VERSION 5.8 ;
BUSBITCHARS "[]" ;
DIVIDERCHAR "/" ;
UNITS
    DATABASE MICRONS 1000 ;
END UNITS

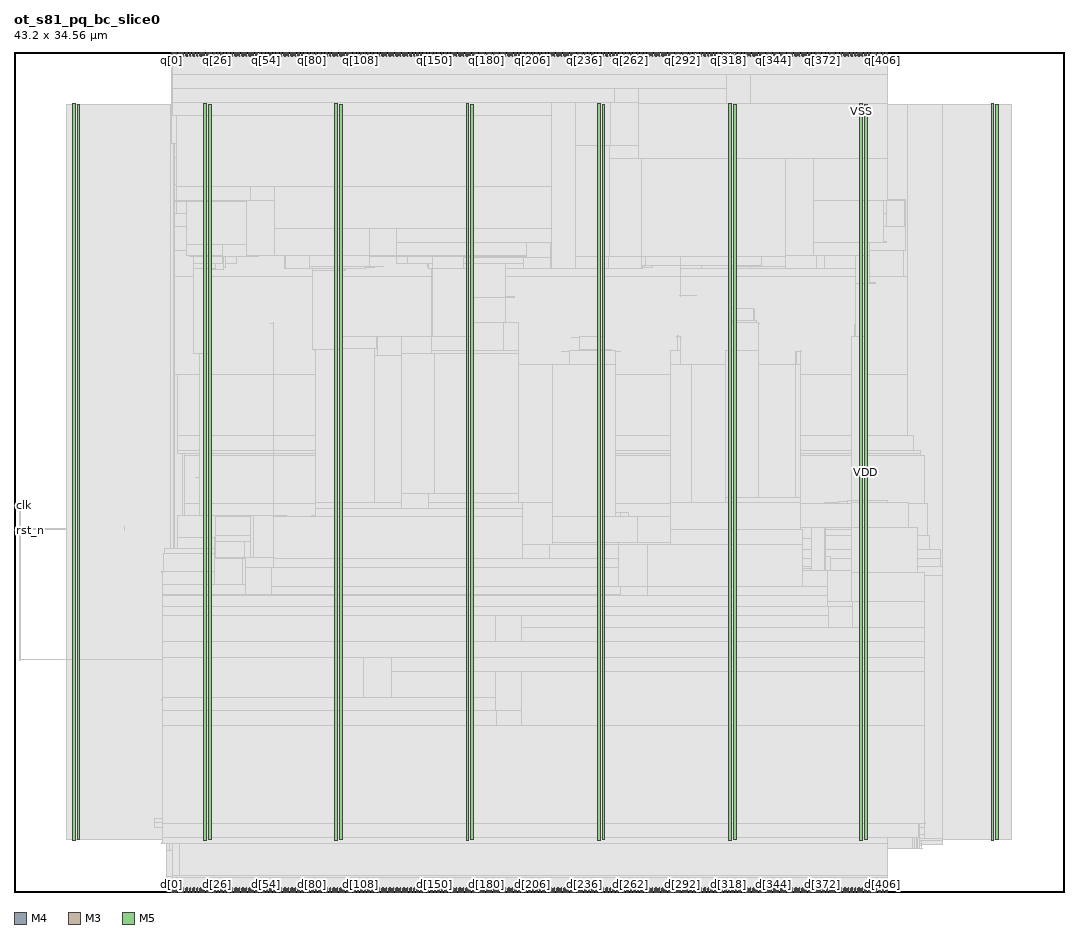
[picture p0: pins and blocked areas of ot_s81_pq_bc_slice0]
MACRO ot_s81_pq_bc_slice0
  FOREIGN ot_s81_pq_bc_slice0 0 0 ;
  CLASS BLOCK ;
  SIZE 43.2 BY 34.56 ;
  PIN clk
    DIRECTION INPUT ;
    USE SIGNAL ;
    PORT
      LAYER M4 ;
        RECT  0 15.888 0.192 15.912 ;
    END
    PORT
      LAYER M4 ;
        RECT  0.156 15.888 0.275 15.912 ;
    END
  END clk
  PIN d[0]
    DIRECTION INPUT ;
    USE SIGNAL ;
    PORT
      LAYER M3 ;
        RECT  6.48 0 6.498 0.144 ;
    END
  END d[0]
  PIN d[100]
    DIRECTION INPUT ;
    USE SIGNAL ;
    PORT
      LAYER M3 ;
        RECT  13.68 0 13.698 0.144 ;
    END
  END d[100]
  PIN d[101]
    DIRECTION INPUT ;
    USE SIGNAL ;
    PORT
      LAYER M5 ;
        RECT  13.728 0 13.752 0.192 ;
    END
  END d[101]
  PIN d[102]
    DIRECTION INPUT ;
    USE SIGNAL ;
    PORT
      LAYER M3 ;
        RECT  13.824 0 13.842 0.144 ;
    END
  END d[102]
  PIN d[103]
    DIRECTION INPUT ;
    USE SIGNAL ;
    PORT
      LAYER M5 ;
        RECT  13.872 0 13.896 0.192 ;
    END
  END d[103]
  PIN d[104]
    DIRECTION INPUT ;
    USE SIGNAL ;
    PORT
      LAYER M3 ;
        RECT  13.968 0 13.986 0.144 ;
    END
  END d[104]
  PIN d[105]
    DIRECTION INPUT ;
    USE SIGNAL ;
    PORT
      LAYER M5 ;
        RECT  14.016 0 14.04 0.192 ;
    END
  END d[105]
  PIN d[106]
    DIRECTION INPUT ;
    USE SIGNAL ;
    PORT
      LAYER M3 ;
        RECT  14.112 0 14.13 0.144 ;
    END
  END d[106]
  PIN d[107]
    DIRECTION INPUT ;
    USE SIGNAL ;
    PORT
      LAYER M5 ;
        RECT  14.16 0 14.184 0.192 ;
    END
  END d[107]
  PIN d[108]
    DIRECTION INPUT ;
    USE SIGNAL ;
    PORT
      LAYER M3 ;
        RECT  14.256 0 14.274 0.144 ;
    END
  END d[108]
  PIN d[109]
    DIRECTION INPUT ;
    USE SIGNAL ;
    PORT
      LAYER M5 ;
        RECT  14.304 0 14.328 0.192 ;
    END
  END d[109]
  PIN d[10]
    DIRECTION INPUT ;
    USE SIGNAL ;
    PORT
      LAYER M3 ;
        RECT  7.2 0 7.218 0.144 ;
    END
  END d[10]
  PIN d[110]
    DIRECTION INPUT ;
    USE SIGNAL ;
    PORT
      LAYER M3 ;
        RECT  14.4 0 14.418 0.144 ;
    END
  END d[110]
  PIN d[111]
    DIRECTION INPUT ;
    USE SIGNAL ;
    PORT
      LAYER M5 ;
        RECT  14.448 0 14.472 0.192 ;
    END
  END d[111]
  PIN d[112]
    DIRECTION INPUT ;
    USE SIGNAL ;
    PORT
      LAYER M3 ;
        RECT  14.544 0 14.562 0.144 ;
    END
  END d[112]
  PIN d[113]
    DIRECTION INPUT ;
    USE SIGNAL ;
    PORT
      LAYER M5 ;
        RECT  14.592 0 14.616 0.192 ;
    END
  END d[113]
  PIN d[114]
    DIRECTION INPUT ;
    USE SIGNAL ;
    PORT
      LAYER M3 ;
        RECT  14.688 0 14.706 0.144 ;
    END
  END d[114]
  PIN d[115]
    DIRECTION INPUT ;
    USE SIGNAL ;
    PORT
      LAYER M5 ;
        RECT  14.736 0 14.76 0.192 ;
    END
  END d[115]
  PIN d[116]
    DIRECTION INPUT ;
    USE SIGNAL ;
    PORT
      LAYER M3 ;
        RECT  14.832 0 14.85 0.144 ;
    END
  END d[116]
  PIN d[117]
    DIRECTION INPUT ;
    USE SIGNAL ;
    PORT
      LAYER M5 ;
        RECT  14.88 0 14.904 0.192 ;
    END
  END d[117]
  PIN d[118]
    DIRECTION INPUT ;
    USE SIGNAL ;
    PORT
      LAYER M3 ;
        RECT  14.976 0 14.994 0.144 ;
    END
  END d[118]
  PIN d[119]
    DIRECTION INPUT ;
    USE SIGNAL ;
    PORT
      LAYER M5 ;
        RECT  15.024 0 15.048 0.192 ;
    END
  END d[119]
  PIN d[11]
    DIRECTION INPUT ;
    USE SIGNAL ;
    PORT
      LAYER M5 ;
        RECT  7.248 0 7.272 0.192 ;
    END
  END d[11]
  PIN d[120]
    DIRECTION INPUT ;
    USE SIGNAL ;
    PORT
      LAYER M3 ;
        RECT  15.12 0 15.138 0.144 ;
    END
  END d[120]
  PIN d[121]
    DIRECTION INPUT ;
    USE SIGNAL ;
    PORT
      LAYER M5 ;
        RECT  15.168 0 15.192 0.192 ;
    END
  END d[121]
  PIN d[122]
    DIRECTION INPUT ;
    USE SIGNAL ;
    PORT
      LAYER M3 ;
        RECT  15.264 0 15.282 0.144 ;
    END
  END d[122]
  PIN d[123]
    DIRECTION INPUT ;
    USE SIGNAL ;
    PORT
      LAYER M5 ;
        RECT  15.312 0 15.336 0.192 ;
    END
  END d[123]
  PIN d[124]
    DIRECTION INPUT ;
    USE SIGNAL ;
    PORT
      LAYER M3 ;
        RECT  15.408 0 15.426 0.144 ;
    END
  END d[124]
  PIN d[125]
    DIRECTION INPUT ;
    USE SIGNAL ;
    PORT
      LAYER M5 ;
        RECT  15.456 0 15.48 0.192 ;
    END
  END d[125]
  PIN d[126]
    DIRECTION INPUT ;
    USE SIGNAL ;
    PORT
      LAYER M3 ;
        RECT  15.552 0 15.57 0.144 ;
    END
  END d[126]
  PIN d[127]
    DIRECTION INPUT ;
    USE SIGNAL ;
    PORT
      LAYER M5 ;
        RECT  15.6 0 15.624 0.192 ;
    END
  END d[127]
  PIN d[128]
    DIRECTION INPUT ;
    USE SIGNAL ;
    PORT
      LAYER M3 ;
        RECT  15.696 0 15.714 0.144 ;
    END
  END d[128]
  PIN d[129]
    DIRECTION INPUT ;
    USE SIGNAL ;
    PORT
      LAYER M5 ;
        RECT  15.744 0 15.768 0.192 ;
    END
  END d[129]
  PIN d[12]
    DIRECTION INPUT ;
    USE SIGNAL ;
    PORT
      LAYER M3 ;
        RECT  7.344 0 7.362 0.144 ;
    END
  END d[12]
  PIN d[130]
    DIRECTION INPUT ;
    USE SIGNAL ;
    PORT
      LAYER M3 ;
        RECT  15.84 0 15.858 0.144 ;
    END
  END d[130]
  PIN d[131]
    DIRECTION INPUT ;
    USE SIGNAL ;
    PORT
      LAYER M5 ;
        RECT  15.888 0 15.912 0.192 ;
    END
  END d[131]
  PIN d[132]
    DIRECTION INPUT ;
    USE SIGNAL ;
    PORT
      LAYER M3 ;
        RECT  15.984 0 16.002 0.144 ;
    END
  END d[132]
  PIN d[133]
    DIRECTION INPUT ;
    USE SIGNAL ;
    PORT
      LAYER M5 ;
        RECT  16.032 0 16.056 0.192 ;
    END
  END d[133]
  PIN d[134]
    DIRECTION INPUT ;
    USE SIGNAL ;
    PORT
      LAYER M3 ;
        RECT  16.128 0 16.146 0.144 ;
    END
  END d[134]
  PIN d[135]
    DIRECTION INPUT ;
    USE SIGNAL ;
    PORT
      LAYER M5 ;
        RECT  16.176 0 16.2 0.192 ;
    END
  END d[135]
  PIN d[136]
    DIRECTION INPUT ;
    USE SIGNAL ;
    PORT
      LAYER M3 ;
        RECT  16.272 0 16.29 0.144 ;
    END
  END d[136]
  PIN d[137]
    DIRECTION INPUT ;
    USE SIGNAL ;
    PORT
      LAYER M5 ;
        RECT  16.32 0 16.344 0.192 ;
    END
  END d[137]
  PIN d[138]
    DIRECTION INPUT ;
    USE SIGNAL ;
    PORT
      LAYER M3 ;
        RECT  16.416 0 16.434 0.144 ;
    END
  END d[138]
  PIN d[139]
    DIRECTION INPUT ;
    USE SIGNAL ;
    PORT
      LAYER M5 ;
        RECT  16.464 0 16.488 0.192 ;
    END
  END d[139]
  PIN d[13]
    DIRECTION INPUT ;
    USE SIGNAL ;
    PORT
      LAYER M5 ;
        RECT  7.392 0 7.416 0.192 ;
    END
  END d[13]
  PIN d[140]
    DIRECTION INPUT ;
    USE SIGNAL ;
    PORT
      LAYER M3 ;
        RECT  16.56 0 16.578 0.144 ;
    END
  END d[140]
  PIN d[141]
    DIRECTION INPUT ;
    USE SIGNAL ;
    PORT
      LAYER M5 ;
        RECT  16.608 0 16.632 0.192 ;
    END
  END d[141]
  PIN d[142]
    DIRECTION INPUT ;
    USE SIGNAL ;
    PORT
      LAYER M3 ;
        RECT  16.704 0 16.722 0.144 ;
    END
  END d[142]
  PIN d[143]
    DIRECTION INPUT ;
    USE SIGNAL ;
    PORT
      LAYER M5 ;
        RECT  16.752 0 16.776 0.192 ;
    END
  END d[143]
  PIN d[144]
    DIRECTION INPUT ;
    USE SIGNAL ;
    PORT
      LAYER M3 ;
        RECT  16.848 0 16.866 0.144 ;
    END
  END d[144]
  PIN d[145]
    DIRECTION INPUT ;
    USE SIGNAL ;
    PORT
      LAYER M5 ;
        RECT  16.896 0 16.92 0.192 ;
    END
  END d[145]
  PIN d[146]
    DIRECTION INPUT ;
    USE SIGNAL ;
    PORT
      LAYER M3 ;
        RECT  16.992 0 17.01 0.144 ;
    END
  END d[146]
  PIN d[147]
    DIRECTION INPUT ;
    USE SIGNAL ;
    PORT
      LAYER M5 ;
        RECT  17.04 0 17.064 0.192 ;
    END
  END d[147]
  PIN d[148]
    DIRECTION INPUT ;
    USE SIGNAL ;
    PORT
      LAYER M3 ;
        RECT  17.136 0 17.154 0.144 ;
    END
  END d[148]
  PIN d[149]
    DIRECTION INPUT ;
    USE SIGNAL ;
    PORT
      LAYER M5 ;
        RECT  17.184 0 17.208 0.192 ;
    END
  END d[149]
  PIN d[14]
    DIRECTION INPUT ;
    USE SIGNAL ;
    PORT
      LAYER M3 ;
        RECT  7.488 0 7.506 0.144 ;
    END
  END d[14]
  PIN d[150]
    DIRECTION INPUT ;
    USE SIGNAL ;
    PORT
      LAYER M3 ;
        RECT  17.28 0 17.298 0.144 ;
    END
  END d[150]
  PIN d[151]
    DIRECTION INPUT ;
    USE SIGNAL ;
    PORT
      LAYER M5 ;
        RECT  17.328 0 17.352 0.192 ;
    END
  END d[151]
  PIN d[152]
    DIRECTION INPUT ;
    USE SIGNAL ;
    PORT
      LAYER M3 ;
        RECT  17.424 0 17.442 0.144 ;
    END
  END d[152]
  PIN d[153]
    DIRECTION INPUT ;
    USE SIGNAL ;
    PORT
      LAYER M5 ;
        RECT  17.472 0 17.496 0.192 ;
    END
  END d[153]
  PIN d[154]
    DIRECTION INPUT ;
    USE SIGNAL ;
    PORT
      LAYER M3 ;
        RECT  17.568 0 17.586 0.144 ;
    END
  END d[154]
  PIN d[155]
    DIRECTION INPUT ;
    USE SIGNAL ;
    PORT
      LAYER M5 ;
        RECT  17.616 0 17.64 0.192 ;
    END
  END d[155]
  PIN d[156]
    DIRECTION INPUT ;
    USE SIGNAL ;
    PORT
      LAYER M3 ;
        RECT  17.712 0 17.73 0.144 ;
    END
  END d[156]
  PIN d[157]
    DIRECTION INPUT ;
    USE SIGNAL ;
    PORT
      LAYER M5 ;
        RECT  17.76 0 17.784 0.192 ;
    END
  END d[157]
  PIN d[158]
    DIRECTION INPUT ;
    USE SIGNAL ;
    PORT
      LAYER M3 ;
        RECT  17.856 0 17.874 0.144 ;
    END
  END d[158]
  PIN d[159]
    DIRECTION INPUT ;
    USE SIGNAL ;
    PORT
      LAYER M5 ;
        RECT  17.904 0 17.928 0.192 ;
    END
  END d[159]
  PIN d[15]
    DIRECTION INPUT ;
    USE SIGNAL ;
    PORT
      LAYER M5 ;
        RECT  7.536 0 7.56 0.192 ;
    END
  END d[15]
  PIN d[160]
    DIRECTION INPUT ;
    USE SIGNAL ;
    PORT
      LAYER M3 ;
        RECT  18 0 18.018 0.144 ;
    END
  END d[160]
  PIN d[161]
    DIRECTION INPUT ;
    USE SIGNAL ;
    PORT
      LAYER M5 ;
        RECT  18.048 0 18.072 0.192 ;
    END
  END d[161]
  PIN d[162]
    DIRECTION INPUT ;
    USE SIGNAL ;
    PORT
      LAYER M3 ;
        RECT  18.144 0 18.162 0.144 ;
    END
  END d[162]
  PIN d[163]
    DIRECTION INPUT ;
    USE SIGNAL ;
    PORT
      LAYER M5 ;
        RECT  18.192 0 18.216 0.192 ;
    END
  END d[163]
  PIN d[164]
    DIRECTION INPUT ;
    USE SIGNAL ;
    PORT
      LAYER M3 ;
        RECT  18.288 0 18.306 0.144 ;
    END
  END d[164]
  PIN d[165]
    DIRECTION INPUT ;
    USE SIGNAL ;
    PORT
      LAYER M5 ;
        RECT  18.336 0 18.36 0.192 ;
    END
  END d[165]
  PIN d[166]
    DIRECTION INPUT ;
    USE SIGNAL ;
    PORT
      LAYER M3 ;
        RECT  18.432 0 18.45 0.144 ;
    END
  END d[166]
  PIN d[167]
    DIRECTION INPUT ;
    USE SIGNAL ;
    PORT
      LAYER M5 ;
        RECT  18.48 0 18.504 0.192 ;
    END
  END d[167]
  PIN d[168]
    DIRECTION INPUT ;
    USE SIGNAL ;
    PORT
      LAYER M3 ;
        RECT  18.576 0 18.594 0.144 ;
    END
  END d[168]
  PIN d[169]
    DIRECTION INPUT ;
    USE SIGNAL ;
    PORT
      LAYER M5 ;
        RECT  18.624 0 18.648 0.192 ;
    END
  END d[169]
  PIN d[16]
    DIRECTION INPUT ;
    USE SIGNAL ;
    PORT
      LAYER M3 ;
        RECT  7.632 0 7.65 0.144 ;
    END
  END d[16]
  PIN d[170]
    DIRECTION INPUT ;
    USE SIGNAL ;
    PORT
      LAYER M3 ;
        RECT  18.72 0 18.738 0.144 ;
    END
  END d[170]
  PIN d[171]
    DIRECTION INPUT ;
    USE SIGNAL ;
    PORT
      LAYER M5 ;
        RECT  18.768 0 18.792 0.192 ;
    END
  END d[171]
  PIN d[172]
    DIRECTION INPUT ;
    USE SIGNAL ;
    PORT
      LAYER M3 ;
        RECT  18.864 0 18.882 0.144 ;
    END
  END d[172]
  PIN d[173]
    DIRECTION INPUT ;
    USE SIGNAL ;
    PORT
      LAYER M5 ;
        RECT  18.912 0 18.936 0.192 ;
    END
  END d[173]
  PIN d[174]
    DIRECTION INPUT ;
    USE SIGNAL ;
    PORT
      LAYER M3 ;
        RECT  19.008 0 19.026 0.144 ;
    END
  END d[174]
  PIN d[175]
    DIRECTION INPUT ;
    USE SIGNAL ;
    PORT
      LAYER M5 ;
        RECT  19.056 0 19.08 0.192 ;
    END
  END d[175]
  PIN d[176]
    DIRECTION INPUT ;
    USE SIGNAL ;
    PORT
      LAYER M3 ;
        RECT  19.152 0 19.17 0.144 ;
    END
  END d[176]
  PIN d[177]
    DIRECTION INPUT ;
    USE SIGNAL ;
    PORT
      LAYER M5 ;
        RECT  19.2 0 19.224 0.192 ;
    END
  END d[177]
  PIN d[178]
    DIRECTION INPUT ;
    USE SIGNAL ;
    PORT
      LAYER M3 ;
        RECT  19.296 0 19.314 0.144 ;
    END
  END d[178]
  PIN d[179]
    DIRECTION INPUT ;
    USE SIGNAL ;
    PORT
      LAYER M5 ;
        RECT  19.344 0 19.368 0.192 ;
    END
  END d[179]
  PIN d[17]
    DIRECTION INPUT ;
    USE SIGNAL ;
    PORT
      LAYER M5 ;
        RECT  7.68 0 7.704 0.192 ;
    END
  END d[17]
  PIN d[180]
    DIRECTION INPUT ;
    USE SIGNAL ;
    PORT
      LAYER M3 ;
        RECT  19.44 0 19.458 0.144 ;
    END
  END d[180]
  PIN d[181]
    DIRECTION INPUT ;
    USE SIGNAL ;
    PORT
      LAYER M5 ;
        RECT  19.488 0 19.512 0.192 ;
    END
  END d[181]
  PIN d[182]
    DIRECTION INPUT ;
    USE SIGNAL ;
    PORT
      LAYER M3 ;
        RECT  19.584 0 19.602 0.144 ;
    END
  END d[182]
  PIN d[183]
    DIRECTION INPUT ;
    USE SIGNAL ;
    PORT
      LAYER M5 ;
        RECT  19.632 0 19.656 0.192 ;
    END
  END d[183]
  PIN d[184]
    DIRECTION INPUT ;
    USE SIGNAL ;
    PORT
      LAYER M3 ;
        RECT  19.728 0 19.746 0.144 ;
    END
  END d[184]
  PIN d[185]
    DIRECTION INPUT ;
    USE SIGNAL ;
    PORT
      LAYER M5 ;
        RECT  19.776 0 19.8 0.192 ;
    END
  END d[185]
  PIN d[186]
    DIRECTION INPUT ;
    USE SIGNAL ;
    PORT
      LAYER M3 ;
        RECT  19.872 0 19.89 0.144 ;
    END
  END d[186]
  PIN d[187]
    DIRECTION INPUT ;
    USE SIGNAL ;
    PORT
      LAYER M5 ;
        RECT  19.92 0 19.944 0.192 ;
    END
  END d[187]
  PIN d[188]
    DIRECTION INPUT ;
    USE SIGNAL ;
    PORT
      LAYER M3 ;
        RECT  20.016 0 20.034 0.144 ;
    END
  END d[188]
  PIN d[189]
    DIRECTION INPUT ;
    USE SIGNAL ;
    PORT
      LAYER M5 ;
        RECT  20.064 0 20.088 0.192 ;
    END
  END d[189]
  PIN d[18]
    DIRECTION INPUT ;
    USE SIGNAL ;
    PORT
      LAYER M3 ;
        RECT  7.776 0 7.794 0.144 ;
    END
  END d[18]
  PIN d[190]
    DIRECTION INPUT ;
    USE SIGNAL ;
    PORT
      LAYER M3 ;
        RECT  20.16 0 20.178 0.144 ;
    END
  END d[190]
  PIN d[191]
    DIRECTION INPUT ;
    USE SIGNAL ;
    PORT
      LAYER M5 ;
        RECT  20.208 0 20.232 0.192 ;
    END
  END d[191]
  PIN d[192]
    DIRECTION INPUT ;
    USE SIGNAL ;
    PORT
      LAYER M3 ;
        RECT  20.304 0 20.322 0.144 ;
    END
  END d[192]
  PIN d[193]
    DIRECTION INPUT ;
    USE SIGNAL ;
    PORT
      LAYER M5 ;
        RECT  20.352 0 20.376 0.192 ;
    END
  END d[193]
  PIN d[194]
    DIRECTION INPUT ;
    USE SIGNAL ;
    PORT
      LAYER M3 ;
        RECT  20.448 0 20.466 0.144 ;
    END
  END d[194]
  PIN d[195]
    DIRECTION INPUT ;
    USE SIGNAL ;
    PORT
      LAYER M5 ;
        RECT  20.496 0 20.52 0.192 ;
    END
  END d[195]
  PIN d[196]
    DIRECTION INPUT ;
    USE SIGNAL ;
    PORT
      LAYER M3 ;
        RECT  20.592 0 20.61 0.144 ;
    END
  END d[196]
  PIN d[197]
    DIRECTION INPUT ;
    USE SIGNAL ;
    PORT
      LAYER M5 ;
        RECT  20.64 0 20.664 0.192 ;
    END
  END d[197]
  PIN d[198]
    DIRECTION INPUT ;
    USE SIGNAL ;
    PORT
      LAYER M3 ;
        RECT  20.736 0 20.754 0.144 ;
    END
  END d[198]
  PIN d[199]
    DIRECTION INPUT ;
    USE SIGNAL ;
    PORT
      LAYER M5 ;
        RECT  20.784 0 20.808 0.192 ;
    END
  END d[199]
  PIN d[19]
    DIRECTION INPUT ;
    USE SIGNAL ;
    PORT
      LAYER M5 ;
        RECT  7.824 0 7.848 0.192 ;
    END
  END d[19]
  PIN d[1]
    DIRECTION INPUT ;
    USE SIGNAL ;
    PORT
      LAYER M5 ;
        RECT  6.528 0 6.552 0.192 ;
    END
  END d[1]
  PIN d[200]
    DIRECTION INPUT ;
    USE SIGNAL ;
    PORT
      LAYER M3 ;
        RECT  20.88 0 20.898 0.144 ;
    END
  END d[200]
  PIN d[201]
    DIRECTION INPUT ;
    USE SIGNAL ;
    PORT
      LAYER M5 ;
        RECT  20.928 0 20.952 0.192 ;
    END
  END d[201]
  PIN d[202]
    DIRECTION INPUT ;
    USE SIGNAL ;
    PORT
      LAYER M3 ;
        RECT  21.024 0 21.042 0.144 ;
    END
  END d[202]
  PIN d[203]
    DIRECTION INPUT ;
    USE SIGNAL ;
    PORT
      LAYER M5 ;
        RECT  21.072 0 21.096 0.192 ;
    END
  END d[203]
  PIN d[204]
    DIRECTION INPUT ;
    USE SIGNAL ;
    PORT
      LAYER M3 ;
        RECT  21.168 0 21.186 0.144 ;
    END
  END d[204]
  PIN d[205]
    DIRECTION INPUT ;
    USE SIGNAL ;
    PORT
      LAYER M5 ;
        RECT  21.216 0 21.24 0.192 ;
    END
  END d[205]
  PIN d[206]
    DIRECTION INPUT ;
    USE SIGNAL ;
    PORT
      LAYER M3 ;
        RECT  21.312 0 21.33 0.144 ;
    END
  END d[206]
  PIN d[207]
    DIRECTION INPUT ;
    USE SIGNAL ;
    PORT
      LAYER M5 ;
        RECT  21.36 0 21.384 0.192 ;
    END
  END d[207]
  PIN d[208]
    DIRECTION INPUT ;
    USE SIGNAL ;
    PORT
      LAYER M3 ;
        RECT  21.456 0 21.474 0.144 ;
    END
  END d[208]
  PIN d[209]
    DIRECTION INPUT ;
    USE SIGNAL ;
    PORT
      LAYER M5 ;
        RECT  21.504 0 21.528 0.192 ;
    END
  END d[209]
  PIN d[20]
    DIRECTION INPUT ;
    USE SIGNAL ;
    PORT
      LAYER M3 ;
        RECT  7.92 0 7.938 0.144 ;
    END
  END d[20]
  PIN d[210]
    DIRECTION INPUT ;
    USE SIGNAL ;
    PORT
      LAYER M3 ;
        RECT  21.6 0 21.618 0.144 ;
    END
  END d[210]
  PIN d[211]
    DIRECTION INPUT ;
    USE SIGNAL ;
    PORT
      LAYER M5 ;
        RECT  21.648 0 21.672 0.192 ;
    END
  END d[211]
  PIN d[212]
    DIRECTION INPUT ;
    USE SIGNAL ;
    PORT
      LAYER M3 ;
        RECT  21.744 0 21.762 0.144 ;
    END
  END d[212]
  PIN d[213]
    DIRECTION INPUT ;
    USE SIGNAL ;
    PORT
      LAYER M5 ;
        RECT  21.792 0 21.816 0.192 ;
    END
  END d[213]
  PIN d[214]
    DIRECTION INPUT ;
    USE SIGNAL ;
    PORT
      LAYER M3 ;
        RECT  21.888 0 21.906 0.144 ;
    END
  END d[214]
  PIN d[215]
    DIRECTION INPUT ;
    USE SIGNAL ;
    PORT
      LAYER M5 ;
        RECT  21.936 0 21.96 0.192 ;
    END
  END d[215]
  PIN d[216]
    DIRECTION INPUT ;
    USE SIGNAL ;
    PORT
      LAYER M3 ;
        RECT  22.032 0 22.05 0.144 ;
    END
  END d[216]
  PIN d[217]
    DIRECTION INPUT ;
    USE SIGNAL ;
    PORT
      LAYER M5 ;
        RECT  22.08 0 22.104 0.192 ;
    END
  END d[217]
  PIN d[218]
    DIRECTION INPUT ;
    USE SIGNAL ;
    PORT
      LAYER M3 ;
        RECT  22.176 0 22.194 0.144 ;
    END
  END d[218]
  PIN d[219]
    DIRECTION INPUT ;
    USE SIGNAL ;
    PORT
      LAYER M5 ;
        RECT  22.224 0 22.248 0.192 ;
    END
  END d[219]
  PIN d[21]
    DIRECTION INPUT ;
    USE SIGNAL ;
    PORT
      LAYER M5 ;
        RECT  7.968 0 7.992 0.192 ;
    END
  END d[21]
  PIN d[220]
    DIRECTION INPUT ;
    USE SIGNAL ;
    PORT
      LAYER M3 ;
        RECT  22.32 0 22.338 0.144 ;
    END
  END d[220]
  PIN d[221]
    DIRECTION INPUT ;
    USE SIGNAL ;
    PORT
      LAYER M5 ;
        RECT  22.368 0 22.392 0.192 ;
    END
  END d[221]
  PIN d[222]
    DIRECTION INPUT ;
    USE SIGNAL ;
    PORT
      LAYER M3 ;
        RECT  22.464 0 22.482 0.144 ;
    END
  END d[222]
  PIN d[223]
    DIRECTION INPUT ;
    USE SIGNAL ;
    PORT
      LAYER M5 ;
        RECT  22.512 0 22.536 0.192 ;
    END
  END d[223]
  PIN d[224]
    DIRECTION INPUT ;
    USE SIGNAL ;
    PORT
      LAYER M3 ;
        RECT  22.608 0 22.626 0.144 ;
    END
  END d[224]
  PIN d[225]
    DIRECTION INPUT ;
    USE SIGNAL ;
    PORT
      LAYER M5 ;
        RECT  22.656 0 22.68 0.192 ;
    END
  END d[225]
  PIN d[226]
    DIRECTION INPUT ;
    USE SIGNAL ;
    PORT
      LAYER M3 ;
        RECT  22.752 0 22.77 0.144 ;
    END
  END d[226]
  PIN d[227]
    DIRECTION INPUT ;
    USE SIGNAL ;
    PORT
      LAYER M5 ;
        RECT  22.8 0 22.824 0.192 ;
    END
  END d[227]
  PIN d[228]
    DIRECTION INPUT ;
    USE SIGNAL ;
    PORT
      LAYER M3 ;
        RECT  22.896 0 22.914 0.144 ;
    END
  END d[228]
  PIN d[229]
    DIRECTION INPUT ;
    USE SIGNAL ;
    PORT
      LAYER M5 ;
        RECT  22.944 0 22.968 0.192 ;
    END
  END d[229]
  PIN d[22]
    DIRECTION INPUT ;
    USE SIGNAL ;
    PORT
      LAYER M3 ;
        RECT  8.064 0 8.082 0.144 ;
    END
  END d[22]
  PIN d[230]
    DIRECTION INPUT ;
    USE SIGNAL ;
    PORT
      LAYER M3 ;
        RECT  23.04 0 23.058 0.144 ;
    END
  END d[230]
  PIN d[231]
    DIRECTION INPUT ;
    USE SIGNAL ;
    PORT
      LAYER M5 ;
        RECT  23.088 0 23.112 0.192 ;
    END
  END d[231]
  PIN d[232]
    DIRECTION INPUT ;
    USE SIGNAL ;
    PORT
      LAYER M3 ;
        RECT  23.184 0 23.202 0.144 ;
    END
  END d[232]
  PIN d[233]
    DIRECTION INPUT ;
    USE SIGNAL ;
    PORT
      LAYER M5 ;
        RECT  23.232 0 23.256 0.192 ;
    END
  END d[233]
  PIN d[234]
    DIRECTION INPUT ;
    USE SIGNAL ;
    PORT
      LAYER M3 ;
        RECT  23.328 0 23.346 0.144 ;
    END
  END d[234]
  PIN d[235]
    DIRECTION INPUT ;
    USE SIGNAL ;
    PORT
      LAYER M5 ;
        RECT  23.376 0 23.4 0.192 ;
    END
  END d[235]
  PIN d[236]
    DIRECTION INPUT ;
    USE SIGNAL ;
    PORT
      LAYER M3 ;
        RECT  23.472 0 23.49 0.144 ;
    END
  END d[236]
  PIN d[237]
    DIRECTION INPUT ;
    USE SIGNAL ;
    PORT
      LAYER M5 ;
        RECT  23.52 0 23.544 0.192 ;
    END
  END d[237]
  PIN d[238]
    DIRECTION INPUT ;
    USE SIGNAL ;
    PORT
      LAYER M3 ;
        RECT  23.616 0 23.634 0.144 ;
    END
  END d[238]
  PIN d[239]
    DIRECTION INPUT ;
    USE SIGNAL ;
    PORT
      LAYER M5 ;
        RECT  23.664 0 23.688 0.192 ;
    END
  END d[239]
  PIN d[23]
    DIRECTION INPUT ;
    USE SIGNAL ;
    PORT
      LAYER M5 ;
        RECT  8.112 0 8.136 0.192 ;
    END
  END d[23]
  PIN d[240]
    DIRECTION INPUT ;
    USE SIGNAL ;
    PORT
      LAYER M3 ;
        RECT  23.76 0 23.778 0.144 ;
    END
  END d[240]
  PIN d[241]
    DIRECTION INPUT ;
    USE SIGNAL ;
    PORT
      LAYER M5 ;
        RECT  23.808 0 23.832 0.192 ;
    END
  END d[241]
  PIN d[242]
    DIRECTION INPUT ;
    USE SIGNAL ;
    PORT
      LAYER M3 ;
        RECT  23.904 0 23.922 0.144 ;
    END
  END d[242]
  PIN d[243]
    DIRECTION INPUT ;
    USE SIGNAL ;
    PORT
      LAYER M5 ;
        RECT  23.952 0 23.976 0.192 ;
    END
  END d[243]
  PIN d[244]
    DIRECTION INPUT ;
    USE SIGNAL ;
    PORT
      LAYER M3 ;
        RECT  24.048 0 24.066 0.144 ;
    END
  END d[244]
  PIN d[245]
    DIRECTION INPUT ;
    USE SIGNAL ;
    PORT
      LAYER M5 ;
        RECT  24.096 0 24.12 0.192 ;
    END
  END d[245]
  PIN d[246]
    DIRECTION INPUT ;
    USE SIGNAL ;
    PORT
      LAYER M3 ;
        RECT  24.192 0 24.21 0.144 ;
    END
  END d[246]
  PIN d[247]
    DIRECTION INPUT ;
    USE SIGNAL ;
    PORT
      LAYER M5 ;
        RECT  24.24 0 24.264 0.192 ;
    END
  END d[247]
  PIN d[248]
    DIRECTION INPUT ;
    USE SIGNAL ;
    PORT
      LAYER M3 ;
        RECT  24.336 0 24.354 0.144 ;
    END
  END d[248]
  PIN d[249]
    DIRECTION INPUT ;
    USE SIGNAL ;
    PORT
      LAYER M5 ;
        RECT  24.384 0 24.408 0.192 ;
    END
  END d[249]
  PIN d[24]
    DIRECTION INPUT ;
    USE SIGNAL ;
    PORT
      LAYER M3 ;
        RECT  8.208 0 8.226 0.144 ;
    END
  END d[24]
  PIN d[250]
    DIRECTION INPUT ;
    USE SIGNAL ;
    PORT
      LAYER M3 ;
        RECT  24.48 0 24.498 0.144 ;
    END
  END d[250]
  PIN d[251]
    DIRECTION INPUT ;
    USE SIGNAL ;
    PORT
      LAYER M5 ;
        RECT  24.528 0 24.552 0.192 ;
    END
  END d[251]
  PIN d[252]
    DIRECTION INPUT ;
    USE SIGNAL ;
    PORT
      LAYER M3 ;
        RECT  24.624 0 24.642 0.144 ;
    END
  END d[252]
  PIN d[253]
    DIRECTION INPUT ;
    USE SIGNAL ;
    PORT
      LAYER M5 ;
        RECT  24.672 0 24.696 0.192 ;
    END
  END d[253]
  PIN d[254]
    DIRECTION INPUT ;
    USE SIGNAL ;
    PORT
      LAYER M3 ;
        RECT  24.768 0 24.786 0.144 ;
    END
  END d[254]
  PIN d[255]
    DIRECTION INPUT ;
    USE SIGNAL ;
    PORT
      LAYER M5 ;
        RECT  24.816 0 24.84 0.192 ;
    END
  END d[255]
  PIN d[256]
    DIRECTION INPUT ;
    USE SIGNAL ;
    PORT
      LAYER M3 ;
        RECT  24.912 0 24.93 0.144 ;
    END
  END d[256]
  PIN d[257]
    DIRECTION INPUT ;
    USE SIGNAL ;
    PORT
      LAYER M5 ;
        RECT  24.96 0 24.984 0.192 ;
    END
  END d[257]
  PIN d[258]
    DIRECTION INPUT ;
    USE SIGNAL ;
    PORT
      LAYER M3 ;
        RECT  25.056 0 25.074 0.144 ;
    END
  END d[258]
  PIN d[259]
    DIRECTION INPUT ;
    USE SIGNAL ;
    PORT
      LAYER M5 ;
        RECT  25.104 0 25.128 0.192 ;
    END
  END d[259]
  PIN d[25]
    DIRECTION INPUT ;
    USE SIGNAL ;
    PORT
      LAYER M5 ;
        RECT  8.256 0 8.28 0.192 ;
    END
  END d[25]
  PIN d[260]
    DIRECTION INPUT ;
    USE SIGNAL ;
    PORT
      LAYER M3 ;
        RECT  25.2 0 25.218 0.144 ;
    END
  END d[260]
  PIN d[261]
    DIRECTION INPUT ;
    USE SIGNAL ;
    PORT
      LAYER M5 ;
        RECT  25.248 0 25.272 0.192 ;
    END
  END d[261]
  PIN d[262]
    DIRECTION INPUT ;
    USE SIGNAL ;
    PORT
      LAYER M3 ;
        RECT  25.344 0 25.362 0.144 ;
    END
  END d[262]
  PIN d[263]
    DIRECTION INPUT ;
    USE SIGNAL ;
    PORT
      LAYER M5 ;
        RECT  25.392 0 25.416 0.192 ;
    END
  END d[263]
  PIN d[264]
    DIRECTION INPUT ;
    USE SIGNAL ;
    PORT
      LAYER M3 ;
        RECT  25.488 0 25.506 0.144 ;
    END
  END d[264]
  PIN d[265]
    DIRECTION INPUT ;
    USE SIGNAL ;
    PORT
      LAYER M5 ;
        RECT  25.536 0 25.56 0.192 ;
    END
  END d[265]
  PIN d[266]
    DIRECTION INPUT ;
    USE SIGNAL ;
    PORT
      LAYER M3 ;
        RECT  25.632 0 25.65 0.144 ;
    END
  END d[266]
  PIN d[267]
    DIRECTION INPUT ;
    USE SIGNAL ;
    PORT
      LAYER M5 ;
        RECT  25.68 0 25.704 0.192 ;
    END
  END d[267]
  PIN d[268]
    DIRECTION INPUT ;
    USE SIGNAL ;
    PORT
      LAYER M3 ;
        RECT  25.776 0 25.794 0.144 ;
    END
  END d[268]
  PIN d[269]
    DIRECTION INPUT ;
    USE SIGNAL ;
    PORT
      LAYER M5 ;
        RECT  25.824 0 25.848 0.192 ;
    END
  END d[269]
  PIN d[26]
    DIRECTION INPUT ;
    USE SIGNAL ;
    PORT
      LAYER M3 ;
        RECT  8.352 0 8.37 0.144 ;
    END
  END d[26]
  PIN d[270]
    DIRECTION INPUT ;
    USE SIGNAL ;
    PORT
      LAYER M3 ;
        RECT  25.92 0 25.938 0.144 ;
    END
  END d[270]
  PIN d[271]
    DIRECTION INPUT ;
    USE SIGNAL ;
    PORT
      LAYER M5 ;
        RECT  25.968 0 25.992 0.192 ;
    END
  END d[271]
  PIN d[272]
    DIRECTION INPUT ;
    USE SIGNAL ;
    PORT
      LAYER M3 ;
        RECT  26.064 0 26.082 0.144 ;
    END
  END d[272]
  PIN d[273]
    DIRECTION INPUT ;
    USE SIGNAL ;
    PORT
      LAYER M5 ;
        RECT  26.112 0 26.136 0.192 ;
    END
  END d[273]
  PIN d[274]
    DIRECTION INPUT ;
    USE SIGNAL ;
    PORT
      LAYER M3 ;
        RECT  26.208 0 26.226 0.144 ;
    END
  END d[274]
  PIN d[275]
    DIRECTION INPUT ;
    USE SIGNAL ;
    PORT
      LAYER M5 ;
        RECT  26.256 0 26.28 0.192 ;
    END
  END d[275]
  PIN d[276]
    DIRECTION INPUT ;
    USE SIGNAL ;
    PORT
      LAYER M3 ;
        RECT  26.352 0 26.37 0.144 ;
    END
  END d[276]
  PIN d[277]
    DIRECTION INPUT ;
    USE SIGNAL ;
    PORT
      LAYER M5 ;
        RECT  26.4 0 26.424 0.192 ;
    END
  END d[277]
  PIN d[278]
    DIRECTION INPUT ;
    USE SIGNAL ;
    PORT
      LAYER M3 ;
        RECT  26.496 0 26.514 0.144 ;
    END
  END d[278]
  PIN d[279]
    DIRECTION INPUT ;
    USE SIGNAL ;
    PORT
      LAYER M5 ;
        RECT  26.544 0 26.568 0.192 ;
    END
  END d[279]
  PIN d[27]
    DIRECTION INPUT ;
    USE SIGNAL ;
    PORT
      LAYER M5 ;
        RECT  8.4 0 8.424 0.192 ;
    END
  END d[27]
  PIN d[280]
    DIRECTION INPUT ;
    USE SIGNAL ;
    PORT
      LAYER M3 ;
        RECT  26.64 0 26.658 0.144 ;
    END
  END d[280]
  PIN d[281]
    DIRECTION INPUT ;
    USE SIGNAL ;
    PORT
      LAYER M5 ;
        RECT  26.688 0 26.712 0.192 ;
    END
  END d[281]
  PIN d[282]
    DIRECTION INPUT ;
    USE SIGNAL ;
    PORT
      LAYER M3 ;
        RECT  26.784 0 26.802 0.144 ;
    END
  END d[282]
  PIN d[283]
    DIRECTION INPUT ;
    USE SIGNAL ;
    PORT
      LAYER M5 ;
        RECT  26.832 0 26.856 0.192 ;
    END
  END d[283]
  PIN d[284]
    DIRECTION INPUT ;
    USE SIGNAL ;
    PORT
      LAYER M3 ;
        RECT  26.928 0 26.946 0.144 ;
    END
  END d[284]
  PIN d[285]
    DIRECTION INPUT ;
    USE SIGNAL ;
    PORT
      LAYER M5 ;
        RECT  26.976 0 27 0.192 ;
    END
  END d[285]
  PIN d[286]
    DIRECTION INPUT ;
    USE SIGNAL ;
    PORT
      LAYER M3 ;
        RECT  27.072 0 27.09 0.144 ;
    END
  END d[286]
  PIN d[287]
    DIRECTION INPUT ;
    USE SIGNAL ;
    PORT
      LAYER M5 ;
        RECT  27.12 0 27.144 0.192 ;
    END
  END d[287]
  PIN d[288]
    DIRECTION INPUT ;
    USE SIGNAL ;
    PORT
      LAYER M3 ;
        RECT  27.216 0 27.234 0.144 ;
    END
  END d[288]
  PIN d[289]
    DIRECTION INPUT ;
    USE SIGNAL ;
    PORT
      LAYER M5 ;
        RECT  27.264 0 27.288 0.192 ;
    END
  END d[289]
  PIN d[28]
    DIRECTION INPUT ;
    USE SIGNAL ;
    PORT
      LAYER M3 ;
        RECT  8.496 0 8.514 0.144 ;
    END
  END d[28]
  PIN d[290]
    DIRECTION INPUT ;
    USE SIGNAL ;
    PORT
      LAYER M3 ;
        RECT  27.36 0 27.378 0.144 ;
    END
  END d[290]
  PIN d[291]
    DIRECTION INPUT ;
    USE SIGNAL ;
    PORT
      LAYER M5 ;
        RECT  27.408 0 27.432 0.192 ;
    END
  END d[291]
  PIN d[292]
    DIRECTION INPUT ;
    USE SIGNAL ;
    PORT
      LAYER M3 ;
        RECT  27.504 0 27.522 0.144 ;
    END
  END d[292]
  PIN d[293]
    DIRECTION INPUT ;
    USE SIGNAL ;
    PORT
      LAYER M5 ;
        RECT  27.552 0 27.576 0.192 ;
    END
  END d[293]
  PIN d[294]
    DIRECTION INPUT ;
    USE SIGNAL ;
    PORT
      LAYER M3 ;
        RECT  27.648 0 27.666 0.144 ;
    END
  END d[294]
  PIN d[295]
    DIRECTION INPUT ;
    USE SIGNAL ;
    PORT
      LAYER M5 ;
        RECT  27.696 0 27.72 0.192 ;
    END
  END d[295]
  PIN d[296]
    DIRECTION INPUT ;
    USE SIGNAL ;
    PORT
      LAYER M3 ;
        RECT  27.792 0 27.81 0.144 ;
    END
  END d[296]
  PIN d[297]
    DIRECTION INPUT ;
    USE SIGNAL ;
    PORT
      LAYER M5 ;
        RECT  27.84 0 27.864 0.192 ;
    END
  END d[297]
  PIN d[298]
    DIRECTION INPUT ;
    USE SIGNAL ;
    PORT
      LAYER M3 ;
        RECT  27.936 0 27.954 0.144 ;
    END
  END d[298]
  PIN d[299]
    DIRECTION INPUT ;
    USE SIGNAL ;
    PORT
      LAYER M5 ;
        RECT  27.984 0 28.008 0.192 ;
    END
  END d[299]
  PIN d[29]
    DIRECTION INPUT ;
    USE SIGNAL ;
    PORT
      LAYER M5 ;
        RECT  8.544 0 8.568 0.192 ;
    END
  END d[29]
  PIN d[2]
    DIRECTION INPUT ;
    USE SIGNAL ;
    PORT
      LAYER M3 ;
        RECT  6.624 0 6.642 0.144 ;
    END
  END d[2]
  PIN d[300]
    DIRECTION INPUT ;
    USE SIGNAL ;
    PORT
      LAYER M3 ;
        RECT  28.08 0 28.098 0.144 ;
    END
  END d[300]
  PIN d[301]
    DIRECTION INPUT ;
    USE SIGNAL ;
    PORT
      LAYER M5 ;
        RECT  28.128 0 28.152 0.192 ;
    END
  END d[301]
  PIN d[302]
    DIRECTION INPUT ;
    USE SIGNAL ;
    PORT
      LAYER M3 ;
        RECT  28.224 0 28.242 0.144 ;
    END
  END d[302]
  PIN d[303]
    DIRECTION INPUT ;
    USE SIGNAL ;
    PORT
      LAYER M5 ;
        RECT  28.272 0 28.296 0.192 ;
    END
  END d[303]
  PIN d[304]
    DIRECTION INPUT ;
    USE SIGNAL ;
    PORT
      LAYER M3 ;
        RECT  28.368 0 28.386 0.144 ;
    END
  END d[304]
  PIN d[305]
    DIRECTION INPUT ;
    USE SIGNAL ;
    PORT
      LAYER M5 ;
        RECT  28.416 0 28.44 0.192 ;
    END
  END d[305]
  PIN d[306]
    DIRECTION INPUT ;
    USE SIGNAL ;
    PORT
      LAYER M3 ;
        RECT  28.512 0 28.53 0.144 ;
    END
  END d[306]
  PIN d[307]
    DIRECTION INPUT ;
    USE SIGNAL ;
    PORT
      LAYER M5 ;
        RECT  28.56 0 28.584 0.192 ;
    END
  END d[307]
  PIN d[308]
    DIRECTION INPUT ;
    USE SIGNAL ;
    PORT
      LAYER M3 ;
        RECT  28.656 0 28.674 0.144 ;
    END
  END d[308]
  PIN d[309]
    DIRECTION INPUT ;
    USE SIGNAL ;
    PORT
      LAYER M5 ;
        RECT  28.704 0 28.728 0.192 ;
    END
  END d[309]
  PIN d[30]
    DIRECTION INPUT ;
    USE SIGNAL ;
    PORT
      LAYER M3 ;
        RECT  8.64 0 8.658 0.144 ;
    END
  END d[30]
  PIN d[310]
    DIRECTION INPUT ;
    USE SIGNAL ;
    PORT
      LAYER M3 ;
        RECT  28.8 0 28.818 0.144 ;
    END
  END d[310]
  PIN d[311]
    DIRECTION INPUT ;
    USE SIGNAL ;
    PORT
      LAYER M5 ;
        RECT  28.848 0 28.872 0.192 ;
    END
  END d[311]
  PIN d[312]
    DIRECTION INPUT ;
    USE SIGNAL ;
    PORT
      LAYER M3 ;
        RECT  28.944 0 28.962 0.144 ;
    END
  END d[312]
  PIN d[313]
    DIRECTION INPUT ;
    USE SIGNAL ;
    PORT
      LAYER M5 ;
        RECT  28.992 0 29.016 0.192 ;
    END
  END d[313]
  PIN d[314]
    DIRECTION INPUT ;
    USE SIGNAL ;
    PORT
      LAYER M3 ;
        RECT  29.088 0 29.106 0.144 ;
    END
  END d[314]
  PIN d[315]
    DIRECTION INPUT ;
    USE SIGNAL ;
    PORT
      LAYER M5 ;
        RECT  29.136 0 29.16 0.192 ;
    END
  END d[315]
  PIN d[316]
    DIRECTION INPUT ;
    USE SIGNAL ;
    PORT
      LAYER M3 ;
        RECT  29.232 0 29.25 0.144 ;
    END
  END d[316]
  PIN d[317]
    DIRECTION INPUT ;
    USE SIGNAL ;
    PORT
      LAYER M5 ;
        RECT  29.28 0 29.304 0.192 ;
    END
  END d[317]
  PIN d[318]
    DIRECTION INPUT ;
    USE SIGNAL ;
    PORT
      LAYER M3 ;
        RECT  29.376 0 29.394 0.144 ;
    END
  END d[318]
  PIN d[319]
    DIRECTION INPUT ;
    USE SIGNAL ;
    PORT
      LAYER M5 ;
        RECT  29.424 0 29.448 0.192 ;
    END
  END d[319]
  PIN d[31]
    DIRECTION INPUT ;
    USE SIGNAL ;
    PORT
      LAYER M5 ;
        RECT  8.688 0 8.712 0.192 ;
    END
  END d[31]
  PIN d[320]
    DIRECTION INPUT ;
    USE SIGNAL ;
    PORT
      LAYER M3 ;
        RECT  29.52 0 29.538 0.144 ;
    END
  END d[320]
  PIN d[321]
    DIRECTION INPUT ;
    USE SIGNAL ;
    PORT
      LAYER M5 ;
        RECT  29.568 0 29.592 0.192 ;
    END
  END d[321]
  PIN d[322]
    DIRECTION INPUT ;
    USE SIGNAL ;
    PORT
      LAYER M3 ;
        RECT  29.664 0 29.682 0.144 ;
    END
  END d[322]
  PIN d[323]
    DIRECTION INPUT ;
    USE SIGNAL ;
    PORT
      LAYER M5 ;
        RECT  29.712 0 29.736 0.192 ;
    END
  END d[323]
  PIN d[324]
    DIRECTION INPUT ;
    USE SIGNAL ;
    PORT
      LAYER M3 ;
        RECT  29.808 0 29.826 0.144 ;
    END
  END d[324]
  PIN d[325]
    DIRECTION INPUT ;
    USE SIGNAL ;
    PORT
      LAYER M5 ;
        RECT  29.856 0 29.88 0.192 ;
    END
  END d[325]
  PIN d[326]
    DIRECTION INPUT ;
    USE SIGNAL ;
    PORT
      LAYER M3 ;
        RECT  29.952 0 29.97 0.144 ;
    END
  END d[326]
  PIN d[327]
    DIRECTION INPUT ;
    USE SIGNAL ;
    PORT
      LAYER M5 ;
        RECT  30 0 30.024 0.192 ;
    END
  END d[327]
  PIN d[328]
    DIRECTION INPUT ;
    USE SIGNAL ;
    PORT
      LAYER M3 ;
        RECT  30.096 0 30.114 0.144 ;
    END
  END d[328]
  PIN d[329]
    DIRECTION INPUT ;
    USE SIGNAL ;
    PORT
      LAYER M5 ;
        RECT  30.144 0 30.168 0.192 ;
    END
  END d[329]
  PIN d[32]
    DIRECTION INPUT ;
    USE SIGNAL ;
    PORT
      LAYER M3 ;
        RECT  8.784 0 8.802 0.144 ;
    END
  END d[32]
  PIN d[330]
    DIRECTION INPUT ;
    USE SIGNAL ;
    PORT
      LAYER M3 ;
        RECT  30.24 0 30.258 0.144 ;
    END
  END d[330]
  PIN d[331]
    DIRECTION INPUT ;
    USE SIGNAL ;
    PORT
      LAYER M5 ;
        RECT  30.288 0 30.312 0.192 ;
    END
  END d[331]
  PIN d[332]
    DIRECTION INPUT ;
    USE SIGNAL ;
    PORT
      LAYER M3 ;
        RECT  30.384 0 30.402 0.144 ;
    END
  END d[332]
  PIN d[333]
    DIRECTION INPUT ;
    USE SIGNAL ;
    PORT
      LAYER M5 ;
        RECT  30.432 0 30.456 0.192 ;
    END
  END d[333]
  PIN d[334]
    DIRECTION INPUT ;
    USE SIGNAL ;
    PORT
      LAYER M3 ;
        RECT  30.528 0 30.546 0.144 ;
    END
  END d[334]
  PIN d[335]
    DIRECTION INPUT ;
    USE SIGNAL ;
    PORT
      LAYER M5 ;
        RECT  30.576 0 30.6 0.192 ;
    END
  END d[335]
  PIN d[336]
    DIRECTION INPUT ;
    USE SIGNAL ;
    PORT
      LAYER M3 ;
        RECT  30.672 0 30.69 0.144 ;
    END
  END d[336]
  PIN d[337]
    DIRECTION INPUT ;
    USE SIGNAL ;
    PORT
      LAYER M5 ;
        RECT  30.72 0 30.744 0.192 ;
    END
  END d[337]
  PIN d[338]
    DIRECTION INPUT ;
    USE SIGNAL ;
    PORT
      LAYER M3 ;
        RECT  30.816 0 30.834 0.144 ;
    END
  END d[338]
  PIN d[339]
    DIRECTION INPUT ;
    USE SIGNAL ;
    PORT
      LAYER M5 ;
        RECT  30.864 0 30.888 0.192 ;
    END
  END d[339]
  PIN d[33]
    DIRECTION INPUT ;
    USE SIGNAL ;
    PORT
      LAYER M5 ;
        RECT  8.832 0 8.856 0.192 ;
    END
  END d[33]
  PIN d[340]
    DIRECTION INPUT ;
    USE SIGNAL ;
    PORT
      LAYER M3 ;
        RECT  30.96 0 30.978 0.144 ;
    END
  END d[340]
  PIN d[341]
    DIRECTION INPUT ;
    USE SIGNAL ;
    PORT
      LAYER M5 ;
        RECT  31.008 0 31.032 0.192 ;
    END
  END d[341]
  PIN d[342]
    DIRECTION INPUT ;
    USE SIGNAL ;
    PORT
      LAYER M3 ;
        RECT  31.104 0 31.122 0.144 ;
    END
  END d[342]
  PIN d[343]
    DIRECTION INPUT ;
    USE SIGNAL ;
    PORT
      LAYER M5 ;
        RECT  31.152 0 31.176 0.192 ;
    END
  END d[343]
  PIN d[344]
    DIRECTION INPUT ;
    USE SIGNAL ;
    PORT
      LAYER M3 ;
        RECT  31.248 0 31.266 0.144 ;
    END
  END d[344]
  PIN d[345]
    DIRECTION INPUT ;
    USE SIGNAL ;
    PORT
      LAYER M5 ;
        RECT  31.296 0 31.32 0.192 ;
    END
  END d[345]
  PIN d[346]
    DIRECTION INPUT ;
    USE SIGNAL ;
    PORT
      LAYER M3 ;
        RECT  31.392 0 31.41 0.144 ;
    END
  END d[346]
  PIN d[347]
    DIRECTION INPUT ;
    USE SIGNAL ;
    PORT
      LAYER M5 ;
        RECT  31.44 0 31.464 0.192 ;
    END
  END d[347]
  PIN d[348]
    DIRECTION INPUT ;
    USE SIGNAL ;
    PORT
      LAYER M3 ;
        RECT  31.536 0 31.554 0.144 ;
    END
  END d[348]
  PIN d[349]
    DIRECTION INPUT ;
    USE SIGNAL ;
    PORT
      LAYER M5 ;
        RECT  31.584 0 31.608 0.192 ;
    END
  END d[349]
  PIN d[34]
    DIRECTION INPUT ;
    USE SIGNAL ;
    PORT
      LAYER M3 ;
        RECT  8.928 0 8.946 0.144 ;
    END
  END d[34]
  PIN d[350]
    DIRECTION INPUT ;
    USE SIGNAL ;
    PORT
      LAYER M3 ;
        RECT  31.68 0 31.698 0.144 ;
    END
  END d[350]
  PIN d[351]
    DIRECTION INPUT ;
    USE SIGNAL ;
    PORT
      LAYER M5 ;
        RECT  31.728 0 31.752 0.192 ;
    END
  END d[351]
  PIN d[352]
    DIRECTION INPUT ;
    USE SIGNAL ;
    PORT
      LAYER M3 ;
        RECT  31.824 0 31.842 0.144 ;
    END
  END d[352]
  PIN d[353]
    DIRECTION INPUT ;
    USE SIGNAL ;
    PORT
      LAYER M5 ;
        RECT  31.872 0 31.896 0.192 ;
    END
  END d[353]
  PIN d[354]
    DIRECTION INPUT ;
    USE SIGNAL ;
    PORT
      LAYER M3 ;
        RECT  31.968 0 31.986 0.144 ;
    END
  END d[354]
  PIN d[355]
    DIRECTION INPUT ;
    USE SIGNAL ;
    PORT
      LAYER M5 ;
        RECT  32.016 0 32.04 0.192 ;
    END
  END d[355]
  PIN d[356]
    DIRECTION INPUT ;
    USE SIGNAL ;
    PORT
      LAYER M3 ;
        RECT  32.112 0 32.13 0.144 ;
    END
  END d[356]
  PIN d[357]
    DIRECTION INPUT ;
    USE SIGNAL ;
    PORT
      LAYER M5 ;
        RECT  32.16 0 32.184 0.192 ;
    END
  END d[357]
  PIN d[358]
    DIRECTION INPUT ;
    USE SIGNAL ;
    PORT
      LAYER M3 ;
        RECT  32.256 0 32.274 0.144 ;
    END
  END d[358]
  PIN d[359]
    DIRECTION INPUT ;
    USE SIGNAL ;
    PORT
      LAYER M5 ;
        RECT  32.304 0 32.328 0.192 ;
    END
  END d[359]
  PIN d[35]
    DIRECTION INPUT ;
    USE SIGNAL ;
    PORT
      LAYER M5 ;
        RECT  8.976 0 9 0.192 ;
    END
  END d[35]
  PIN d[360]
    DIRECTION INPUT ;
    USE SIGNAL ;
    PORT
      LAYER M3 ;
        RECT  32.4 0 32.418 0.144 ;
    END
  END d[360]
  PIN d[361]
    DIRECTION INPUT ;
    USE SIGNAL ;
    PORT
      LAYER M5 ;
        RECT  32.448 0 32.472 0.192 ;
    END
  END d[361]
  PIN d[362]
    DIRECTION INPUT ;
    USE SIGNAL ;
    PORT
      LAYER M3 ;
        RECT  32.544 0 32.562 0.144 ;
    END
  END d[362]
  PIN d[363]
    DIRECTION INPUT ;
    USE SIGNAL ;
    PORT
      LAYER M5 ;
        RECT  32.592 0 32.616 0.192 ;
    END
  END d[363]
  PIN d[364]
    DIRECTION INPUT ;
    USE SIGNAL ;
    PORT
      LAYER M3 ;
        RECT  32.688 0 32.706 0.144 ;
    END
  END d[364]
  PIN d[365]
    DIRECTION INPUT ;
    USE SIGNAL ;
    PORT
      LAYER M5 ;
        RECT  32.736 0 32.76 0.192 ;
    END
  END d[365]
  PIN d[366]
    DIRECTION INPUT ;
    USE SIGNAL ;
    PORT
      LAYER M3 ;
        RECT  32.832 0 32.85 0.144 ;
    END
  END d[366]
  PIN d[367]
    DIRECTION INPUT ;
    USE SIGNAL ;
    PORT
      LAYER M5 ;
        RECT  32.88 0 32.904 0.192 ;
    END
  END d[367]
  PIN d[368]
    DIRECTION INPUT ;
    USE SIGNAL ;
    PORT
      LAYER M3 ;
        RECT  32.976 0 32.994 0.144 ;
    END
  END d[368]
  PIN d[369]
    DIRECTION INPUT ;
    USE SIGNAL ;
    PORT
      LAYER M5 ;
        RECT  33.024 0 33.048 0.192 ;
    END
  END d[369]
  PIN d[36]
    DIRECTION INPUT ;
    USE SIGNAL ;
    PORT
      LAYER M3 ;
        RECT  9.072 0 9.09 0.144 ;
    END
  END d[36]
  PIN d[370]
    DIRECTION INPUT ;
    USE SIGNAL ;
    PORT
      LAYER M3 ;
        RECT  33.12 0 33.138 0.144 ;
    END
  END d[370]
  PIN d[371]
    DIRECTION INPUT ;
    USE SIGNAL ;
    PORT
      LAYER M5 ;
        RECT  33.168 0 33.192 0.192 ;
    END
  END d[371]
  PIN d[372]
    DIRECTION INPUT ;
    USE SIGNAL ;
    PORT
      LAYER M3 ;
        RECT  33.264 0 33.282 0.144 ;
    END
  END d[372]
  PIN d[373]
    DIRECTION INPUT ;
    USE SIGNAL ;
    PORT
      LAYER M5 ;
        RECT  33.312 0 33.336 0.192 ;
    END
  END d[373]
  PIN d[374]
    DIRECTION INPUT ;
    USE SIGNAL ;
    PORT
      LAYER M3 ;
        RECT  33.408 0 33.426 0.144 ;
    END
  END d[374]
  PIN d[375]
    DIRECTION INPUT ;
    USE SIGNAL ;
    PORT
      LAYER M5 ;
        RECT  33.456 0 33.48 0.192 ;
    END
  END d[375]
  PIN d[376]
    DIRECTION INPUT ;
    USE SIGNAL ;
    PORT
      LAYER M3 ;
        RECT  33.552 0 33.57 0.144 ;
    END
  END d[376]
  PIN d[377]
    DIRECTION INPUT ;
    USE SIGNAL ;
    PORT
      LAYER M5 ;
        RECT  33.6 0 33.624 0.192 ;
    END
  END d[377]
  PIN d[378]
    DIRECTION INPUT ;
    USE SIGNAL ;
    PORT
      LAYER M3 ;
        RECT  33.696 0 33.714 0.144 ;
    END
  END d[378]
  PIN d[379]
    DIRECTION INPUT ;
    USE SIGNAL ;
    PORT
      LAYER M5 ;
        RECT  33.744 0 33.768 0.192 ;
    END
  END d[379]
  PIN d[37]
    DIRECTION INPUT ;
    USE SIGNAL ;
    PORT
      LAYER M5 ;
        RECT  9.12 0 9.144 0.192 ;
    END
  END d[37]
  PIN d[380]
    DIRECTION INPUT ;
    USE SIGNAL ;
    PORT
      LAYER M3 ;
        RECT  33.84 0 33.858 0.144 ;
    END
  END d[380]
  PIN d[381]
    DIRECTION INPUT ;
    USE SIGNAL ;
    PORT
      LAYER M5 ;
        RECT  33.888 0 33.912 0.192 ;
    END
  END d[381]
  PIN d[382]
    DIRECTION INPUT ;
    USE SIGNAL ;
    PORT
      LAYER M3 ;
        RECT  33.984 0 34.002 0.144 ;
    END
  END d[382]
  PIN d[383]
    DIRECTION INPUT ;
    USE SIGNAL ;
    PORT
      LAYER M5 ;
        RECT  34.032 0 34.056 0.192 ;
    END
  END d[383]
  PIN d[384]
    DIRECTION INPUT ;
    USE SIGNAL ;
    PORT
      LAYER M3 ;
        RECT  34.128 0 34.146 0.144 ;
    END
  END d[384]
  PIN d[385]
    DIRECTION INPUT ;
    USE SIGNAL ;
    PORT
      LAYER M5 ;
        RECT  34.176 0 34.2 0.192 ;
    END
  END d[385]
  PIN d[386]
    DIRECTION INPUT ;
    USE SIGNAL ;
    PORT
      LAYER M3 ;
        RECT  34.272 0 34.29 0.144 ;
    END
  END d[386]
  PIN d[387]
    DIRECTION INPUT ;
    USE SIGNAL ;
    PORT
      LAYER M5 ;
        RECT  34.32 0 34.344 0.192 ;
    END
  END d[387]
  PIN d[388]
    DIRECTION INPUT ;
    USE SIGNAL ;
    PORT
      LAYER M3 ;
        RECT  34.416 0 34.434 0.144 ;
    END
  END d[388]
  PIN d[389]
    DIRECTION INPUT ;
    USE SIGNAL ;
    PORT
      LAYER M5 ;
        RECT  34.464 0 34.488 0.192 ;
    END
  END d[389]
  PIN d[38]
    DIRECTION INPUT ;
    USE SIGNAL ;
    PORT
      LAYER M3 ;
        RECT  9.216 0 9.234 0.144 ;
    END
  END d[38]
  PIN d[390]
    DIRECTION INPUT ;
    USE SIGNAL ;
    PORT
      LAYER M3 ;
        RECT  34.56 0 34.578 0.144 ;
    END
  END d[390]
  PIN d[391]
    DIRECTION INPUT ;
    USE SIGNAL ;
    PORT
      LAYER M5 ;
        RECT  34.608 0 34.632 0.192 ;
    END
  END d[391]
  PIN d[392]
    DIRECTION INPUT ;
    USE SIGNAL ;
    PORT
      LAYER M3 ;
        RECT  34.704 0 34.722 0.144 ;
    END
  END d[392]
  PIN d[393]
    DIRECTION INPUT ;
    USE SIGNAL ;
    PORT
      LAYER M5 ;
        RECT  34.752 0 34.776 0.192 ;
    END
  END d[393]
  PIN d[394]
    DIRECTION INPUT ;
    USE SIGNAL ;
    PORT
      LAYER M3 ;
        RECT  34.848 0 34.866 0.144 ;
    END
  END d[394]
  PIN d[395]
    DIRECTION INPUT ;
    USE SIGNAL ;
    PORT
      LAYER M5 ;
        RECT  34.896 0 34.92 0.192 ;
    END
  END d[395]
  PIN d[396]
    DIRECTION INPUT ;
    USE SIGNAL ;
    PORT
      LAYER M3 ;
        RECT  34.992 0 35.01 0.144 ;
    END
  END d[396]
  PIN d[397]
    DIRECTION INPUT ;
    USE SIGNAL ;
    PORT
      LAYER M5 ;
        RECT  35.04 0 35.064 0.192 ;
    END
  END d[397]
  PIN d[398]
    DIRECTION INPUT ;
    USE SIGNAL ;
    PORT
      LAYER M3 ;
        RECT  35.136 0 35.154 0.144 ;
    END
  END d[398]
  PIN d[399]
    DIRECTION INPUT ;
    USE SIGNAL ;
    PORT
      LAYER M5 ;
        RECT  35.184 0 35.208 0.192 ;
    END
  END d[399]
  PIN d[39]
    DIRECTION INPUT ;
    USE SIGNAL ;
    PORT
      LAYER M5 ;
        RECT  9.264 0 9.288 0.192 ;
    END
  END d[39]
  PIN d[3]
    DIRECTION INPUT ;
    USE SIGNAL ;
    PORT
      LAYER M5 ;
        RECT  6.672 0 6.696 0.192 ;
    END
  END d[3]
  PIN d[400]
    DIRECTION INPUT ;
    USE SIGNAL ;
    PORT
      LAYER M3 ;
        RECT  35.28 0 35.298 0.144 ;
    END
  END d[400]
  PIN d[401]
    DIRECTION INPUT ;
    USE SIGNAL ;
    PORT
      LAYER M5 ;
        RECT  35.328 0 35.352 0.192 ;
    END
  END d[401]
  PIN d[402]
    DIRECTION INPUT ;
    USE SIGNAL ;
    PORT
      LAYER M3 ;
        RECT  35.424 0 35.442 0.144 ;
    END
  END d[402]
  PIN d[403]
    DIRECTION INPUT ;
    USE SIGNAL ;
    PORT
      LAYER M5 ;
        RECT  35.472 0 35.496 0.192 ;
    END
  END d[403]
  PIN d[404]
    DIRECTION INPUT ;
    USE SIGNAL ;
    PORT
      LAYER M3 ;
        RECT  35.568 0 35.586 0.144 ;
    END
  END d[404]
  PIN d[405]
    DIRECTION INPUT ;
    USE SIGNAL ;
    PORT
      LAYER M5 ;
        RECT  35.616 0 35.64 0.192 ;
    END
  END d[405]
  PIN d[406]
    DIRECTION INPUT ;
    USE SIGNAL ;
    PORT
      LAYER M3 ;
        RECT  35.712 0 35.73 0.144 ;
    END
  END d[406]
  PIN d[407]
    DIRECTION INPUT ;
    USE SIGNAL ;
    PORT
      LAYER M5 ;
        RECT  35.76 0 35.784 0.192 ;
    END
  END d[407]
  PIN d[408]
    DIRECTION INPUT ;
    USE SIGNAL ;
    PORT
      LAYER M3 ;
        RECT  35.856 0 35.874 0.144 ;
    END
  END d[408]
  PIN d[409]
    DIRECTION INPUT ;
    USE SIGNAL ;
    PORT
      LAYER M5 ;
        RECT  35.904 0 35.928 0.192 ;
    END
  END d[409]
  PIN d[40]
    DIRECTION INPUT ;
    USE SIGNAL ;
    PORT
      LAYER M3 ;
        RECT  9.36 0 9.378 0.144 ;
    END
  END d[40]
  PIN d[41]
    DIRECTION INPUT ;
    USE SIGNAL ;
    PORT
      LAYER M5 ;
        RECT  9.408 0 9.432 0.192 ;
    END
  END d[41]
  PIN d[42]
    DIRECTION INPUT ;
    USE SIGNAL ;
    PORT
      LAYER M3 ;
        RECT  9.504 0 9.522 0.144 ;
    END
  END d[42]
  PIN d[43]
    DIRECTION INPUT ;
    USE SIGNAL ;
    PORT
      LAYER M5 ;
        RECT  9.552 0 9.576 0.192 ;
    END
  END d[43]
  PIN d[44]
    DIRECTION INPUT ;
    USE SIGNAL ;
    PORT
      LAYER M3 ;
        RECT  9.648 0 9.666 0.144 ;
    END
  END d[44]
  PIN d[45]
    DIRECTION INPUT ;
    USE SIGNAL ;
    PORT
      LAYER M5 ;
        RECT  9.696 0 9.72 0.192 ;
    END
  END d[45]
  PIN d[46]
    DIRECTION INPUT ;
    USE SIGNAL ;
    PORT
      LAYER M3 ;
        RECT  9.792 0 9.81 0.144 ;
    END
  END d[46]
  PIN d[47]
    DIRECTION INPUT ;
    USE SIGNAL ;
    PORT
      LAYER M5 ;
        RECT  9.84 0 9.864 0.192 ;
    END
  END d[47]
  PIN d[48]
    DIRECTION INPUT ;
    USE SIGNAL ;
    PORT
      LAYER M3 ;
        RECT  9.936 0 9.954 0.144 ;
    END
  END d[48]
  PIN d[49]
    DIRECTION INPUT ;
    USE SIGNAL ;
    PORT
      LAYER M5 ;
        RECT  9.984 0 10.008 0.192 ;
    END
  END d[49]
  PIN d[4]
    DIRECTION INPUT ;
    USE SIGNAL ;
    PORT
      LAYER M3 ;
        RECT  6.768 0 6.786 0.144 ;
    END
  END d[4]
  PIN d[50]
    DIRECTION INPUT ;
    USE SIGNAL ;
    PORT
      LAYER M3 ;
        RECT  10.08 0 10.098 0.144 ;
    END
  END d[50]
  PIN d[51]
    DIRECTION INPUT ;
    USE SIGNAL ;
    PORT
      LAYER M5 ;
        RECT  10.128 0 10.152 0.192 ;
    END
  END d[51]
  PIN d[52]
    DIRECTION INPUT ;
    USE SIGNAL ;
    PORT
      LAYER M3 ;
        RECT  10.224 0 10.242 0.144 ;
    END
  END d[52]
  PIN d[53]
    DIRECTION INPUT ;
    USE SIGNAL ;
    PORT
      LAYER M5 ;
        RECT  10.272 0 10.296 0.192 ;
    END
  END d[53]
  PIN d[54]
    DIRECTION INPUT ;
    USE SIGNAL ;
    PORT
      LAYER M3 ;
        RECT  10.368 0 10.386 0.144 ;
    END
  END d[54]
  PIN d[55]
    DIRECTION INPUT ;
    USE SIGNAL ;
    PORT
      LAYER M5 ;
        RECT  10.416 0 10.44 0.192 ;
    END
  END d[55]
  PIN d[56]
    DIRECTION INPUT ;
    USE SIGNAL ;
    PORT
      LAYER M3 ;
        RECT  10.512 0 10.53 0.144 ;
    END
  END d[56]
  PIN d[57]
    DIRECTION INPUT ;
    USE SIGNAL ;
    PORT
      LAYER M5 ;
        RECT  10.56 0 10.584 0.192 ;
    END
  END d[57]
  PIN d[58]
    DIRECTION INPUT ;
    USE SIGNAL ;
    PORT
      LAYER M3 ;
        RECT  10.656 0 10.674 0.144 ;
    END
  END d[58]
  PIN d[59]
    DIRECTION INPUT ;
    USE SIGNAL ;
    PORT
      LAYER M5 ;
        RECT  10.704 0 10.728 0.192 ;
    END
  END d[59]
  PIN d[5]
    DIRECTION INPUT ;
    USE SIGNAL ;
    PORT
      LAYER M5 ;
        RECT  6.816 0 6.84 0.192 ;
    END
  END d[5]
  PIN d[60]
    DIRECTION INPUT ;
    USE SIGNAL ;
    PORT
      LAYER M3 ;
        RECT  10.8 0 10.818 0.144 ;
    END
  END d[60]
  PIN d[61]
    DIRECTION INPUT ;
    USE SIGNAL ;
    PORT
      LAYER M5 ;
        RECT  10.848 0 10.872 0.192 ;
    END
  END d[61]
  PIN d[62]
    DIRECTION INPUT ;
    USE SIGNAL ;
    PORT
      LAYER M3 ;
        RECT  10.944 0 10.962 0.144 ;
    END
  END d[62]
  PIN d[63]
    DIRECTION INPUT ;
    USE SIGNAL ;
    PORT
      LAYER M5 ;
        RECT  10.992 0 11.016 0.192 ;
    END
  END d[63]
  PIN d[64]
    DIRECTION INPUT ;
    USE SIGNAL ;
    PORT
      LAYER M3 ;
        RECT  11.088 0 11.106 0.144 ;
    END
  END d[64]
  PIN d[65]
    DIRECTION INPUT ;
    USE SIGNAL ;
    PORT
      LAYER M5 ;
        RECT  11.136 0 11.16 0.192 ;
    END
  END d[65]
  PIN d[66]
    DIRECTION INPUT ;
    USE SIGNAL ;
    PORT
      LAYER M3 ;
        RECT  11.232 0 11.25 0.144 ;
    END
  END d[66]
  PIN d[67]
    DIRECTION INPUT ;
    USE SIGNAL ;
    PORT
      LAYER M5 ;
        RECT  11.28 0 11.304 0.192 ;
    END
  END d[67]
  PIN d[68]
    DIRECTION INPUT ;
    USE SIGNAL ;
    PORT
      LAYER M3 ;
        RECT  11.376 0 11.394 0.144 ;
    END
  END d[68]
  PIN d[69]
    DIRECTION INPUT ;
    USE SIGNAL ;
    PORT
      LAYER M5 ;
        RECT  11.424 0 11.448 0.192 ;
    END
  END d[69]
  PIN d[6]
    DIRECTION INPUT ;
    USE SIGNAL ;
    PORT
      LAYER M3 ;
        RECT  6.912 0 6.93 0.144 ;
    END
  END d[6]
  PIN d[70]
    DIRECTION INPUT ;
    USE SIGNAL ;
    PORT
      LAYER M3 ;
        RECT  11.52 0 11.538 0.144 ;
    END
  END d[70]
  PIN d[71]
    DIRECTION INPUT ;
    USE SIGNAL ;
    PORT
      LAYER M5 ;
        RECT  11.568 0 11.592 0.192 ;
    END
  END d[71]
  PIN d[72]
    DIRECTION INPUT ;
    USE SIGNAL ;
    PORT
      LAYER M3 ;
        RECT  11.664 0 11.682 0.144 ;
    END
  END d[72]
  PIN d[73]
    DIRECTION INPUT ;
    USE SIGNAL ;
    PORT
      LAYER M5 ;
        RECT  11.712 0 11.736 0.192 ;
    END
  END d[73]
  PIN d[74]
    DIRECTION INPUT ;
    USE SIGNAL ;
    PORT
      LAYER M3 ;
        RECT  11.808 0 11.826 0.144 ;
    END
  END d[74]
  PIN d[75]
    DIRECTION INPUT ;
    USE SIGNAL ;
    PORT
      LAYER M5 ;
        RECT  11.856 0 11.88 0.192 ;
    END
  END d[75]
  PIN d[76]
    DIRECTION INPUT ;
    USE SIGNAL ;
    PORT
      LAYER M3 ;
        RECT  11.952 0 11.97 0.144 ;
    END
  END d[76]
  PIN d[77]
    DIRECTION INPUT ;
    USE SIGNAL ;
    PORT
      LAYER M5 ;
        RECT  12 0 12.024 0.192 ;
    END
  END d[77]
  PIN d[78]
    DIRECTION INPUT ;
    USE SIGNAL ;
    PORT
      LAYER M3 ;
        RECT  12.096 0 12.114 0.144 ;
    END
  END d[78]
  PIN d[79]
    DIRECTION INPUT ;
    USE SIGNAL ;
    PORT
      LAYER M5 ;
        RECT  12.144 0 12.168 0.192 ;
    END
  END d[79]
  PIN d[7]
    DIRECTION INPUT ;
    USE SIGNAL ;
    PORT
      LAYER M5 ;
        RECT  6.96 0 6.984 0.192 ;
    END
  END d[7]
  PIN d[80]
    DIRECTION INPUT ;
    USE SIGNAL ;
    PORT
      LAYER M3 ;
        RECT  12.24 0 12.258 0.144 ;
    END
  END d[80]
  PIN d[81]
    DIRECTION INPUT ;
    USE SIGNAL ;
    PORT
      LAYER M5 ;
        RECT  12.288 0 12.312 0.192 ;
    END
  END d[81]
  PIN d[82]
    DIRECTION INPUT ;
    USE SIGNAL ;
    PORT
      LAYER M3 ;
        RECT  12.384 0 12.402 0.144 ;
    END
  END d[82]
  PIN d[83]
    DIRECTION INPUT ;
    USE SIGNAL ;
    PORT
      LAYER M5 ;
        RECT  12.432 0 12.456 0.192 ;
    END
  END d[83]
  PIN d[84]
    DIRECTION INPUT ;
    USE SIGNAL ;
    PORT
      LAYER M3 ;
        RECT  12.528 0 12.546 0.144 ;
    END
  END d[84]
  PIN d[85]
    DIRECTION INPUT ;
    USE SIGNAL ;
    PORT
      LAYER M5 ;
        RECT  12.576 0 12.6 0.192 ;
    END
  END d[85]
  PIN d[86]
    DIRECTION INPUT ;
    USE SIGNAL ;
    PORT
      LAYER M3 ;
        RECT  12.672 0 12.69 0.144 ;
    END
  END d[86]
  PIN d[87]
    DIRECTION INPUT ;
    USE SIGNAL ;
    PORT
      LAYER M5 ;
        RECT  12.72 0 12.744 0.192 ;
    END
  END d[87]
  PIN d[88]
    DIRECTION INPUT ;
    USE SIGNAL ;
    PORT
      LAYER M3 ;
        RECT  12.816 0 12.834 0.144 ;
    END
  END d[88]
  PIN d[89]
    DIRECTION INPUT ;
    USE SIGNAL ;
    PORT
      LAYER M5 ;
        RECT  12.864 0 12.888 0.192 ;
    END
  END d[89]
  PIN d[8]
    DIRECTION INPUT ;
    USE SIGNAL ;
    PORT
      LAYER M3 ;
        RECT  7.056 0 7.074 0.144 ;
    END
  END d[8]
  PIN d[90]
    DIRECTION INPUT ;
    USE SIGNAL ;
    PORT
      LAYER M3 ;
        RECT  12.96 0 12.978 0.144 ;
    END
  END d[90]
  PIN d[91]
    DIRECTION INPUT ;
    USE SIGNAL ;
    PORT
      LAYER M5 ;
        RECT  13.008 0 13.032 0.192 ;
    END
  END d[91]
  PIN d[92]
    DIRECTION INPUT ;
    USE SIGNAL ;
    PORT
      LAYER M3 ;
        RECT  13.104 0 13.122 0.144 ;
    END
  END d[92]
  PIN d[93]
    DIRECTION INPUT ;
    USE SIGNAL ;
    PORT
      LAYER M5 ;
        RECT  13.152 0 13.176 0.192 ;
    END
  END d[93]
  PIN d[94]
    DIRECTION INPUT ;
    USE SIGNAL ;
    PORT
      LAYER M3 ;
        RECT  13.248 0 13.266 0.144 ;
    END
  END d[94]
  PIN d[95]
    DIRECTION INPUT ;
    USE SIGNAL ;
    PORT
      LAYER M5 ;
        RECT  13.296 0 13.32 0.192 ;
    END
  END d[95]
  PIN d[96]
    DIRECTION INPUT ;
    USE SIGNAL ;
    PORT
      LAYER M3 ;
        RECT  13.392 0 13.41 0.144 ;
    END
  END d[96]
  PIN d[97]
    DIRECTION INPUT ;
    USE SIGNAL ;
    PORT
      LAYER M5 ;
        RECT  13.44 0 13.464 0.192 ;
    END
  END d[97]
  PIN d[98]
    DIRECTION INPUT ;
    USE SIGNAL ;
    PORT
      LAYER M3 ;
        RECT  13.536 0 13.554 0.144 ;
    END
  END d[98]
  PIN d[99]
    DIRECTION INPUT ;
    USE SIGNAL ;
    PORT
      LAYER M5 ;
        RECT  13.584 0 13.608 0.192 ;
    END
  END d[99]
  PIN d[9]
    DIRECTION INPUT ;
    USE SIGNAL ;
    PORT
      LAYER M5 ;
        RECT  7.104 0 7.128 0.192 ;
    END
  END d[9]
  PIN q[0]
    DIRECTION OUTPUT ;
    USE SIGNAL ;
    PORT
      LAYER M3 ;
        RECT  6.48 34.416 6.498 34.56 ;
    END
  END q[0]
  PIN q[100]
    DIRECTION OUTPUT ;
    USE SIGNAL ;
    PORT
      LAYER M3 ;
        RECT  13.68 34.416 13.698 34.56 ;
    END
  END q[100]
  PIN q[101]
    DIRECTION OUTPUT ;
    USE SIGNAL ;
    PORT
      LAYER M5 ;
        RECT  13.728 34.368 13.752 34.56 ;
    END
  END q[101]
  PIN q[102]
    DIRECTION OUTPUT ;
    USE SIGNAL ;
    PORT
      LAYER M3 ;
        RECT  13.824 34.416 13.842 34.56 ;
    END
  END q[102]
  PIN q[103]
    DIRECTION OUTPUT ;
    USE SIGNAL ;
    PORT
      LAYER M5 ;
        RECT  13.872 34.368 13.896 34.56 ;
    END
  END q[103]
  PIN q[104]
    DIRECTION OUTPUT ;
    USE SIGNAL ;
    PORT
      LAYER M3 ;
        RECT  13.968 34.416 13.986 34.56 ;
    END
  END q[104]
  PIN q[105]
    DIRECTION OUTPUT ;
    USE SIGNAL ;
    PORT
      LAYER M5 ;
        RECT  14.016 34.368 14.04 34.56 ;
    END
  END q[105]
  PIN q[106]
    DIRECTION OUTPUT ;
    USE SIGNAL ;
    PORT
      LAYER M3 ;
        RECT  14.112 34.416 14.13 34.56 ;
    END
  END q[106]
  PIN q[107]
    DIRECTION OUTPUT ;
    USE SIGNAL ;
    PORT
      LAYER M5 ;
        RECT  14.16 34.368 14.184 34.56 ;
    END
  END q[107]
  PIN q[108]
    DIRECTION OUTPUT ;
    USE SIGNAL ;
    PORT
      LAYER M3 ;
        RECT  14.256 34.416 14.274 34.56 ;
    END
  END q[108]
  PIN q[109]
    DIRECTION OUTPUT ;
    USE SIGNAL ;
    PORT
      LAYER M5 ;
        RECT  14.304 34.368 14.328 34.56 ;
    END
  END q[109]
  PIN q[10]
    DIRECTION OUTPUT ;
    USE SIGNAL ;
    PORT
      LAYER M3 ;
        RECT  7.2 34.416 7.218 34.56 ;
    END
  END q[10]
  PIN q[110]
    DIRECTION OUTPUT ;
    USE SIGNAL ;
    PORT
      LAYER M3 ;
        RECT  14.4 34.416 14.418 34.56 ;
    END
  END q[110]
  PIN q[111]
    DIRECTION OUTPUT ;
    USE SIGNAL ;
    PORT
      LAYER M5 ;
        RECT  14.448 34.368 14.472 34.56 ;
    END
  END q[111]
  PIN q[112]
    DIRECTION OUTPUT ;
    USE SIGNAL ;
    PORT
      LAYER M3 ;
        RECT  14.544 34.416 14.562 34.56 ;
    END
  END q[112]
  PIN q[113]
    DIRECTION OUTPUT ;
    USE SIGNAL ;
    PORT
      LAYER M5 ;
        RECT  14.592 34.368 14.616 34.56 ;
    END
  END q[113]
  PIN q[114]
    DIRECTION OUTPUT ;
    USE SIGNAL ;
    PORT
      LAYER M3 ;
        RECT  14.688 34.416 14.706 34.56 ;
    END
  END q[114]
  PIN q[115]
    DIRECTION OUTPUT ;
    USE SIGNAL ;
    PORT
      LAYER M5 ;
        RECT  14.736 34.368 14.76 34.56 ;
    END
  END q[115]
  PIN q[116]
    DIRECTION OUTPUT ;
    USE SIGNAL ;
    PORT
      LAYER M3 ;
        RECT  14.832 34.416 14.85 34.56 ;
    END
  END q[116]
  PIN q[117]
    DIRECTION OUTPUT ;
    USE SIGNAL ;
    PORT
      LAYER M5 ;
        RECT  14.88 34.368 14.904 34.56 ;
    END
  END q[117]
  PIN q[118]
    DIRECTION OUTPUT ;
    USE SIGNAL ;
    PORT
      LAYER M3 ;
        RECT  14.976 34.416 14.994 34.56 ;
    END
  END q[118]
  PIN q[119]
    DIRECTION OUTPUT ;
    USE SIGNAL ;
    PORT
      LAYER M5 ;
        RECT  15.024 34.368 15.048 34.56 ;
    END
  END q[119]
  PIN q[11]
    DIRECTION OUTPUT ;
    USE SIGNAL ;
    PORT
      LAYER M5 ;
        RECT  7.248 34.368 7.272 34.56 ;
    END
  END q[11]
  PIN q[120]
    DIRECTION OUTPUT ;
    USE SIGNAL ;
    PORT
      LAYER M3 ;
        RECT  15.12 34.416 15.138 34.56 ;
    END
  END q[120]
  PIN q[121]
    DIRECTION OUTPUT ;
    USE SIGNAL ;
    PORT
      LAYER M5 ;
        RECT  15.168 34.368 15.192 34.56 ;
    END
  END q[121]
  PIN q[122]
    DIRECTION OUTPUT ;
    USE SIGNAL ;
    PORT
      LAYER M3 ;
        RECT  15.264 34.416 15.282 34.56 ;
    END
  END q[122]
  PIN q[123]
    DIRECTION OUTPUT ;
    USE SIGNAL ;
    PORT
      LAYER M5 ;
        RECT  15.312 34.368 15.336 34.56 ;
    END
  END q[123]
  PIN q[124]
    DIRECTION OUTPUT ;
    USE SIGNAL ;
    PORT
      LAYER M3 ;
        RECT  15.408 34.416 15.426 34.56 ;
    END
  END q[124]
  PIN q[125]
    DIRECTION OUTPUT ;
    USE SIGNAL ;
    PORT
      LAYER M5 ;
        RECT  15.456 34.368 15.48 34.56 ;
    END
  END q[125]
  PIN q[126]
    DIRECTION OUTPUT ;
    USE SIGNAL ;
    PORT
      LAYER M3 ;
        RECT  15.552 34.416 15.57 34.56 ;
    END
  END q[126]
  PIN q[127]
    DIRECTION OUTPUT ;
    USE SIGNAL ;
    PORT
      LAYER M5 ;
        RECT  15.6 34.368 15.624 34.56 ;
    END
  END q[127]
  PIN q[128]
    DIRECTION OUTPUT ;
    USE SIGNAL ;
    PORT
      LAYER M3 ;
        RECT  15.696 34.416 15.714 34.56 ;
    END
  END q[128]
  PIN q[129]
    DIRECTION OUTPUT ;
    USE SIGNAL ;
    PORT
      LAYER M5 ;
        RECT  15.744 34.368 15.768 34.56 ;
    END
  END q[129]
  PIN q[12]
    DIRECTION OUTPUT ;
    USE SIGNAL ;
    PORT
      LAYER M3 ;
        RECT  7.344 34.416 7.362 34.56 ;
    END
  END q[12]
  PIN q[130]
    DIRECTION OUTPUT ;
    USE SIGNAL ;
    PORT
      LAYER M3 ;
        RECT  15.84 34.416 15.858 34.56 ;
    END
  END q[130]
  PIN q[131]
    DIRECTION OUTPUT ;
    USE SIGNAL ;
    PORT
      LAYER M5 ;
        RECT  15.888 34.368 15.912 34.56 ;
    END
  END q[131]
  PIN q[132]
    DIRECTION OUTPUT ;
    USE SIGNAL ;
    PORT
      LAYER M3 ;
        RECT  15.984 34.416 16.002 34.56 ;
    END
  END q[132]
  PIN q[133]
    DIRECTION OUTPUT ;
    USE SIGNAL ;
    PORT
      LAYER M5 ;
        RECT  16.032 34.368 16.056 34.56 ;
    END
  END q[133]
  PIN q[134]
    DIRECTION OUTPUT ;
    USE SIGNAL ;
    PORT
      LAYER M3 ;
        RECT  16.128 34.416 16.146 34.56 ;
    END
  END q[134]
  PIN q[135]
    DIRECTION OUTPUT ;
    USE SIGNAL ;
    PORT
      LAYER M5 ;
        RECT  16.176 34.368 16.2 34.56 ;
    END
  END q[135]
  PIN q[136]
    DIRECTION OUTPUT ;
    USE SIGNAL ;
    PORT
      LAYER M3 ;
        RECT  16.272 34.416 16.29 34.56 ;
    END
  END q[136]
  PIN q[137]
    DIRECTION OUTPUT ;
    USE SIGNAL ;
    PORT
      LAYER M5 ;
        RECT  16.32 34.368 16.344 34.56 ;
    END
  END q[137]
  PIN q[138]
    DIRECTION OUTPUT ;
    USE SIGNAL ;
    PORT
      LAYER M3 ;
        RECT  16.416 34.416 16.434 34.56 ;
    END
  END q[138]
  PIN q[139]
    DIRECTION OUTPUT ;
    USE SIGNAL ;
    PORT
      LAYER M5 ;
        RECT  16.464 34.368 16.488 34.56 ;
    END
  END q[139]
  PIN q[13]
    DIRECTION OUTPUT ;
    USE SIGNAL ;
    PORT
      LAYER M5 ;
        RECT  7.392 34.368 7.416 34.56 ;
    END
  END q[13]
  PIN q[140]
    DIRECTION OUTPUT ;
    USE SIGNAL ;
    PORT
      LAYER M3 ;
        RECT  16.56 34.416 16.578 34.56 ;
    END
  END q[140]
  PIN q[141]
    DIRECTION OUTPUT ;
    USE SIGNAL ;
    PORT
      LAYER M5 ;
        RECT  16.608 34.368 16.632 34.56 ;
    END
  END q[141]
  PIN q[142]
    DIRECTION OUTPUT ;
    USE SIGNAL ;
    PORT
      LAYER M3 ;
        RECT  16.704 34.416 16.722 34.56 ;
    END
  END q[142]
  PIN q[143]
    DIRECTION OUTPUT ;
    USE SIGNAL ;
    PORT
      LAYER M5 ;
        RECT  16.752 34.368 16.776 34.56 ;
    END
  END q[143]
  PIN q[144]
    DIRECTION OUTPUT ;
    USE SIGNAL ;
    PORT
      LAYER M3 ;
        RECT  16.848 34.416 16.866 34.56 ;
    END
  END q[144]
  PIN q[145]
    DIRECTION OUTPUT ;
    USE SIGNAL ;
    PORT
      LAYER M5 ;
        RECT  16.896 34.368 16.92 34.56 ;
    END
  END q[145]
  PIN q[146]
    DIRECTION OUTPUT ;
    USE SIGNAL ;
    PORT
      LAYER M3 ;
        RECT  16.992 34.416 17.01 34.56 ;
    END
  END q[146]
  PIN q[147]
    DIRECTION OUTPUT ;
    USE SIGNAL ;
    PORT
      LAYER M5 ;
        RECT  17.04 34.368 17.064 34.56 ;
    END
  END q[147]
  PIN q[148]
    DIRECTION OUTPUT ;
    USE SIGNAL ;
    PORT
      LAYER M3 ;
        RECT  17.136 34.416 17.154 34.56 ;
    END
  END q[148]
  PIN q[149]
    DIRECTION OUTPUT ;
    USE SIGNAL ;
    PORT
      LAYER M5 ;
        RECT  17.184 34.368 17.208 34.56 ;
    END
  END q[149]
  PIN q[14]
    DIRECTION OUTPUT ;
    USE SIGNAL ;
    PORT
      LAYER M3 ;
        RECT  7.488 34.416 7.506 34.56 ;
    END
  END q[14]
  PIN q[150]
    DIRECTION OUTPUT ;
    USE SIGNAL ;
    PORT
      LAYER M3 ;
        RECT  17.28 34.416 17.298 34.56 ;
    END
  END q[150]
  PIN q[151]
    DIRECTION OUTPUT ;
    USE SIGNAL ;
    PORT
      LAYER M5 ;
        RECT  17.328 34.368 17.352 34.56 ;
    END
  END q[151]
  PIN q[152]
    DIRECTION OUTPUT ;
    USE SIGNAL ;
    PORT
      LAYER M3 ;
        RECT  17.424 34.416 17.442 34.56 ;
    END
  END q[152]
  PIN q[153]
    DIRECTION OUTPUT ;
    USE SIGNAL ;
    PORT
      LAYER M5 ;
        RECT  17.472 34.368 17.496 34.56 ;
    END
  END q[153]
  PIN q[154]
    DIRECTION OUTPUT ;
    USE SIGNAL ;
    PORT
      LAYER M3 ;
        RECT  17.568 34.416 17.586 34.56 ;
    END
  END q[154]
  PIN q[155]
    DIRECTION OUTPUT ;
    USE SIGNAL ;
    PORT
      LAYER M5 ;
        RECT  17.616 34.368 17.64 34.56 ;
    END
  END q[155]
  PIN q[156]
    DIRECTION OUTPUT ;
    USE SIGNAL ;
    PORT
      LAYER M3 ;
        RECT  17.712 34.416 17.73 34.56 ;
    END
  END q[156]
  PIN q[157]
    DIRECTION OUTPUT ;
    USE SIGNAL ;
    PORT
      LAYER M5 ;
        RECT  17.76 34.368 17.784 34.56 ;
    END
  END q[157]
  PIN q[158]
    DIRECTION OUTPUT ;
    USE SIGNAL ;
    PORT
      LAYER M3 ;
        RECT  17.856 34.416 17.874 34.56 ;
    END
  END q[158]
  PIN q[159]
    DIRECTION OUTPUT ;
    USE SIGNAL ;
    PORT
      LAYER M5 ;
        RECT  17.904 34.368 17.928 34.56 ;
    END
  END q[159]
  PIN q[15]
    DIRECTION OUTPUT ;
    USE SIGNAL ;
    PORT
      LAYER M5 ;
        RECT  7.536 34.368 7.56 34.56 ;
    END
  END q[15]
  PIN q[160]
    DIRECTION OUTPUT ;
    USE SIGNAL ;
    PORT
      LAYER M3 ;
        RECT  18 34.416 18.018 34.56 ;
    END
  END q[160]
  PIN q[161]
    DIRECTION OUTPUT ;
    USE SIGNAL ;
    PORT
      LAYER M5 ;
        RECT  18.048 34.368 18.072 34.56 ;
    END
  END q[161]
  PIN q[162]
    DIRECTION OUTPUT ;
    USE SIGNAL ;
    PORT
      LAYER M3 ;
        RECT  18.144 34.416 18.162 34.56 ;
    END
  END q[162]
  PIN q[163]
    DIRECTION OUTPUT ;
    USE SIGNAL ;
    PORT
      LAYER M5 ;
        RECT  18.192 34.368 18.216 34.56 ;
    END
  END q[163]
  PIN q[164]
    DIRECTION OUTPUT ;
    USE SIGNAL ;
    PORT
      LAYER M3 ;
        RECT  18.288 34.416 18.306 34.56 ;
    END
  END q[164]
  PIN q[165]
    DIRECTION OUTPUT ;
    USE SIGNAL ;
    PORT
      LAYER M5 ;
        RECT  18.336 34.368 18.36 34.56 ;
    END
  END q[165]
  PIN q[166]
    DIRECTION OUTPUT ;
    USE SIGNAL ;
    PORT
      LAYER M3 ;
        RECT  18.432 34.416 18.45 34.56 ;
    END
  END q[166]
  PIN q[167]
    DIRECTION OUTPUT ;
    USE SIGNAL ;
    PORT
      LAYER M5 ;
        RECT  18.48 34.368 18.504 34.56 ;
    END
  END q[167]
  PIN q[168]
    DIRECTION OUTPUT ;
    USE SIGNAL ;
    PORT
      LAYER M3 ;
        RECT  18.576 34.416 18.594 34.56 ;
    END
  END q[168]
  PIN q[169]
    DIRECTION OUTPUT ;
    USE SIGNAL ;
    PORT
      LAYER M5 ;
        RECT  18.624 34.368 18.648 34.56 ;
    END
  END q[169]
  PIN q[16]
    DIRECTION OUTPUT ;
    USE SIGNAL ;
    PORT
      LAYER M3 ;
        RECT  7.632 34.416 7.65 34.56 ;
    END
  END q[16]
  PIN q[170]
    DIRECTION OUTPUT ;
    USE SIGNAL ;
    PORT
      LAYER M3 ;
        RECT  18.72 34.416 18.738 34.56 ;
    END
    PORT
      LAYER M3 ;
        RECT  18.648 34.428 18.774 34.493 ;
    END
  END q[170]
  PIN q[171]
    DIRECTION OUTPUT ;
    USE SIGNAL ;
    PORT
      LAYER M5 ;
        RECT  18.768 34.368 18.792 34.56 ;
    END
  END q[171]
  PIN q[172]
    DIRECTION OUTPUT ;
    USE SIGNAL ;
    PORT
      LAYER M3 ;
        RECT  18.864 34.416 18.882 34.56 ;
    END
  END q[172]
  PIN q[173]
    DIRECTION OUTPUT ;
    USE SIGNAL ;
    PORT
      LAYER M5 ;
        RECT  18.912 34.368 18.936 34.56 ;
    END
  END q[173]
  PIN q[174]
    DIRECTION OUTPUT ;
    USE SIGNAL ;
    PORT
      LAYER M3 ;
        RECT  19.008 34.416 19.026 34.56 ;
    END
  END q[174]
  PIN q[175]
    DIRECTION OUTPUT ;
    USE SIGNAL ;
    PORT
      LAYER M5 ;
        RECT  19.056 34.368 19.08 34.56 ;
    END
  END q[175]
  PIN q[176]
    DIRECTION OUTPUT ;
    USE SIGNAL ;
    PORT
      LAYER M3 ;
        RECT  19.152 34.416 19.17 34.56 ;
    END
  END q[176]
  PIN q[177]
    DIRECTION OUTPUT ;
    USE SIGNAL ;
    PORT
      LAYER M5 ;
        RECT  19.2 34.368 19.224 34.56 ;
    END
  END q[177]
  PIN q[178]
    DIRECTION OUTPUT ;
    USE SIGNAL ;
    PORT
      LAYER M3 ;
        RECT  19.296 34.416 19.314 34.56 ;
    END
  END q[178]
  PIN q[179]
    DIRECTION OUTPUT ;
    USE SIGNAL ;
    PORT
      LAYER M5 ;
        RECT  19.344 34.368 19.368 34.56 ;
    END
  END q[179]
  PIN q[17]
    DIRECTION OUTPUT ;
    USE SIGNAL ;
    PORT
      LAYER M5 ;
        RECT  7.68 34.368 7.704 34.56 ;
    END
  END q[17]
  PIN q[180]
    DIRECTION OUTPUT ;
    USE SIGNAL ;
    PORT
      LAYER M3 ;
        RECT  19.44 34.416 19.458 34.56 ;
    END
  END q[180]
  PIN q[181]
    DIRECTION OUTPUT ;
    USE SIGNAL ;
    PORT
      LAYER M5 ;
        RECT  19.488 34.368 19.512 34.56 ;
    END
  END q[181]
  PIN q[182]
    DIRECTION OUTPUT ;
    USE SIGNAL ;
    PORT
      LAYER M3 ;
        RECT  19.584 34.416 19.602 34.56 ;
    END
  END q[182]
  PIN q[183]
    DIRECTION OUTPUT ;
    USE SIGNAL ;
    PORT
      LAYER M5 ;
        RECT  19.632 34.368 19.656 34.56 ;
    END
  END q[183]
  PIN q[184]
    DIRECTION OUTPUT ;
    USE SIGNAL ;
    PORT
      LAYER M3 ;
        RECT  19.728 34.416 19.746 34.56 ;
    END
  END q[184]
  PIN q[185]
    DIRECTION OUTPUT ;
    USE SIGNAL ;
    PORT
      LAYER M5 ;
        RECT  19.776 34.368 19.8 34.56 ;
    END
  END q[185]
  PIN q[186]
    DIRECTION OUTPUT ;
    USE SIGNAL ;
    PORT
      LAYER M3 ;
        RECT  19.872 34.416 19.89 34.56 ;
    END
  END q[186]
  PIN q[187]
    DIRECTION OUTPUT ;
    USE SIGNAL ;
    PORT
      LAYER M5 ;
        RECT  19.92 34.368 19.944 34.56 ;
    END
  END q[187]
  PIN q[188]
    DIRECTION OUTPUT ;
    USE SIGNAL ;
    PORT
      LAYER M3 ;
        RECT  20.016 34.416 20.034 34.56 ;
    END
  END q[188]
  PIN q[189]
    DIRECTION OUTPUT ;
    USE SIGNAL ;
    PORT
      LAYER M5 ;
        RECT  20.064 34.368 20.088 34.56 ;
    END
  END q[189]
  PIN q[18]
    DIRECTION OUTPUT ;
    USE SIGNAL ;
    PORT
      LAYER M3 ;
        RECT  7.776 34.416 7.794 34.56 ;
    END
  END q[18]
  PIN q[190]
    DIRECTION OUTPUT ;
    USE SIGNAL ;
    PORT
      LAYER M3 ;
        RECT  20.16 34.416 20.178 34.56 ;
    END
  END q[190]
  PIN q[191]
    DIRECTION OUTPUT ;
    USE SIGNAL ;
    PORT
      LAYER M5 ;
        RECT  20.208 34.368 20.232 34.56 ;
    END
  END q[191]
  PIN q[192]
    DIRECTION OUTPUT ;
    USE SIGNAL ;
    PORT
      LAYER M3 ;
        RECT  20.304 34.416 20.322 34.56 ;
    END
  END q[192]
  PIN q[193]
    DIRECTION OUTPUT ;
    USE SIGNAL ;
    PORT
      LAYER M5 ;
        RECT  20.352 34.368 20.376 34.56 ;
    END
  END q[193]
  PIN q[194]
    DIRECTION OUTPUT ;
    USE SIGNAL ;
    PORT
      LAYER M3 ;
        RECT  20.448 34.416 20.466 34.56 ;
    END
  END q[194]
  PIN q[195]
    DIRECTION OUTPUT ;
    USE SIGNAL ;
    PORT
      LAYER M5 ;
        RECT  20.496 34.368 20.52 34.56 ;
    END
  END q[195]
  PIN q[196]
    DIRECTION OUTPUT ;
    USE SIGNAL ;
    PORT
      LAYER M3 ;
        RECT  20.592 34.416 20.61 34.56 ;
    END
  END q[196]
  PIN q[197]
    DIRECTION OUTPUT ;
    USE SIGNAL ;
    PORT
      LAYER M5 ;
        RECT  20.64 34.368 20.664 34.56 ;
    END
  END q[197]
  PIN q[198]
    DIRECTION OUTPUT ;
    USE SIGNAL ;
    PORT
      LAYER M3 ;
        RECT  20.736 34.416 20.754 34.56 ;
    END
  END q[198]
  PIN q[199]
    DIRECTION OUTPUT ;
    USE SIGNAL ;
    PORT
      LAYER M5 ;
        RECT  20.784 34.368 20.808 34.56 ;
    END
  END q[199]
  PIN q[19]
    DIRECTION OUTPUT ;
    USE SIGNAL ;
    PORT
      LAYER M5 ;
        RECT  7.824 34.368 7.848 34.56 ;
    END
  END q[19]
  PIN q[1]
    DIRECTION OUTPUT ;
    USE SIGNAL ;
    PORT
      LAYER M5 ;
        RECT  6.528 34.368 6.552 34.56 ;
    END
  END q[1]
  PIN q[200]
    DIRECTION OUTPUT ;
    USE SIGNAL ;
    PORT
      LAYER M3 ;
        RECT  20.88 34.416 20.898 34.56 ;
    END
  END q[200]
  PIN q[201]
    DIRECTION OUTPUT ;
    USE SIGNAL ;
    PORT
      LAYER M5 ;
        RECT  20.928 34.368 20.952 34.56 ;
    END
  END q[201]
  PIN q[202]
    DIRECTION OUTPUT ;
    USE SIGNAL ;
    PORT
      LAYER M3 ;
        RECT  21.024 34.416 21.042 34.56 ;
    END
  END q[202]
  PIN q[203]
    DIRECTION OUTPUT ;
    USE SIGNAL ;
    PORT
      LAYER M5 ;
        RECT  21.072 34.368 21.096 34.56 ;
    END
  END q[203]
  PIN q[204]
    DIRECTION OUTPUT ;
    USE SIGNAL ;
    PORT
      LAYER M3 ;
        RECT  21.168 34.416 21.186 34.56 ;
    END
  END q[204]
  PIN q[205]
    DIRECTION OUTPUT ;
    USE SIGNAL ;
    PORT
      LAYER M5 ;
        RECT  21.216 34.368 21.24 34.56 ;
    END
  END q[205]
  PIN q[206]
    DIRECTION OUTPUT ;
    USE SIGNAL ;
    PORT
      LAYER M3 ;
        RECT  21.312 34.416 21.33 34.56 ;
    END
  END q[206]
  PIN q[207]
    DIRECTION OUTPUT ;
    USE SIGNAL ;
    PORT
      LAYER M5 ;
        RECT  21.36 34.368 21.384 34.56 ;
    END
  END q[207]
  PIN q[208]
    DIRECTION OUTPUT ;
    USE SIGNAL ;
    PORT
      LAYER M3 ;
        RECT  21.456 34.416 21.474 34.56 ;
    END
  END q[208]
  PIN q[209]
    DIRECTION OUTPUT ;
    USE SIGNAL ;
    PORT
      LAYER M5 ;
        RECT  21.504 34.368 21.528 34.56 ;
    END
  END q[209]
  PIN q[20]
    DIRECTION OUTPUT ;
    USE SIGNAL ;
    PORT
      LAYER M3 ;
        RECT  7.92 34.416 7.938 34.56 ;
    END
  END q[20]
  PIN q[210]
    DIRECTION OUTPUT ;
    USE SIGNAL ;
    PORT
      LAYER M3 ;
        RECT  21.6 34.416 21.618 34.56 ;
    END
  END q[210]
  PIN q[211]
    DIRECTION OUTPUT ;
    USE SIGNAL ;
    PORT
      LAYER M5 ;
        RECT  21.648 34.368 21.672 34.56 ;
    END
  END q[211]
  PIN q[212]
    DIRECTION OUTPUT ;
    USE SIGNAL ;
    PORT
      LAYER M3 ;
        RECT  21.744 34.416 21.762 34.56 ;
    END
  END q[212]
  PIN q[213]
    DIRECTION OUTPUT ;
    USE SIGNAL ;
    PORT
      LAYER M5 ;
        RECT  21.792 34.368 21.816 34.56 ;
    END
  END q[213]
  PIN q[214]
    DIRECTION OUTPUT ;
    USE SIGNAL ;
    PORT
      LAYER M3 ;
        RECT  21.888 34.416 21.906 34.56 ;
    END
  END q[214]
  PIN q[215]
    DIRECTION OUTPUT ;
    USE SIGNAL ;
    PORT
      LAYER M5 ;
        RECT  21.936 34.368 21.96 34.56 ;
    END
  END q[215]
  PIN q[216]
    DIRECTION OUTPUT ;
    USE SIGNAL ;
    PORT
      LAYER M3 ;
        RECT  22.032 34.416 22.05 34.56 ;
    END
  END q[216]
  PIN q[217]
    DIRECTION OUTPUT ;
    USE SIGNAL ;
    PORT
      LAYER M5 ;
        RECT  22.08 34.368 22.104 34.56 ;
    END
  END q[217]
  PIN q[218]
    DIRECTION OUTPUT ;
    USE SIGNAL ;
    PORT
      LAYER M3 ;
        RECT  22.176 34.416 22.194 34.56 ;
    END
  END q[218]
  PIN q[219]
    DIRECTION OUTPUT ;
    USE SIGNAL ;
    PORT
      LAYER M5 ;
        RECT  22.224 34.368 22.248 34.56 ;
    END
  END q[219]
  PIN q[21]
    DIRECTION OUTPUT ;
    USE SIGNAL ;
    PORT
      LAYER M5 ;
        RECT  7.968 34.368 7.992 34.56 ;
    END
  END q[21]
  PIN q[220]
    DIRECTION OUTPUT ;
    USE SIGNAL ;
    PORT
      LAYER M3 ;
        RECT  22.32 34.416 22.338 34.56 ;
    END
  END q[220]
  PIN q[221]
    DIRECTION OUTPUT ;
    USE SIGNAL ;
    PORT
      LAYER M5 ;
        RECT  22.368 34.368 22.392 34.56 ;
    END
  END q[221]
  PIN q[222]
    DIRECTION OUTPUT ;
    USE SIGNAL ;
    PORT
      LAYER M3 ;
        RECT  22.464 34.416 22.482 34.56 ;
    END
  END q[222]
  PIN q[223]
    DIRECTION OUTPUT ;
    USE SIGNAL ;
    PORT
      LAYER M5 ;
        RECT  22.512 34.368 22.536 34.56 ;
    END
  END q[223]
  PIN q[224]
    DIRECTION OUTPUT ;
    USE SIGNAL ;
    PORT
      LAYER M3 ;
        RECT  22.608 34.416 22.626 34.56 ;
    END
  END q[224]
  PIN q[225]
    DIRECTION OUTPUT ;
    USE SIGNAL ;
    PORT
      LAYER M5 ;
        RECT  22.656 34.368 22.68 34.56 ;
    END
  END q[225]
  PIN q[226]
    DIRECTION OUTPUT ;
    USE SIGNAL ;
    PORT
      LAYER M3 ;
        RECT  22.752 34.416 22.77 34.56 ;
    END
  END q[226]
  PIN q[227]
    DIRECTION OUTPUT ;
    USE SIGNAL ;
    PORT
      LAYER M5 ;
        RECT  22.8 34.368 22.824 34.56 ;
    END
  END q[227]
  PIN q[228]
    DIRECTION OUTPUT ;
    USE SIGNAL ;
    PORT
      LAYER M3 ;
        RECT  22.896 34.416 22.914 34.56 ;
    END
  END q[228]
  PIN q[229]
    DIRECTION OUTPUT ;
    USE SIGNAL ;
    PORT
      LAYER M5 ;
        RECT  22.944 34.368 22.968 34.56 ;
    END
  END q[229]
  PIN q[22]
    DIRECTION OUTPUT ;
    USE SIGNAL ;
    PORT
      LAYER M3 ;
        RECT  8.064 34.416 8.082 34.56 ;
    END
  END q[22]
  PIN q[230]
    DIRECTION OUTPUT ;
    USE SIGNAL ;
    PORT
      LAYER M3 ;
        RECT  23.04 34.416 23.058 34.56 ;
    END
  END q[230]
  PIN q[231]
    DIRECTION OUTPUT ;
    USE SIGNAL ;
    PORT
      LAYER M5 ;
        RECT  23.088 34.368 23.112 34.56 ;
    END
  END q[231]
  PIN q[232]
    DIRECTION OUTPUT ;
    USE SIGNAL ;
    PORT
      LAYER M3 ;
        RECT  23.184 34.416 23.202 34.56 ;
    END
  END q[232]
  PIN q[233]
    DIRECTION OUTPUT ;
    USE SIGNAL ;
    PORT
      LAYER M5 ;
        RECT  23.232 34.368 23.256 34.56 ;
    END
  END q[233]
  PIN q[234]
    DIRECTION OUTPUT ;
    USE SIGNAL ;
    PORT
      LAYER M3 ;
        RECT  23.328 34.416 23.346 34.56 ;
    END
  END q[234]
  PIN q[235]
    DIRECTION OUTPUT ;
    USE SIGNAL ;
    PORT
      LAYER M5 ;
        RECT  23.376 34.368 23.4 34.56 ;
    END
  END q[235]
  PIN q[236]
    DIRECTION OUTPUT ;
    USE SIGNAL ;
    PORT
      LAYER M3 ;
        RECT  23.472 34.416 23.49 34.56 ;
    END
  END q[236]
  PIN q[237]
    DIRECTION OUTPUT ;
    USE SIGNAL ;
    PORT
      LAYER M5 ;
        RECT  23.52 34.368 23.544 34.56 ;
    END
  END q[237]
  PIN q[238]
    DIRECTION OUTPUT ;
    USE SIGNAL ;
    PORT
      LAYER M3 ;
        RECT  23.616 34.416 23.634 34.56 ;
    END
  END q[238]
  PIN q[239]
    DIRECTION OUTPUT ;
    USE SIGNAL ;
    PORT
      LAYER M5 ;
        RECT  23.664 34.368 23.688 34.56 ;
    END
  END q[239]
  PIN q[23]
    DIRECTION OUTPUT ;
    USE SIGNAL ;
    PORT
      LAYER M5 ;
        RECT  8.112 34.368 8.136 34.56 ;
    END
  END q[23]
  PIN q[240]
    DIRECTION OUTPUT ;
    USE SIGNAL ;
    PORT
      LAYER M3 ;
        RECT  23.76 34.416 23.778 34.56 ;
    END
  END q[240]
  PIN q[241]
    DIRECTION OUTPUT ;
    USE SIGNAL ;
    PORT
      LAYER M5 ;
        RECT  23.808 34.368 23.832 34.56 ;
    END
  END q[241]
  PIN q[242]
    DIRECTION OUTPUT ;
    USE SIGNAL ;
    PORT
      LAYER M3 ;
        RECT  23.904 34.416 23.922 34.56 ;
    END
  END q[242]
  PIN q[243]
    DIRECTION OUTPUT ;
    USE SIGNAL ;
    PORT
      LAYER M5 ;
        RECT  23.952 34.368 23.976 34.56 ;
    END
  END q[243]
  PIN q[244]
    DIRECTION OUTPUT ;
    USE SIGNAL ;
    PORT
      LAYER M3 ;
        RECT  24.048 34.416 24.066 34.56 ;
    END
  END q[244]
  PIN q[245]
    DIRECTION OUTPUT ;
    USE SIGNAL ;
    PORT
      LAYER M5 ;
        RECT  24.096 34.368 24.12 34.56 ;
    END
  END q[245]
  PIN q[246]
    DIRECTION OUTPUT ;
    USE SIGNAL ;
    PORT
      LAYER M3 ;
        RECT  24.192 34.416 24.21 34.56 ;
    END
  END q[246]
  PIN q[247]
    DIRECTION OUTPUT ;
    USE SIGNAL ;
    PORT
      LAYER M5 ;
        RECT  24.24 34.368 24.264 34.56 ;
    END
  END q[247]
  PIN q[248]
    DIRECTION OUTPUT ;
    USE SIGNAL ;
    PORT
      LAYER M3 ;
        RECT  24.336 34.416 24.354 34.56 ;
    END
  END q[248]
  PIN q[249]
    DIRECTION OUTPUT ;
    USE SIGNAL ;
    PORT
      LAYER M5 ;
        RECT  24.384 34.368 24.408 34.56 ;
    END
  END q[249]
  PIN q[24]
    DIRECTION OUTPUT ;
    USE SIGNAL ;
    PORT
      LAYER M3 ;
        RECT  8.208 34.416 8.226 34.56 ;
    END
  END q[24]
  PIN q[250]
    DIRECTION OUTPUT ;
    USE SIGNAL ;
    PORT
      LAYER M3 ;
        RECT  24.48 34.416 24.498 34.56 ;
    END
  END q[250]
  PIN q[251]
    DIRECTION OUTPUT ;
    USE SIGNAL ;
    PORT
      LAYER M5 ;
        RECT  24.528 34.368 24.552 34.56 ;
    END
  END q[251]
  PIN q[252]
    DIRECTION OUTPUT ;
    USE SIGNAL ;
    PORT
      LAYER M3 ;
        RECT  24.624 34.416 24.642 34.56 ;
    END
  END q[252]
  PIN q[253]
    DIRECTION OUTPUT ;
    USE SIGNAL ;
    PORT
      LAYER M5 ;
        RECT  24.672 34.368 24.696 34.56 ;
    END
  END q[253]
  PIN q[254]
    DIRECTION OUTPUT ;
    USE SIGNAL ;
    PORT
      LAYER M3 ;
        RECT  24.768 34.416 24.786 34.56 ;
    END
  END q[254]
  PIN q[255]
    DIRECTION OUTPUT ;
    USE SIGNAL ;
    PORT
      LAYER M5 ;
        RECT  24.816 34.368 24.84 34.56 ;
    END
  END q[255]
  PIN q[256]
    DIRECTION OUTPUT ;
    USE SIGNAL ;
    PORT
      LAYER M3 ;
        RECT  24.912 34.416 24.93 34.56 ;
    END
  END q[256]
  PIN q[257]
    DIRECTION OUTPUT ;
    USE SIGNAL ;
    PORT
      LAYER M5 ;
        RECT  24.96 34.368 24.984 34.56 ;
    END
  END q[257]
  PIN q[258]
    DIRECTION OUTPUT ;
    USE SIGNAL ;
    PORT
      LAYER M3 ;
        RECT  25.056 34.416 25.074 34.56 ;
    END
  END q[258]
  PIN q[259]
    DIRECTION OUTPUT ;
    USE SIGNAL ;
    PORT
      LAYER M5 ;
        RECT  25.104 34.368 25.128 34.56 ;
    END
  END q[259]
  PIN q[25]
    DIRECTION OUTPUT ;
    USE SIGNAL ;
    PORT
      LAYER M5 ;
        RECT  8.256 34.368 8.28 34.56 ;
    END
  END q[25]
  PIN q[260]
    DIRECTION OUTPUT ;
    USE SIGNAL ;
    PORT
      LAYER M3 ;
        RECT  25.2 34.416 25.218 34.56 ;
    END
  END q[260]
  PIN q[261]
    DIRECTION OUTPUT ;
    USE SIGNAL ;
    PORT
      LAYER M5 ;
        RECT  25.248 34.368 25.272 34.56 ;
    END
  END q[261]
  PIN q[262]
    DIRECTION OUTPUT ;
    USE SIGNAL ;
    PORT
      LAYER M3 ;
        RECT  25.344 34.416 25.362 34.56 ;
    END
  END q[262]
  PIN q[263]
    DIRECTION OUTPUT ;
    USE SIGNAL ;
    PORT
      LAYER M5 ;
        RECT  25.392 34.368 25.416 34.56 ;
    END
  END q[263]
  PIN q[264]
    DIRECTION OUTPUT ;
    USE SIGNAL ;
    PORT
      LAYER M3 ;
        RECT  25.488 34.416 25.506 34.56 ;
    END
  END q[264]
  PIN q[265]
    DIRECTION OUTPUT ;
    USE SIGNAL ;
    PORT
      LAYER M5 ;
        RECT  25.536 34.368 25.56 34.56 ;
    END
  END q[265]
  PIN q[266]
    DIRECTION OUTPUT ;
    USE SIGNAL ;
    PORT
      LAYER M3 ;
        RECT  25.632 34.416 25.65 34.56 ;
    END
  END q[266]
  PIN q[267]
    DIRECTION OUTPUT ;
    USE SIGNAL ;
    PORT
      LAYER M5 ;
        RECT  25.68 34.368 25.704 34.56 ;
    END
  END q[267]
  PIN q[268]
    DIRECTION OUTPUT ;
    USE SIGNAL ;
    PORT
      LAYER M3 ;
        RECT  25.776 34.416 25.794 34.56 ;
    END
  END q[268]
  PIN q[269]
    DIRECTION OUTPUT ;
    USE SIGNAL ;
    PORT
      LAYER M5 ;
        RECT  25.824 34.368 25.848 34.56 ;
    END
  END q[269]
  PIN q[26]
    DIRECTION OUTPUT ;
    USE SIGNAL ;
    PORT
      LAYER M3 ;
        RECT  8.352 34.416 8.37 34.56 ;
    END
  END q[26]
  PIN q[270]
    DIRECTION OUTPUT ;
    USE SIGNAL ;
    PORT
      LAYER M3 ;
        RECT  25.92 34.416 25.938 34.56 ;
    END
  END q[270]
  PIN q[271]
    DIRECTION OUTPUT ;
    USE SIGNAL ;
    PORT
      LAYER M5 ;
        RECT  25.968 34.368 25.992 34.56 ;
    END
  END q[271]
  PIN q[272]
    DIRECTION OUTPUT ;
    USE SIGNAL ;
    PORT
      LAYER M3 ;
        RECT  26.064 34.416 26.082 34.56 ;
    END
  END q[272]
  PIN q[273]
    DIRECTION OUTPUT ;
    USE SIGNAL ;
    PORT
      LAYER M5 ;
        RECT  26.112 34.368 26.136 34.56 ;
    END
  END q[273]
  PIN q[274]
    DIRECTION OUTPUT ;
    USE SIGNAL ;
    PORT
      LAYER M3 ;
        RECT  26.208 34.416 26.226 34.56 ;
    END
  END q[274]
  PIN q[275]
    DIRECTION OUTPUT ;
    USE SIGNAL ;
    PORT
      LAYER M5 ;
        RECT  26.256 34.368 26.28 34.56 ;
    END
  END q[275]
  PIN q[276]
    DIRECTION OUTPUT ;
    USE SIGNAL ;
    PORT
      LAYER M3 ;
        RECT  26.352 34.416 26.37 34.56 ;
    END
  END q[276]
  PIN q[277]
    DIRECTION OUTPUT ;
    USE SIGNAL ;
    PORT
      LAYER M5 ;
        RECT  26.4 34.368 26.424 34.56 ;
    END
  END q[277]
  PIN q[278]
    DIRECTION OUTPUT ;
    USE SIGNAL ;
    PORT
      LAYER M3 ;
        RECT  26.496 34.416 26.514 34.56 ;
    END
  END q[278]
  PIN q[279]
    DIRECTION OUTPUT ;
    USE SIGNAL ;
    PORT
      LAYER M5 ;
        RECT  26.544 34.368 26.568 34.56 ;
    END
  END q[279]
  PIN q[27]
    DIRECTION OUTPUT ;
    USE SIGNAL ;
    PORT
      LAYER M5 ;
        RECT  8.4 34.368 8.424 34.56 ;
    END
  END q[27]
  PIN q[280]
    DIRECTION OUTPUT ;
    USE SIGNAL ;
    PORT
      LAYER M3 ;
        RECT  26.64 34.416 26.658 34.56 ;
    END
  END q[280]
  PIN q[281]
    DIRECTION OUTPUT ;
    USE SIGNAL ;
    PORT
      LAYER M5 ;
        RECT  26.688 34.368 26.712 34.56 ;
    END
  END q[281]
  PIN q[282]
    DIRECTION OUTPUT ;
    USE SIGNAL ;
    PORT
      LAYER M3 ;
        RECT  26.784 34.416 26.802 34.56 ;
    END
  END q[282]
  PIN q[283]
    DIRECTION OUTPUT ;
    USE SIGNAL ;
    PORT
      LAYER M5 ;
        RECT  26.832 34.368 26.856 34.56 ;
    END
  END q[283]
  PIN q[284]
    DIRECTION OUTPUT ;
    USE SIGNAL ;
    PORT
      LAYER M3 ;
        RECT  26.928 34.416 26.946 34.56 ;
    END
  END q[284]
  PIN q[285]
    DIRECTION OUTPUT ;
    USE SIGNAL ;
    PORT
      LAYER M5 ;
        RECT  26.976 34.368 27 34.56 ;
    END
  END q[285]
  PIN q[286]
    DIRECTION OUTPUT ;
    USE SIGNAL ;
    PORT
      LAYER M3 ;
        RECT  27.072 34.416 27.09 34.56 ;
    END
  END q[286]
  PIN q[287]
    DIRECTION OUTPUT ;
    USE SIGNAL ;
    PORT
      LAYER M5 ;
        RECT  27.12 34.368 27.144 34.56 ;
    END
  END q[287]
  PIN q[288]
    DIRECTION OUTPUT ;
    USE SIGNAL ;
    PORT
      LAYER M3 ;
        RECT  27.216 34.416 27.234 34.56 ;
    END
  END q[288]
  PIN q[289]
    DIRECTION OUTPUT ;
    USE SIGNAL ;
    PORT
      LAYER M5 ;
        RECT  27.264 34.368 27.288 34.56 ;
    END
  END q[289]
  PIN q[28]
    DIRECTION OUTPUT ;
    USE SIGNAL ;
    PORT
      LAYER M3 ;
        RECT  8.496 34.416 8.514 34.56 ;
    END
  END q[28]
  PIN q[290]
    DIRECTION OUTPUT ;
    USE SIGNAL ;
    PORT
      LAYER M3 ;
        RECT  27.36 34.416 27.378 34.56 ;
    END
  END q[290]
  PIN q[291]
    DIRECTION OUTPUT ;
    USE SIGNAL ;
    PORT
      LAYER M5 ;
        RECT  27.408 34.368 27.432 34.56 ;
    END
  END q[291]
  PIN q[292]
    DIRECTION OUTPUT ;
    USE SIGNAL ;
    PORT
      LAYER M3 ;
        RECT  27.504 34.416 27.522 34.56 ;
    END
  END q[292]
  PIN q[293]
    DIRECTION OUTPUT ;
    USE SIGNAL ;
    PORT
      LAYER M5 ;
        RECT  27.552 34.368 27.576 34.56 ;
    END
  END q[293]
  PIN q[294]
    DIRECTION OUTPUT ;
    USE SIGNAL ;
    PORT
      LAYER M3 ;
        RECT  27.648 34.416 27.666 34.56 ;
    END
  END q[294]
  PIN q[295]
    DIRECTION OUTPUT ;
    USE SIGNAL ;
    PORT
      LAYER M5 ;
        RECT  27.696 34.368 27.72 34.56 ;
    END
  END q[295]
  PIN q[296]
    DIRECTION OUTPUT ;
    USE SIGNAL ;
    PORT
      LAYER M3 ;
        RECT  27.792 34.416 27.81 34.56 ;
    END
  END q[296]
  PIN q[297]
    DIRECTION OUTPUT ;
    USE SIGNAL ;
    PORT
      LAYER M5 ;
        RECT  27.84 34.368 27.864 34.56 ;
    END
  END q[297]
  PIN q[298]
    DIRECTION OUTPUT ;
    USE SIGNAL ;
    PORT
      LAYER M3 ;
        RECT  27.936 34.416 27.954 34.56 ;
    END
  END q[298]
  PIN q[299]
    DIRECTION OUTPUT ;
    USE SIGNAL ;
    PORT
      LAYER M5 ;
        RECT  27.984 34.368 28.008 34.56 ;
    END
  END q[299]
  PIN q[29]
    DIRECTION OUTPUT ;
    USE SIGNAL ;
    PORT
      LAYER M5 ;
        RECT  8.544 34.368 8.568 34.56 ;
    END
  END q[29]
  PIN q[2]
    DIRECTION OUTPUT ;
    USE SIGNAL ;
    PORT
      LAYER M3 ;
        RECT  6.624 34.416 6.642 34.56 ;
    END
  END q[2]
  PIN q[300]
    DIRECTION OUTPUT ;
    USE SIGNAL ;
    PORT
      LAYER M3 ;
        RECT  28.08 34.416 28.098 34.56 ;
    END
  END q[300]
  PIN q[301]
    DIRECTION OUTPUT ;
    USE SIGNAL ;
    PORT
      LAYER M5 ;
        RECT  28.128 34.368 28.152 34.56 ;
    END
  END q[301]
  PIN q[302]
    DIRECTION OUTPUT ;
    USE SIGNAL ;
    PORT
      LAYER M3 ;
        RECT  28.224 34.416 28.242 34.56 ;
    END
  END q[302]
  PIN q[303]
    DIRECTION OUTPUT ;
    USE SIGNAL ;
    PORT
      LAYER M5 ;
        RECT  28.272 34.368 28.296 34.56 ;
    END
  END q[303]
  PIN q[304]
    DIRECTION OUTPUT ;
    USE SIGNAL ;
    PORT
      LAYER M3 ;
        RECT  28.368 34.416 28.386 34.56 ;
    END
  END q[304]
  PIN q[305]
    DIRECTION OUTPUT ;
    USE SIGNAL ;
    PORT
      LAYER M5 ;
        RECT  28.416 34.368 28.44 34.56 ;
    END
  END q[305]
  PIN q[306]
    DIRECTION OUTPUT ;
    USE SIGNAL ;
    PORT
      LAYER M3 ;
        RECT  28.512 34.416 28.53 34.56 ;
    END
  END q[306]
  PIN q[307]
    DIRECTION OUTPUT ;
    USE SIGNAL ;
    PORT
      LAYER M5 ;
        RECT  28.56 34.368 28.584 34.56 ;
    END
  END q[307]
  PIN q[308]
    DIRECTION OUTPUT ;
    USE SIGNAL ;
    PORT
      LAYER M3 ;
        RECT  28.656 34.416 28.674 34.56 ;
    END
  END q[308]
  PIN q[309]
    DIRECTION OUTPUT ;
    USE SIGNAL ;
    PORT
      LAYER M5 ;
        RECT  28.704 34.368 28.728 34.56 ;
    END
  END q[309]
  PIN q[30]
    DIRECTION OUTPUT ;
    USE SIGNAL ;
    PORT
      LAYER M3 ;
        RECT  8.64 34.416 8.658 34.56 ;
    END
  END q[30]
  PIN q[310]
    DIRECTION OUTPUT ;
    USE SIGNAL ;
    PORT
      LAYER M3 ;
        RECT  28.8 34.416 28.818 34.56 ;
    END
  END q[310]
  PIN q[311]
    DIRECTION OUTPUT ;
    USE SIGNAL ;
    PORT
      LAYER M5 ;
        RECT  28.848 34.368 28.872 34.56 ;
    END
  END q[311]
  PIN q[312]
    DIRECTION OUTPUT ;
    USE SIGNAL ;
    PORT
      LAYER M3 ;
        RECT  28.944 34.416 28.962 34.56 ;
    END
  END q[312]
  PIN q[313]
    DIRECTION OUTPUT ;
    USE SIGNAL ;
    PORT
      LAYER M5 ;
        RECT  28.992 34.368 29.016 34.56 ;
    END
  END q[313]
  PIN q[314]
    DIRECTION OUTPUT ;
    USE SIGNAL ;
    PORT
      LAYER M3 ;
        RECT  29.088 34.416 29.106 34.56 ;
    END
  END q[314]
  PIN q[315]
    DIRECTION OUTPUT ;
    USE SIGNAL ;
    PORT
      LAYER M5 ;
        RECT  29.136 34.368 29.16 34.56 ;
    END
  END q[315]
  PIN q[316]
    DIRECTION OUTPUT ;
    USE SIGNAL ;
    PORT
      LAYER M3 ;
        RECT  29.232 34.416 29.25 34.56 ;
    END
  END q[316]
  PIN q[317]
    DIRECTION OUTPUT ;
    USE SIGNAL ;
    PORT
      LAYER M5 ;
        RECT  29.28 34.368 29.304 34.56 ;
    END
  END q[317]
  PIN q[318]
    DIRECTION OUTPUT ;
    USE SIGNAL ;
    PORT
      LAYER M3 ;
        RECT  29.376 34.416 29.394 34.56 ;
    END
  END q[318]
  PIN q[319]
    DIRECTION OUTPUT ;
    USE SIGNAL ;
    PORT
      LAYER M5 ;
        RECT  29.424 34.368 29.448 34.56 ;
    END
  END q[319]
  PIN q[31]
    DIRECTION OUTPUT ;
    USE SIGNAL ;
    PORT
      LAYER M5 ;
        RECT  8.688 34.368 8.712 34.56 ;
    END
  END q[31]
  PIN q[320]
    DIRECTION OUTPUT ;
    USE SIGNAL ;
    PORT
      LAYER M3 ;
        RECT  29.52 34.416 29.538 34.56 ;
    END
  END q[320]
  PIN q[321]
    DIRECTION OUTPUT ;
    USE SIGNAL ;
    PORT
      LAYER M5 ;
        RECT  29.568 34.368 29.592 34.56 ;
    END
  END q[321]
  PIN q[322]
    DIRECTION OUTPUT ;
    USE SIGNAL ;
    PORT
      LAYER M3 ;
        RECT  29.664 34.416 29.682 34.56 ;
    END
  END q[322]
  PIN q[323]
    DIRECTION OUTPUT ;
    USE SIGNAL ;
    PORT
      LAYER M5 ;
        RECT  29.712 34.368 29.736 34.56 ;
    END
  END q[323]
  PIN q[324]
    DIRECTION OUTPUT ;
    USE SIGNAL ;
    PORT
      LAYER M3 ;
        RECT  29.808 34.416 29.826 34.56 ;
    END
  END q[324]
  PIN q[325]
    DIRECTION OUTPUT ;
    USE SIGNAL ;
    PORT
      LAYER M5 ;
        RECT  29.856 34.368 29.88 34.56 ;
    END
  END q[325]
  PIN q[326]
    DIRECTION OUTPUT ;
    USE SIGNAL ;
    PORT
      LAYER M3 ;
        RECT  29.952 34.416 29.97 34.56 ;
    END
  END q[326]
  PIN q[327]
    DIRECTION OUTPUT ;
    USE SIGNAL ;
    PORT
      LAYER M5 ;
        RECT  30 34.368 30.024 34.56 ;
    END
  END q[327]
  PIN q[328]
    DIRECTION OUTPUT ;
    USE SIGNAL ;
    PORT
      LAYER M3 ;
        RECT  30.096 34.416 30.114 34.56 ;
    END
  END q[328]
  PIN q[329]
    DIRECTION OUTPUT ;
    USE SIGNAL ;
    PORT
      LAYER M5 ;
        RECT  30.144 34.368 30.168 34.56 ;
    END
  END q[329]
  PIN q[32]
    DIRECTION OUTPUT ;
    USE SIGNAL ;
    PORT
      LAYER M3 ;
        RECT  8.784 34.416 8.802 34.56 ;
    END
  END q[32]
  PIN q[330]
    DIRECTION OUTPUT ;
    USE SIGNAL ;
    PORT
      LAYER M3 ;
        RECT  30.24 34.416 30.258 34.56 ;
    END
  END q[330]
  PIN q[331]
    DIRECTION OUTPUT ;
    USE SIGNAL ;
    PORT
      LAYER M5 ;
        RECT  30.288 34.368 30.312 34.56 ;
    END
  END q[331]
  PIN q[332]
    DIRECTION OUTPUT ;
    USE SIGNAL ;
    PORT
      LAYER M3 ;
        RECT  30.384 34.416 30.402 34.56 ;
    END
  END q[332]
  PIN q[333]
    DIRECTION OUTPUT ;
    USE SIGNAL ;
    PORT
      LAYER M5 ;
        RECT  30.432 34.368 30.456 34.56 ;
    END
  END q[333]
  PIN q[334]
    DIRECTION OUTPUT ;
    USE SIGNAL ;
    PORT
      LAYER M3 ;
        RECT  30.528 34.416 30.546 34.56 ;
    END
  END q[334]
  PIN q[335]
    DIRECTION OUTPUT ;
    USE SIGNAL ;
    PORT
      LAYER M5 ;
        RECT  30.576 34.368 30.6 34.56 ;
    END
  END q[335]
  PIN q[336]
    DIRECTION OUTPUT ;
    USE SIGNAL ;
    PORT
      LAYER M3 ;
        RECT  30.672 34.416 30.69 34.56 ;
    END
  END q[336]
  PIN q[337]
    DIRECTION OUTPUT ;
    USE SIGNAL ;
    PORT
      LAYER M5 ;
        RECT  30.72 34.368 30.744 34.56 ;
    END
  END q[337]
  PIN q[338]
    DIRECTION OUTPUT ;
    USE SIGNAL ;
    PORT
      LAYER M3 ;
        RECT  30.816 34.416 30.834 34.56 ;
    END
  END q[338]
  PIN q[339]
    DIRECTION OUTPUT ;
    USE SIGNAL ;
    PORT
      LAYER M5 ;
        RECT  30.864 34.368 30.888 34.56 ;
    END
  END q[339]
  PIN q[33]
    DIRECTION OUTPUT ;
    USE SIGNAL ;
    PORT
      LAYER M5 ;
        RECT  8.832 34.368 8.856 34.56 ;
    END
  END q[33]
  PIN q[340]
    DIRECTION OUTPUT ;
    USE SIGNAL ;
    PORT
      LAYER M3 ;
        RECT  30.96 34.416 30.978 34.56 ;
    END
  END q[340]
  PIN q[341]
    DIRECTION OUTPUT ;
    USE SIGNAL ;
    PORT
      LAYER M5 ;
        RECT  31.008 34.368 31.032 34.56 ;
    END
  END q[341]
  PIN q[342]
    DIRECTION OUTPUT ;
    USE SIGNAL ;
    PORT
      LAYER M3 ;
        RECT  31.104 34.416 31.122 34.56 ;
    END
  END q[342]
  PIN q[343]
    DIRECTION OUTPUT ;
    USE SIGNAL ;
    PORT
      LAYER M5 ;
        RECT  31.152 34.368 31.176 34.56 ;
    END
  END q[343]
  PIN q[344]
    DIRECTION OUTPUT ;
    USE SIGNAL ;
    PORT
      LAYER M3 ;
        RECT  31.248 34.416 31.266 34.56 ;
    END
  END q[344]
  PIN q[345]
    DIRECTION OUTPUT ;
    USE SIGNAL ;
    PORT
      LAYER M5 ;
        RECT  31.296 34.368 31.32 34.56 ;
    END
  END q[345]
  PIN q[346]
    DIRECTION OUTPUT ;
    USE SIGNAL ;
    PORT
      LAYER M3 ;
        RECT  31.392 34.416 31.41 34.56 ;
    END
  END q[346]
  PIN q[347]
    DIRECTION OUTPUT ;
    USE SIGNAL ;
    PORT
      LAYER M5 ;
        RECT  31.44 34.368 31.464 34.56 ;
    END
  END q[347]
  PIN q[348]
    DIRECTION OUTPUT ;
    USE SIGNAL ;
    PORT
      LAYER M3 ;
        RECT  31.536 34.416 31.554 34.56 ;
    END
  END q[348]
  PIN q[349]
    DIRECTION OUTPUT ;
    USE SIGNAL ;
    PORT
      LAYER M5 ;
        RECT  31.584 34.368 31.608 34.56 ;
    END
  END q[349]
  PIN q[34]
    DIRECTION OUTPUT ;
    USE SIGNAL ;
    PORT
      LAYER M3 ;
        RECT  8.928 34.416 8.946 34.56 ;
    END
  END q[34]
  PIN q[350]
    DIRECTION OUTPUT ;
    USE SIGNAL ;
    PORT
      LAYER M3 ;
        RECT  31.68 34.416 31.698 34.56 ;
    END
  END q[350]
  PIN q[351]
    DIRECTION OUTPUT ;
    USE SIGNAL ;
    PORT
      LAYER M5 ;
        RECT  31.728 34.368 31.752 34.56 ;
    END
  END q[351]
  PIN q[352]
    DIRECTION OUTPUT ;
    USE SIGNAL ;
    PORT
      LAYER M3 ;
        RECT  31.824 34.416 31.842 34.56 ;
    END
  END q[352]
  PIN q[353]
    DIRECTION OUTPUT ;
    USE SIGNAL ;
    PORT
      LAYER M5 ;
        RECT  31.872 34.368 31.896 34.56 ;
    END
  END q[353]
  PIN q[354]
    DIRECTION OUTPUT ;
    USE SIGNAL ;
    PORT
      LAYER M3 ;
        RECT  31.968 34.416 31.986 34.56 ;
    END
  END q[354]
  PIN q[355]
    DIRECTION OUTPUT ;
    USE SIGNAL ;
    PORT
      LAYER M5 ;
        RECT  32.016 34.368 32.04 34.56 ;
    END
  END q[355]
  PIN q[356]
    DIRECTION OUTPUT ;
    USE SIGNAL ;
    PORT
      LAYER M3 ;
        RECT  32.112 34.416 32.13 34.56 ;
    END
  END q[356]
  PIN q[357]
    DIRECTION OUTPUT ;
    USE SIGNAL ;
    PORT
      LAYER M5 ;
        RECT  32.16 34.368 32.184 34.56 ;
    END
  END q[357]
  PIN q[358]
    DIRECTION OUTPUT ;
    USE SIGNAL ;
    PORT
      LAYER M3 ;
        RECT  32.256 34.416 32.274 34.56 ;
    END
  END q[358]
  PIN q[359]
    DIRECTION OUTPUT ;
    USE SIGNAL ;
    PORT
      LAYER M5 ;
        RECT  32.304 34.368 32.328 34.56 ;
    END
  END q[359]
  PIN q[35]
    DIRECTION OUTPUT ;
    USE SIGNAL ;
    PORT
      LAYER M5 ;
        RECT  8.976 34.368 9 34.56 ;
    END
  END q[35]
  PIN q[360]
    DIRECTION OUTPUT ;
    USE SIGNAL ;
    PORT
      LAYER M3 ;
        RECT  32.4 34.416 32.418 34.56 ;
    END
  END q[360]
  PIN q[361]
    DIRECTION OUTPUT ;
    USE SIGNAL ;
    PORT
      LAYER M5 ;
        RECT  32.448 34.368 32.472 34.56 ;
    END
  END q[361]
  PIN q[362]
    DIRECTION OUTPUT ;
    USE SIGNAL ;
    PORT
      LAYER M3 ;
        RECT  32.544 34.416 32.562 34.56 ;
    END
  END q[362]
  PIN q[363]
    DIRECTION OUTPUT ;
    USE SIGNAL ;
    PORT
      LAYER M5 ;
        RECT  32.592 34.368 32.616 34.56 ;
    END
  END q[363]
  PIN q[364]
    DIRECTION OUTPUT ;
    USE SIGNAL ;
    PORT
      LAYER M3 ;
        RECT  32.688 34.416 32.706 34.56 ;
    END
  END q[364]
  PIN q[365]
    DIRECTION OUTPUT ;
    USE SIGNAL ;
    PORT
      LAYER M5 ;
        RECT  32.736 34.368 32.76 34.56 ;
    END
  END q[365]
  PIN q[366]
    DIRECTION OUTPUT ;
    USE SIGNAL ;
    PORT
      LAYER M3 ;
        RECT  32.832 34.416 32.85 34.56 ;
    END
  END q[366]
  PIN q[367]
    DIRECTION OUTPUT ;
    USE SIGNAL ;
    PORT
      LAYER M5 ;
        RECT  32.88 34.368 32.904 34.56 ;
    END
  END q[367]
  PIN q[368]
    DIRECTION OUTPUT ;
    USE SIGNAL ;
    PORT
      LAYER M3 ;
        RECT  32.976 34.416 32.994 34.56 ;
    END
  END q[368]
  PIN q[369]
    DIRECTION OUTPUT ;
    USE SIGNAL ;
    PORT
      LAYER M5 ;
        RECT  33.024 34.368 33.048 34.56 ;
    END
  END q[369]
  PIN q[36]
    DIRECTION OUTPUT ;
    USE SIGNAL ;
    PORT
      LAYER M3 ;
        RECT  9.072 34.416 9.09 34.56 ;
    END
  END q[36]
  PIN q[370]
    DIRECTION OUTPUT ;
    USE SIGNAL ;
    PORT
      LAYER M3 ;
        RECT  33.12 34.416 33.138 34.56 ;
    END
  END q[370]
  PIN q[371]
    DIRECTION OUTPUT ;
    USE SIGNAL ;
    PORT
      LAYER M5 ;
        RECT  33.168 34.368 33.192 34.56 ;
    END
  END q[371]
  PIN q[372]
    DIRECTION OUTPUT ;
    USE SIGNAL ;
    PORT
      LAYER M3 ;
        RECT  33.264 34.416 33.282 34.56 ;
    END
  END q[372]
  PIN q[373]
    DIRECTION OUTPUT ;
    USE SIGNAL ;
    PORT
      LAYER M5 ;
        RECT  33.312 34.368 33.336 34.56 ;
    END
  END q[373]
  PIN q[374]
    DIRECTION OUTPUT ;
    USE SIGNAL ;
    PORT
      LAYER M3 ;
        RECT  33.408 34.416 33.426 34.56 ;
    END
  END q[374]
  PIN q[375]
    DIRECTION OUTPUT ;
    USE SIGNAL ;
    PORT
      LAYER M5 ;
        RECT  33.456 34.368 33.48 34.56 ;
    END
  END q[375]
  PIN q[376]
    DIRECTION OUTPUT ;
    USE SIGNAL ;
    PORT
      LAYER M3 ;
        RECT  33.552 34.416 33.57 34.56 ;
    END
  END q[376]
  PIN q[377]
    DIRECTION OUTPUT ;
    USE SIGNAL ;
    PORT
      LAYER M5 ;
        RECT  33.6 34.368 33.624 34.56 ;
    END
  END q[377]
  PIN q[378]
    DIRECTION OUTPUT ;
    USE SIGNAL ;
    PORT
      LAYER M3 ;
        RECT  33.696 34.416 33.714 34.56 ;
    END
  END q[378]
  PIN q[379]
    DIRECTION OUTPUT ;
    USE SIGNAL ;
    PORT
      LAYER M5 ;
        RECT  33.744 34.368 33.768 34.56 ;
    END
  END q[379]
  PIN q[37]
    DIRECTION OUTPUT ;
    USE SIGNAL ;
    PORT
      LAYER M5 ;
        RECT  9.12 34.368 9.144 34.56 ;
    END
  END q[37]
  PIN q[380]
    DIRECTION OUTPUT ;
    USE SIGNAL ;
    PORT
      LAYER M3 ;
        RECT  33.84 34.416 33.858 34.56 ;
    END
  END q[380]
  PIN q[381]
    DIRECTION OUTPUT ;
    USE SIGNAL ;
    PORT
      LAYER M5 ;
        RECT  33.888 34.368 33.912 34.56 ;
    END
  END q[381]
  PIN q[382]
    DIRECTION OUTPUT ;
    USE SIGNAL ;
    PORT
      LAYER M3 ;
        RECT  33.984 34.416 34.002 34.56 ;
    END
  END q[382]
  PIN q[383]
    DIRECTION OUTPUT ;
    USE SIGNAL ;
    PORT
      LAYER M5 ;
        RECT  34.032 34.368 34.056 34.56 ;
    END
  END q[383]
  PIN q[384]
    DIRECTION OUTPUT ;
    USE SIGNAL ;
    PORT
      LAYER M3 ;
        RECT  34.128 34.416 34.146 34.56 ;
    END
  END q[384]
  PIN q[385]
    DIRECTION OUTPUT ;
    USE SIGNAL ;
    PORT
      LAYER M5 ;
        RECT  34.176 34.368 34.2 34.56 ;
    END
  END q[385]
  PIN q[386]
    DIRECTION OUTPUT ;
    USE SIGNAL ;
    PORT
      LAYER M3 ;
        RECT  34.272 34.416 34.29 34.56 ;
    END
  END q[386]
  PIN q[387]
    DIRECTION OUTPUT ;
    USE SIGNAL ;
    PORT
      LAYER M5 ;
        RECT  34.32 34.368 34.344 34.56 ;
    END
  END q[387]
  PIN q[388]
    DIRECTION OUTPUT ;
    USE SIGNAL ;
    PORT
      LAYER M3 ;
        RECT  34.416 34.416 34.434 34.56 ;
    END
  END q[388]
  PIN q[389]
    DIRECTION OUTPUT ;
    USE SIGNAL ;
    PORT
      LAYER M5 ;
        RECT  34.464 34.368 34.488 34.56 ;
    END
  END q[389]
  PIN q[38]
    DIRECTION OUTPUT ;
    USE SIGNAL ;
    PORT
      LAYER M3 ;
        RECT  9.216 34.416 9.234 34.56 ;
    END
  END q[38]
  PIN q[390]
    DIRECTION OUTPUT ;
    USE SIGNAL ;
    PORT
      LAYER M3 ;
        RECT  34.56 34.416 34.578 34.56 ;
    END
  END q[390]
  PIN q[391]
    DIRECTION OUTPUT ;
    USE SIGNAL ;
    PORT
      LAYER M5 ;
        RECT  34.608 34.368 34.632 34.56 ;
    END
  END q[391]
  PIN q[392]
    DIRECTION OUTPUT ;
    USE SIGNAL ;
    PORT
      LAYER M3 ;
        RECT  34.704 34.416 34.722 34.56 ;
    END
    PORT
      LAYER M3 ;
        RECT  34.632 34.428 34.758 34.493 ;
    END
  END q[392]
  PIN q[393]
    DIRECTION OUTPUT ;
    USE SIGNAL ;
    PORT
      LAYER M5 ;
        RECT  34.752 34.368 34.776 34.56 ;
    END
  END q[393]
  PIN q[394]
    DIRECTION OUTPUT ;
    USE SIGNAL ;
    PORT
      LAYER M3 ;
        RECT  34.848 34.416 34.866 34.56 ;
    END
  END q[394]
  PIN q[395]
    DIRECTION OUTPUT ;
    USE SIGNAL ;
    PORT
      LAYER M5 ;
        RECT  34.896 34.368 34.92 34.56 ;
    END
  END q[395]
  PIN q[396]
    DIRECTION OUTPUT ;
    USE SIGNAL ;
    PORT
      LAYER M3 ;
        RECT  34.992 34.416 35.01 34.56 ;
    END
  END q[396]
  PIN q[397]
    DIRECTION OUTPUT ;
    USE SIGNAL ;
    PORT
      LAYER M5 ;
        RECT  35.04 34.368 35.064 34.56 ;
    END
  END q[397]
  PIN q[398]
    DIRECTION OUTPUT ;
    USE SIGNAL ;
    PORT
      LAYER M3 ;
        RECT  35.136 34.416 35.154 34.56 ;
    END
  END q[398]
  PIN q[399]
    DIRECTION OUTPUT ;
    USE SIGNAL ;
    PORT
      LAYER M5 ;
        RECT  35.184 34.368 35.208 34.56 ;
    END
  END q[399]
  PIN q[39]
    DIRECTION OUTPUT ;
    USE SIGNAL ;
    PORT
      LAYER M5 ;
        RECT  9.264 34.368 9.288 34.56 ;
    END
  END q[39]
  PIN q[3]
    DIRECTION OUTPUT ;
    USE SIGNAL ;
    PORT
      LAYER M5 ;
        RECT  6.672 34.368 6.696 34.56 ;
    END
  END q[3]
  PIN q[400]
    DIRECTION OUTPUT ;
    USE SIGNAL ;
    PORT
      LAYER M3 ;
        RECT  35.28 34.416 35.298 34.56 ;
    END
  END q[400]
  PIN q[401]
    DIRECTION OUTPUT ;
    USE SIGNAL ;
    PORT
      LAYER M5 ;
        RECT  35.328 34.368 35.352 34.56 ;
    END
  END q[401]
  PIN q[402]
    DIRECTION OUTPUT ;
    USE SIGNAL ;
    PORT
      LAYER M3 ;
        RECT  35.424 34.416 35.442 34.56 ;
    END
  END q[402]
  PIN q[403]
    DIRECTION OUTPUT ;
    USE SIGNAL ;
    PORT
      LAYER M5 ;
        RECT  35.472 34.368 35.496 34.56 ;
    END
  END q[403]
  PIN q[404]
    DIRECTION OUTPUT ;
    USE SIGNAL ;
    PORT
      LAYER M3 ;
        RECT  35.568 34.416 35.586 34.56 ;
    END
  END q[404]
  PIN q[405]
    DIRECTION OUTPUT ;
    USE SIGNAL ;
    PORT
      LAYER M5 ;
        RECT  35.616 34.368 35.64 34.56 ;
    END
  END q[405]
  PIN q[406]
    DIRECTION OUTPUT ;
    USE SIGNAL ;
    PORT
      LAYER M3 ;
        RECT  35.712 34.416 35.73 34.56 ;
    END
  END q[406]
  PIN q[407]
    DIRECTION OUTPUT ;
    USE SIGNAL ;
    PORT
      LAYER M5 ;
        RECT  35.76 34.368 35.784 34.56 ;
    END
  END q[407]
  PIN q[408]
    DIRECTION OUTPUT ;
    USE SIGNAL ;
    PORT
      LAYER M3 ;
        RECT  35.856 34.416 35.874 34.56 ;
    END
  END q[408]
  PIN q[409]
    DIRECTION OUTPUT ;
    USE SIGNAL ;
    PORT
      LAYER M5 ;
        RECT  35.904 34.368 35.928 34.56 ;
    END
  END q[409]
  PIN q[40]
    DIRECTION OUTPUT ;
    USE SIGNAL ;
    PORT
      LAYER M3 ;
        RECT  9.36 34.416 9.378 34.56 ;
    END
  END q[40]
  PIN q[41]
    DIRECTION OUTPUT ;
    USE SIGNAL ;
    PORT
      LAYER M5 ;
        RECT  9.408 34.368 9.432 34.56 ;
    END
  END q[41]
  PIN q[42]
    DIRECTION OUTPUT ;
    USE SIGNAL ;
    PORT
      LAYER M3 ;
        RECT  9.504 34.416 9.522 34.56 ;
    END
  END q[42]
  PIN q[43]
    DIRECTION OUTPUT ;
    USE SIGNAL ;
    PORT
      LAYER M5 ;
        RECT  9.552 34.368 9.576 34.56 ;
    END
  END q[43]
  PIN q[44]
    DIRECTION OUTPUT ;
    USE SIGNAL ;
    PORT
      LAYER M3 ;
        RECT  9.648 34.416 9.666 34.56 ;
    END
  END q[44]
  PIN q[45]
    DIRECTION OUTPUT ;
    USE SIGNAL ;
    PORT
      LAYER M5 ;
        RECT  9.696 34.368 9.72 34.56 ;
    END
  END q[45]
  PIN q[46]
    DIRECTION OUTPUT ;
    USE SIGNAL ;
    PORT
      LAYER M3 ;
        RECT  9.792 34.416 9.81 34.56 ;
    END
  END q[46]
  PIN q[47]
    DIRECTION OUTPUT ;
    USE SIGNAL ;
    PORT
      LAYER M5 ;
        RECT  9.84 34.368 9.864 34.56 ;
    END
  END q[47]
  PIN q[48]
    DIRECTION OUTPUT ;
    USE SIGNAL ;
    PORT
      LAYER M3 ;
        RECT  9.936 34.416 9.954 34.56 ;
    END
  END q[48]
  PIN q[49]
    DIRECTION OUTPUT ;
    USE SIGNAL ;
    PORT
      LAYER M5 ;
        RECT  9.984 34.368 10.008 34.56 ;
    END
  END q[49]
  PIN q[4]
    DIRECTION OUTPUT ;
    USE SIGNAL ;
    PORT
      LAYER M3 ;
        RECT  6.768 34.416 6.786 34.56 ;
    END
  END q[4]
  PIN q[50]
    DIRECTION OUTPUT ;
    USE SIGNAL ;
    PORT
      LAYER M3 ;
        RECT  10.08 34.416 10.098 34.56 ;
    END
  END q[50]
  PIN q[51]
    DIRECTION OUTPUT ;
    USE SIGNAL ;
    PORT
      LAYER M5 ;
        RECT  10.128 34.368 10.152 34.56 ;
    END
  END q[51]
  PIN q[52]
    DIRECTION OUTPUT ;
    USE SIGNAL ;
    PORT
      LAYER M3 ;
        RECT  10.224 34.416 10.242 34.56 ;
    END
  END q[52]
  PIN q[53]
    DIRECTION OUTPUT ;
    USE SIGNAL ;
    PORT
      LAYER M5 ;
        RECT  10.272 34.368 10.296 34.56 ;
    END
  END q[53]
  PIN q[54]
    DIRECTION OUTPUT ;
    USE SIGNAL ;
    PORT
      LAYER M3 ;
        RECT  10.368 34.416 10.386 34.56 ;
    END
  END q[54]
  PIN q[55]
    DIRECTION OUTPUT ;
    USE SIGNAL ;
    PORT
      LAYER M5 ;
        RECT  10.416 34.368 10.44 34.56 ;
    END
  END q[55]
  PIN q[56]
    DIRECTION OUTPUT ;
    USE SIGNAL ;
    PORT
      LAYER M3 ;
        RECT  10.512 34.416 10.53 34.56 ;
    END
  END q[56]
  PIN q[57]
    DIRECTION OUTPUT ;
    USE SIGNAL ;
    PORT
      LAYER M5 ;
        RECT  10.56 34.368 10.584 34.56 ;
    END
  END q[57]
  PIN q[58]
    DIRECTION OUTPUT ;
    USE SIGNAL ;
    PORT
      LAYER M3 ;
        RECT  10.656 34.416 10.674 34.56 ;
    END
  END q[58]
  PIN q[59]
    DIRECTION OUTPUT ;
    USE SIGNAL ;
    PORT
      LAYER M5 ;
        RECT  10.704 34.368 10.728 34.56 ;
    END
  END q[59]
  PIN q[5]
    DIRECTION OUTPUT ;
    USE SIGNAL ;
    PORT
      LAYER M5 ;
        RECT  6.816 34.368 6.84 34.56 ;
    END
  END q[5]
  PIN q[60]
    DIRECTION OUTPUT ;
    USE SIGNAL ;
    PORT
      LAYER M3 ;
        RECT  10.8 34.416 10.818 34.56 ;
    END
  END q[60]
  PIN q[61]
    DIRECTION OUTPUT ;
    USE SIGNAL ;
    PORT
      LAYER M5 ;
        RECT  10.848 34.368 10.872 34.56 ;
    END
  END q[61]
  PIN q[62]
    DIRECTION OUTPUT ;
    USE SIGNAL ;
    PORT
      LAYER M3 ;
        RECT  10.944 34.416 10.962 34.56 ;
    END
  END q[62]
  PIN q[63]
    DIRECTION OUTPUT ;
    USE SIGNAL ;
    PORT
      LAYER M5 ;
        RECT  10.992 34.368 11.016 34.56 ;
    END
  END q[63]
  PIN q[64]
    DIRECTION OUTPUT ;
    USE SIGNAL ;
    PORT
      LAYER M3 ;
        RECT  11.088 34.416 11.106 34.56 ;
    END
  END q[64]
  PIN q[65]
    DIRECTION OUTPUT ;
    USE SIGNAL ;
    PORT
      LAYER M5 ;
        RECT  11.136 34.368 11.16 34.56 ;
    END
  END q[65]
  PIN q[66]
    DIRECTION OUTPUT ;
    USE SIGNAL ;
    PORT
      LAYER M3 ;
        RECT  11.232 34.416 11.25 34.56 ;
    END
  END q[66]
  PIN q[67]
    DIRECTION OUTPUT ;
    USE SIGNAL ;
    PORT
      LAYER M5 ;
        RECT  11.28 34.368 11.304 34.56 ;
    END
  END q[67]
  PIN q[68]
    DIRECTION OUTPUT ;
    USE SIGNAL ;
    PORT
      LAYER M3 ;
        RECT  11.376 34.416 11.394 34.56 ;
    END
  END q[68]
  PIN q[69]
    DIRECTION OUTPUT ;
    USE SIGNAL ;
    PORT
      LAYER M5 ;
        RECT  11.424 34.368 11.448 34.56 ;
    END
  END q[69]
  PIN q[6]
    DIRECTION OUTPUT ;
    USE SIGNAL ;
    PORT
      LAYER M3 ;
        RECT  6.912 34.416 6.93 34.56 ;
    END
  END q[6]
  PIN q[70]
    DIRECTION OUTPUT ;
    USE SIGNAL ;
    PORT
      LAYER M3 ;
        RECT  11.52 34.416 11.538 34.56 ;
    END
  END q[70]
  PIN q[71]
    DIRECTION OUTPUT ;
    USE SIGNAL ;
    PORT
      LAYER M5 ;
        RECT  11.568 34.368 11.592 34.56 ;
    END
  END q[71]
  PIN q[72]
    DIRECTION OUTPUT ;
    USE SIGNAL ;
    PORT
      LAYER M3 ;
        RECT  11.664 34.416 11.682 34.56 ;
    END
  END q[72]
  PIN q[73]
    DIRECTION OUTPUT ;
    USE SIGNAL ;
    PORT
      LAYER M5 ;
        RECT  11.712 34.368 11.736 34.56 ;
    END
  END q[73]
  PIN q[74]
    DIRECTION OUTPUT ;
    USE SIGNAL ;
    PORT
      LAYER M3 ;
        RECT  11.808 34.416 11.826 34.56 ;
    END
  END q[74]
  PIN q[75]
    DIRECTION OUTPUT ;
    USE SIGNAL ;
    PORT
      LAYER M5 ;
        RECT  11.856 34.368 11.88 34.56 ;
    END
  END q[75]
  PIN q[76]
    DIRECTION OUTPUT ;
    USE SIGNAL ;
    PORT
      LAYER M3 ;
        RECT  11.952 34.416 11.97 34.56 ;
    END
  END q[76]
  PIN q[77]
    DIRECTION OUTPUT ;
    USE SIGNAL ;
    PORT
      LAYER M5 ;
        RECT  12 34.368 12.024 34.56 ;
    END
  END q[77]
  PIN q[78]
    DIRECTION OUTPUT ;
    USE SIGNAL ;
    PORT
      LAYER M3 ;
        RECT  12.096 34.416 12.114 34.56 ;
    END
  END q[78]
  PIN q[79]
    DIRECTION OUTPUT ;
    USE SIGNAL ;
    PORT
      LAYER M5 ;
        RECT  12.144 34.368 12.168 34.56 ;
    END
  END q[79]
  PIN q[7]
    DIRECTION OUTPUT ;
    USE SIGNAL ;
    PORT
      LAYER M5 ;
        RECT  6.96 34.368 6.984 34.56 ;
    END
  END q[7]
  PIN q[80]
    DIRECTION OUTPUT ;
    USE SIGNAL ;
    PORT
      LAYER M3 ;
        RECT  12.24 34.416 12.258 34.56 ;
    END
  END q[80]
  PIN q[81]
    DIRECTION OUTPUT ;
    USE SIGNAL ;
    PORT
      LAYER M5 ;
        RECT  12.288 34.368 12.312 34.56 ;
    END
  END q[81]
  PIN q[82]
    DIRECTION OUTPUT ;
    USE SIGNAL ;
    PORT
      LAYER M3 ;
        RECT  12.384 34.416 12.402 34.56 ;
    END
  END q[82]
  PIN q[83]
    DIRECTION OUTPUT ;
    USE SIGNAL ;
    PORT
      LAYER M5 ;
        RECT  12.432 34.368 12.456 34.56 ;
    END
  END q[83]
  PIN q[84]
    DIRECTION OUTPUT ;
    USE SIGNAL ;
    PORT
      LAYER M3 ;
        RECT  12.528 34.416 12.546 34.56 ;
    END
  END q[84]
  PIN q[85]
    DIRECTION OUTPUT ;
    USE SIGNAL ;
    PORT
      LAYER M5 ;
        RECT  12.576 34.368 12.6 34.56 ;
    END
  END q[85]
  PIN q[86]
    DIRECTION OUTPUT ;
    USE SIGNAL ;
    PORT
      LAYER M3 ;
        RECT  12.672 34.416 12.69 34.56 ;
    END
  END q[86]
  PIN q[87]
    DIRECTION OUTPUT ;
    USE SIGNAL ;
    PORT
      LAYER M5 ;
        RECT  12.72 34.368 12.744 34.56 ;
    END
  END q[87]
  PIN q[88]
    DIRECTION OUTPUT ;
    USE SIGNAL ;
    PORT
      LAYER M3 ;
        RECT  12.816 34.416 12.834 34.56 ;
    END
  END q[88]
  PIN q[89]
    DIRECTION OUTPUT ;
    USE SIGNAL ;
    PORT
      LAYER M5 ;
        RECT  12.864 34.368 12.888 34.56 ;
    END
  END q[89]
  PIN q[8]
    DIRECTION OUTPUT ;
    USE SIGNAL ;
    PORT
      LAYER M3 ;
        RECT  7.056 34.416 7.074 34.56 ;
    END
  END q[8]
  PIN q[90]
    DIRECTION OUTPUT ;
    USE SIGNAL ;
    PORT
      LAYER M3 ;
        RECT  12.96 34.416 12.978 34.56 ;
    END
  END q[90]
  PIN q[91]
    DIRECTION OUTPUT ;
    USE SIGNAL ;
    PORT
      LAYER M5 ;
        RECT  13.008 34.368 13.032 34.56 ;
    END
  END q[91]
  PIN q[92]
    DIRECTION OUTPUT ;
    USE SIGNAL ;
    PORT
      LAYER M3 ;
        RECT  13.104 34.416 13.122 34.56 ;
    END
  END q[92]
  PIN q[93]
    DIRECTION OUTPUT ;
    USE SIGNAL ;
    PORT
      LAYER M5 ;
        RECT  13.152 34.368 13.176 34.56 ;
    END
  END q[93]
  PIN q[94]
    DIRECTION OUTPUT ;
    USE SIGNAL ;
    PORT
      LAYER M3 ;
        RECT  13.248 34.416 13.266 34.56 ;
    END
  END q[94]
  PIN q[95]
    DIRECTION OUTPUT ;
    USE SIGNAL ;
    PORT
      LAYER M5 ;
        RECT  13.296 34.368 13.32 34.56 ;
    END
  END q[95]
  PIN q[96]
    DIRECTION OUTPUT ;
    USE SIGNAL ;
    PORT
      LAYER M3 ;
        RECT  13.392 34.416 13.41 34.56 ;
    END
  END q[96]
  PIN q[97]
    DIRECTION OUTPUT ;
    USE SIGNAL ;
    PORT
      LAYER M5 ;
        RECT  13.44 34.368 13.464 34.56 ;
    END
  END q[97]
  PIN q[98]
    DIRECTION OUTPUT ;
    USE SIGNAL ;
    PORT
      LAYER M3 ;
        RECT  13.536 34.416 13.554 34.56 ;
    END
  END q[98]
  PIN q[99]
    DIRECTION OUTPUT ;
    USE SIGNAL ;
    PORT
      LAYER M5 ;
        RECT  13.584 34.368 13.608 34.56 ;
    END
  END q[99]
  PIN q[9]
    DIRECTION OUTPUT ;
    USE SIGNAL ;
    PORT
      LAYER M5 ;
        RECT  7.104 34.368 7.128 34.56 ;
    END
  END q[9]
  PIN rst_n
    DIRECTION INPUT ;
    USE SIGNAL ;
    PORT
      LAYER M4 ;
        RECT  0 14.88 0.192 14.904 ;
    END
    PORT
      LAYER M4 ;
        RECT  0.156 14.88 0.245 14.904 ;
    END
  END rst_n
  PIN VDD
    DIRECTION INOUT ;
    USE POWER ;
    PORT
      LAYER M5 ;
        RECT  40.392 2.151 40.512 32.409 ;
        RECT  34.992 2.151 35.112 32.409 ;
        RECT  29.592 2.151 29.712 32.409 ;
        RECT  24.192 2.151 24.312 32.409 ;
        RECT  18.792 2.151 18.912 32.409 ;
        RECT  13.392 2.151 13.512 32.409 ;
        RECT  7.992 2.151 8.112 32.409 ;
        RECT  2.592 2.151 2.712 32.409 ;
    END
  END VDD
  PIN VSS
    DIRECTION INOUT ;
    USE GROUND ;
    PORT
      LAYER M5 ;
        RECT  40.2 2.137 40.32 32.423 ;
        RECT  34.8 2.137 34.92 32.423 ;
        RECT  29.4 2.137 29.52 32.423 ;
        RECT  24 2.137 24.12 32.423 ;
        RECT  18.6 2.137 18.72 32.423 ;
        RECT  13.2 2.137 13.32 32.423 ;
        RECT  7.8 2.137 7.92 32.423 ;
        RECT  2.4 2.137 2.52 32.423 ;
    END
  END VSS
  # OT_OBS_CLOSED layer=M5 d_um=1.536 added=57
  OBS
    LAYER RVTN ;
     RECT  2.16 2.16 41.04 2.295 ;
     RECT  2.16 2.565 41.04 2.835 ;
     RECT  2.16 3.105 41.04 3.375 ;
     RECT  2.16 3.645 41.04 3.915 ;
     RECT  2.16 4.185 41.04 4.455 ;
     RECT  2.16 4.725 41.04 4.995 ;
     RECT  2.16 5.265 41.04 5.535 ;
     RECT  2.16 5.805 41.04 6.075 ;
     RECT  2.16 6.345 41.04 6.615 ;
     RECT  2.16 6.885 41.04 7.155 ;
     RECT  2.16 7.425 41.04 7.695 ;
     RECT  2.16 7.965 41.04 8.235 ;
     RECT  2.16 8.505 41.04 8.775 ;
     RECT  2.16 9.045 41.04 9.315 ;
     RECT  2.16 9.585 41.04 9.855 ;
     RECT  2.16 10.125 41.04 10.395 ;
     RECT  2.16 10.665 41.04 10.935 ;
     RECT  2.16 11.205 41.04 11.475 ;
     RECT  2.16 11.745 41.04 12.015 ;
     RECT  2.16 12.285 41.04 12.555 ;
     RECT  2.16 12.825 41.04 13.095 ;
     RECT  2.16 13.365 41.04 13.635 ;
     RECT  2.16 13.905 41.04 14.175 ;
     RECT  2.16 14.445 41.04 14.715 ;
     RECT  2.16 14.985 41.04 15.255 ;
     RECT  2.16 15.525 41.04 15.795 ;
     RECT  2.16 16.065 41.04 16.335 ;
     RECT  2.16 16.605 41.04 16.875 ;
     RECT  2.16 17.145 41.04 17.415 ;
     RECT  2.16 17.685 41.04 17.955 ;
     RECT  2.16 18.225 41.04 18.495 ;
     RECT  2.16 18.765 41.04 19.035 ;
     RECT  2.16 19.305 41.04 19.575 ;
     RECT  2.16 19.845 41.04 20.115 ;
     RECT  2.16 20.385 41.04 20.655 ;
     RECT  2.16 20.925 41.04 21.195 ;
     RECT  2.16 21.465 41.04 21.735 ;
     RECT  2.16 22.005 41.04 22.275 ;
     RECT  2.16 22.545 41.04 22.815 ;
     RECT  2.16 23.085 41.04 23.355 ;
     RECT  2.16 23.625 41.04 23.895 ;
     RECT  2.16 24.165 41.04 24.435 ;
     RECT  2.16 24.705 41.04 24.975 ;
     RECT  2.16 25.245 41.04 25.515 ;
     RECT  2.16 25.785 41.04 26.055 ;
     RECT  2.16 26.325 41.04 26.595 ;
     RECT  2.16 26.865 41.04 27.135 ;
     RECT  2.16 27.405 41.04 27.675 ;
     RECT  2.16 27.945 41.04 28.215 ;
     RECT  2.16 28.485 41.04 28.755 ;
     RECT  2.16 29.025 41.04 29.295 ;
     RECT  2.16 29.565 41.04 29.835 ;
     RECT  2.16 30.105 41.04 30.375 ;
     RECT  2.16 30.645 41.04 30.915 ;
     RECT  2.16 31.185 41.04 31.455 ;
     RECT  2.16 31.725 41.04 31.995 ;
     RECT  2.16 32.265 41.04 32.4 ;
    LAYER RVTP ;
     RECT  2.16 2.295 41.04 2.565 ;
     RECT  2.16 2.835 41.04 3.105 ;
     RECT  2.16 3.375 41.04 3.645 ;
     RECT  2.16 3.915 41.04 4.185 ;
     RECT  2.16 4.455 41.04 4.725 ;
     RECT  2.16 4.995 41.04 5.265 ;
     RECT  2.16 5.535 41.04 5.805 ;
     RECT  2.16 6.075 41.04 6.345 ;
     RECT  2.16 6.615 41.04 6.885 ;
     RECT  2.16 7.155 41.04 7.425 ;
     RECT  2.16 7.695 41.04 7.965 ;
     RECT  2.16 8.235 41.04 8.505 ;
     RECT  2.16 8.775 41.04 9.045 ;
     RECT  2.16 9.315 41.04 9.585 ;
     RECT  2.16 9.855 41.04 10.125 ;
     RECT  2.16 10.395 41.04 10.665 ;
     RECT  2.16 10.935 41.04 11.205 ;
     RECT  2.16 11.475 41.04 11.745 ;
     RECT  2.16 12.015 41.04 12.285 ;
     RECT  2.16 12.555 41.04 12.825 ;
     RECT  2.16 13.095 41.04 13.365 ;
     RECT  2.16 13.635 41.04 13.905 ;
     RECT  2.16 14.175 41.04 14.445 ;
     RECT  2.16 14.715 41.04 14.985 ;
     RECT  2.16 15.255 41.04 15.525 ;
     RECT  2.16 15.795 41.04 16.065 ;
     RECT  2.16 16.335 41.04 16.605 ;
     RECT  2.16 16.875 41.04 17.145 ;
     RECT  2.16 17.415 41.04 17.685 ;
     RECT  2.16 17.955 41.04 18.225 ;
     RECT  2.16 18.495 41.04 18.765 ;
     RECT  2.16 19.035 41.04 19.305 ;
     RECT  2.16 19.575 41.04 19.845 ;
     RECT  2.16 20.115 41.04 20.385 ;
     RECT  2.16 20.655 41.04 20.925 ;
     RECT  2.16 21.195 41.04 21.465 ;
     RECT  2.16 21.735 41.04 22.005 ;
     RECT  2.16 22.275 41.04 22.545 ;
     RECT  2.16 22.815 41.04 23.085 ;
     RECT  2.16 23.355 41.04 23.625 ;
     RECT  2.16 23.895 41.04 24.165 ;
     RECT  2.16 24.435 41.04 24.705 ;
     RECT  2.16 24.975 41.04 25.245 ;
     RECT  2.16 25.515 41.04 25.785 ;
     RECT  2.16 26.055 41.04 26.325 ;
     RECT  2.16 26.595 41.04 26.865 ;
     RECT  2.16 27.135 41.04 27.405 ;
     RECT  2.16 27.675 41.04 27.945 ;
     RECT  2.16 28.215 41.04 28.485 ;
     RECT  2.16 28.755 41.04 29.025 ;
     RECT  2.16 29.295 41.04 29.565 ;
     RECT  2.16 29.835 41.04 30.105 ;
     RECT  2.16 30.375 41.04 30.645 ;
     RECT  2.16 30.915 41.04 31.185 ;
     RECT  2.16 31.455 41.04 31.725 ;
     RECT  2.16 31.995 41.04 32.265 ;
    LAYER M1 ;
     RECT  2.16 2.151 41.04 32.409 ;
    LAYER M2 ;
     RECT  0.211 14.922 2.16 14.94 ;
     RECT  2.16 2.151 6.439 32.409 ;
     RECT  6.439 1.962 6.547 32.409 ;
     RECT  6.547 1.881 6.619 32.409 ;
     RECT  6.619 1.8 6.943 32.409 ;
     RECT  6.943 1.728 7.223 32.409 ;
     RECT  7.303 0.576 7.511 0.594 ;
     RECT  7.223 1.881 8.059 32.409 ;
     RECT  7.915 33.624 8.159 33.642 ;
     RECT  8.203 0.144 8.303 0.162 ;
     RECT  8.059 1.881 8.419 32.526 ;
     RECT  8.419 1.152 8.519 32.526 ;
     RECT  8.519 1.881 8.635 32.526 ;
     RECT  8.635 1.881 8.923 32.598 ;
     RECT  8.923 1.881 9.131 32.679 ;
     RECT  9.131 1.881 9.203 32.409 ;
     RECT  9.931 34.398 9.967 34.416 ;
     RECT  9.967 34.398 10.067 34.488 ;
     RECT  9.203 1.926 10.075 32.409 ;
     RECT  10.075 1.926 10.219 33.102 ;
     RECT  10.219 1.926 10.319 33.759 ;
     RECT  10.319 33.624 10.463 33.759 ;
     RECT  10.327 0.144 10.823 0.162 ;
     RECT  10.463 33.624 10.859 33.642 ;
     RECT  10.319 1.926 11.803 32.409 ;
     RECT  12.091 33.741 12.523 33.759 ;
     RECT  11.803 1.728 12.623 32.409 ;
     RECT  12.523 33.624 12.739 33.759 ;
     RECT  12.739 33.624 12.839 33.804 ;
     RECT  12.839 33.624 12.947 33.642 ;
     RECT  12.623 1.926 13.135 32.409 ;
     RECT  13.171 0.144 13.271 0.162 ;
     RECT  13.135 1.926 13.271 32.49 ;
     RECT  13.271 1.926 14.963 32.409 ;
     RECT  14.899 33.786 15.143 33.804 ;
     RECT  14.395 0.144 15.547 0.162 ;
     RECT  15.259 33.624 15.611 33.759 ;
     RECT  15.547 0.144 15.647 0.234 ;
     RECT  15.611 33.624 15.755 33.642 ;
     RECT  15.979 1.152 16.079 1.17 ;
     RECT  15.647 0.144 16.295 0.162 ;
     RECT  16.411 33.822 16.511 33.84 ;
     RECT  17.563 33.624 18.239 33.642 ;
     RECT  18.535 0.144 18.743 0.162 ;
     RECT  18.643 34.398 18.743 34.488 ;
     RECT  14.963 1.998 18.779 32.409 ;
     RECT  18.743 34.47 18.779 34.488 ;
     RECT  18.779 2.034 19.219 32.409 ;
     RECT  19.219 2.034 19.319 32.598 ;
     RECT  19.579 1.152 19.931 1.17 ;
     RECT  19.319 2.034 20.299 32.409 ;
     RECT  20.155 33.786 20.299 33.804 ;
     RECT  20.299 2.034 20.363 33.804 ;
     RECT  20.363 2.034 20.435 33.759 ;
     RECT  20.515 0.216 20.587 0.234 ;
     RECT  20.587 0.144 20.795 0.234 ;
     RECT  20.435 2.151 20.831 33.759 ;
     RECT  20.831 33.741 21.011 33.759 ;
     RECT  20.795 0.216 21.047 0.234 ;
     RECT  20.831 2.151 21.919 32.409 ;
     RECT  21.919 2.106 22.171 32.409 ;
     RECT  22.171 33.624 22.675 33.642 ;
     RECT  22.675 33.624 22.847 33.804 ;
     RECT  23.179 33.822 23.279 33.84 ;
     RECT  22.171 1.728 23.423 32.409 ;
     RECT  23.423 1.8 23.927 32.409 ;
     RECT  23.927 1.881 24.043 32.409 ;
     RECT  23.827 0.144 24.187 0.162 ;
     RECT  24.187 0.144 24.359 0.324 ;
     RECT  24.043 1.881 24.475 32.49 ;
     RECT  24.359 0.144 24.971 0.162 ;
     RECT  24.475 1.881 25.051 32.526 ;
     RECT  24.907 33.624 25.051 33.642 ;
     RECT  25.051 1.728 25.259 32.526 ;
     RECT  25.051 33.624 25.259 33.714 ;
     RECT  25.259 1.881 25.691 32.526 ;
     RECT  25.259 33.624 26.051 33.642 ;
     RECT  25.771 0.144 26.159 0.162 ;
     RECT  26.491 34.398 26.527 34.416 ;
     RECT  26.527 34.398 26.627 34.488 ;
     RECT  25.691 1.881 26.635 32.409 ;
     RECT  26.779 0.306 27.139 0.324 ;
     RECT  26.923 33.624 27.211 33.642 ;
     RECT  27.139 0.144 27.239 0.324 ;
     RECT  26.635 1.728 27.499 32.409 ;
     RECT  27.211 33.624 27.931 33.714 ;
     RECT  27.499 1.728 27.959 32.526 ;
     RECT  27.931 33.624 27.967 34.416 ;
     RECT  27.239 0.144 28.031 0.162 ;
     RECT  27.967 33.624 28.067 34.488 ;
     RECT  28.067 33.741 28.355 33.759 ;
     RECT  27.959 1.728 28.463 32.409 ;
     RECT  29.155 33.741 29.191 33.759 ;
     RECT  29.371 0.414 29.543 0.432 ;
     RECT  29.191 33.741 29.651 34.488 ;
     RECT  28.463 1.881 29.659 32.409 ;
     RECT  29.659 1.728 29.803 32.409 ;
     RECT  29.651 33.741 30.091 33.804 ;
     RECT  30.091 33.624 30.191 33.804 ;
     RECT  29.947 0.144 30.335 0.162 ;
     RECT  29.803 1.728 30.371 32.526 ;
     RECT  30.191 33.624 30.515 33.642 ;
     RECT  30.371 1.728 31.595 32.409 ;
     RECT  32.107 0.144 32.207 0.162 ;
     RECT  31.595 1.881 32.395 32.409 ;
     RECT  32.251 33.741 32.395 33.759 ;
     RECT  32.395 33.741 32.423 33.84 ;
     RECT  32.423 33.822 33.035 33.84 ;
     RECT  32.395 1.728 33.259 32.409 ;
     RECT  33.259 1.152 33.467 32.409 ;
     RECT  33.467 1.224 33.503 32.409 ;
     RECT  33.475 0.144 33.575 0.162 ;
     RECT  33.503 1.728 34.411 32.409 ;
     RECT  34.627 34.398 34.727 34.488 ;
     RECT  34.727 34.47 34.763 34.488 ;
     RECT  34.411 1.152 34.771 32.409 ;
     RECT  34.555 33.624 34.771 33.642 ;
     RECT  34.771 1.152 35.159 33.642 ;
     RECT  35.159 1.728 35.375 33.642 ;
     RECT  35.375 33.624 35.563 33.642 ;
     RECT  35.563 33.624 35.591 33.714 ;
     RECT  35.375 1.926 35.807 32.634 ;
     RECT  35.591 33.696 35.843 33.714 ;
     RECT  34.627 0.144 35.879 0.162 ;
     RECT  35.807 1.926 36.743 32.409 ;
     RECT  36.743 1.962 38.219 32.409 ;
     RECT  38.219 2.151 41.04 32.409 ;
    LAYER M3 ;
     RECT  6.48 0.108 35.874 0.167 ;
     RECT  6.48 0.167 35.73 0.571 ;
     RECT  6.264 0.571 35.73 1.723 ;
     RECT  37.332 1.771 37.35 1.921 ;
     RECT  6.264 1.723 35.91 1.993 ;
     RECT  36.72 1.921 37.35 1.993 ;
     RECT  6.264 1.993 37.35 2.101 ;
     RECT  38.196 1.957 38.214 2.101 ;
     RECT  6.264 2.101 38.214 2.219 ;
     RECT  6.264 2.219 37.458 2.371 ;
     RECT  2.415 2.143 2.505 2.413 ;
     RECT  40.215 2.143 40.305 2.413 ;
     RECT  6.228 2.371 37.458 2.641 ;
     RECT  5.796 2.641 37.458 2.861 ;
     RECT  5.796 2.861 37.422 3.029 ;
     RECT  6.228 3.029 37.422 5.701 ;
     RECT  6.156 5.701 37.422 5.741 ;
     RECT  6.228 5.741 37.422 6.035 ;
     RECT  6.372 6.035 37.422 6.781 ;
     RECT  6.336 6.781 37.422 7.867 ;
     RECT  6.084 7.867 37.422 7.925 ;
     RECT  6.336 7.925 37.422 7.997 ;
     RECT  6.336 7.997 8.478 8.815 ;
     RECT  9.216 7.997 37.422 8.815 ;
     RECT  6.336 8.815 37.422 9.311 ;
     RECT  6.444 9.311 37.422 10.741 ;
     RECT  6.372 10.741 37.422 11.741 ;
     RECT  6.84 11.741 37.422 11.813 ;
     RECT  6.948 11.813 37.422 12.361 ;
     RECT  6.948 12.361 37.458 12.785 ;
     RECT  7.056 12.785 37.458 13.027 ;
     RECT  38.196 2.219 38.214 13.027 ;
     RECT  7.056 13.027 38.214 13.397 ;
     RECT  7.056 13.397 38.106 13.711 ;
     RECT  7.02 13.711 38.106 14.099 ;
     RECT  7.02 14.099 37.674 14.675 ;
     RECT  0.216 14.875 0.234 14.945 ;
     RECT  4.536 14.881 4.554 15.053 ;
     RECT  7.02 14.675 37.602 15.989 ;
     RECT  7.02 15.989 37.458 17.951 ;
     RECT  7.02 17.951 37.314 18.031 ;
     RECT  6.732 18.031 37.314 18.149 ;
     RECT  6.732 18.149 37.206 18.185 ;
     RECT  6.732 18.185 37.026 18.797 ;
     RECT  6.732 18.797 36.774 21.271 ;
     RECT  6.624 21.271 36.774 25.313 ;
     RECT  6.624 25.313 36.594 26.401 ;
     RECT  6.624 26.401 36.666 27.365 ;
     RECT  6.624 27.365 35.91 27.905 ;
     RECT  36.648 27.365 36.666 28.493 ;
     RECT  6.696 27.905 35.91 29.101 ;
     RECT  6.624 29.101 35.91 30.221 ;
     RECT  6.624 30.221 35.874 30.811 ;
     RECT  2.415 2.413 2.697 32.147 ;
     RECT  40.215 2.413 40.497 32.147 ;
     RECT  2.415 32.147 2.505 32.417 ;
     RECT  40.215 32.147 40.305 32.417 ;
     RECT  6.48 30.811 35.874 34.428 ;
     RECT  9.972 34.428 10.062 34.493 ;
     RECT  26.532 34.428 26.622 34.493 ;
     RECT  27.972 34.428 28.062 34.493 ;
     RECT  29.196 34.428 29.646 34.493 ;
    LAYER M4 ;
     RECT  0.229 9.552 2.408 9.576 ;
     RECT  2.408 2.148 2.512 32.412 ;
     RECT  2.512 2.418 2.704 32.142 ;
     RECT  6.085 13.152 6.133 13.176 ;
     RECT  6.085 2.016 6.181 2.04 ;
     RECT  6.133 13.152 6.181 13.896 ;
     RECT  6.145 5.712 6.277 5.736 ;
     RECT  6.277 5.088 6.323 6.312 ;
     RECT  6.253 0.576 6.325 0.6 ;
     RECT  6.181 2.016 6.397 2.424 ;
     RECT  2.704 9.552 6.505 9.576 ;
     RECT  6.323 5.088 6.541 5.112 ;
     RECT  6.325 0.576 6.563 0.648 ;
     RECT  6.505 9.552 6.649 9.672 ;
     RECT  6.397 1.728 6.661 2.424 ;
     RECT  6.133 3.456 6.661 3.48 ;
     RECT  6.649 9.12 6.685 9.672 ;
     RECT  6.517 31.968 6.724 31.992 ;
     RECT  6.724 31.968 6.725 32.04 ;
     RECT  6.563 0.624 6.793 0.648 ;
     RECT  6.661 1.728 6.793 3.48 ;
     RECT  6.073 7.872 6.793 7.896 ;
     RECT  6.323 6.24 6.805 6.312 ;
     RECT  6.793 7.392 6.805 7.896 ;
     RECT  6.685 9.12 6.829 9.96 ;
     RECT  6.661 10.992 6.829 11.016 ;
     RECT  6.725 32.016 6.949 32.04 ;
     RECT  6.793 0.624 6.995 3.48 ;
     RECT  6.829 9.12 7.009 11.016 ;
     RECT  6.541 5.04 7.045 5.112 ;
     RECT  6.995 1.776 7.139 3.48 ;
     RECT  7.045 4.608 7.148 5.112 ;
     RECT  6.181 13.152 7.189 14.136 ;
     RECT  6.805 6.24 7.217 7.896 ;
     RECT  7.093 26.208 7.237 26.232 ;
     RECT  7.148 4.512 7.333 5.112 ;
     RECT  7.217 6.24 7.333 7.992 ;
     RECT  7.009 9.12 7.333 11.256 ;
     RECT  7.441 33.696 7.525 33.72 ;
     RECT  7.139 2.016 7.541 3.48 ;
     RECT  7.333 4.512 7.541 11.256 ;
     RECT  7.541 2.016 7.621 11.256 ;
     RECT  7.525 33.648 7.715 33.72 ;
     RECT  7.715 33.648 7.769 33.672 ;
     RECT  7.621 2.016 7.808 11.976 ;
     RECT  7.189 13.104 7.808 14.136 ;
     RECT  6.709 15.456 7.808 15.48 ;
     RECT  7.477 17.04 7.808 17.064 ;
     RECT  7.657 18.768 7.808 18.792 ;
     RECT  7.381 22.176 7.808 22.2 ;
     RECT  7.621 23.376 7.808 23.4 ;
     RECT  7.237 26.16 7.808 26.232 ;
     RECT  6.661 28.416 7.808 28.44 ;
     RECT  7.549 30.816 7.808 30.84 ;
     RECT  6.949 32.016 7.808 32.52 ;
     RECT  7.808 2.016 7.813 32.52 ;
     RECT  7.621 0.288 8.053 0.312 ;
     RECT  8.053 0.288 8.101 0.36 ;
     RECT  7.813 2.016 8.104 33.096 ;
     RECT  8.101 0.288 8.245 0.408 ;
     RECT  8.104 9.552 8.273 15.48 ;
     RECT  8.104 32.496 8.273 33.096 ;
     RECT  8.104 2.016 8.339 5.112 ;
     RECT  8.245 0.192 8.437 0.408 ;
     RECT  8.104 30.816 8.561 30.84 ;
     RECT  8.437 0.192 8.597 0.6 ;
     RECT  8.104 25.632 8.633 26.76 ;
     RECT  8.597 0.288 8.675 0.6 ;
     RECT  8.633 25.68 8.705 26.76 ;
     RECT  8.273 33.072 8.821 33.096 ;
     RECT  8.821 33.072 8.921 33.672 ;
     RECT  8.705 25.872 9.173 26.76 ;
     RECT  8.339 2.016 9.233 4.68 ;
     RECT  9.109 31.92 9.253 31.944 ;
     RECT  9.233 1.728 9.301 4.68 ;
     RECT  8.675 0.576 9.397 0.6 ;
     RECT  9.301 1.728 9.397 5.16 ;
     RECT  9.397 0.576 9.445 5.16 ;
     RECT  8.273 9.552 9.491 14.424 ;
     RECT  9.491 9.552 9.565 9.912 ;
     RECT  9.253 31.92 9.605 32.04 ;
     RECT  9.445 0.576 9.637 5.304 ;
     RECT  8.104 6.288 9.637 7.992 ;
     RECT  9.605 31.92 9.641 31.944 ;
     RECT  9.173 26.16 9.677 26.76 ;
     RECT  9.637 0.576 9.685 7.992 ;
     RECT  9.677 26.16 9.713 26.664 ;
     RECT  9.491 10.896 9.745 14.424 ;
     RECT  8.273 15.456 9.745 15.48 ;
     RECT  9.745 10.896 9.857 15.48 ;
     RECT  9.685 28.464 9.893 28.488 ;
     RECT  9.685 0.288 9.961 7.992 ;
     RECT  9.565 9.12 9.961 9.912 ;
     RECT  9.713 26.16 10.073 26.184 ;
     RECT  8.921 33.648 10.117 33.672 ;
     RECT  10.117 33.648 10.361 33.72 ;
     RECT  9.961 0.288 10.397 9.912 ;
     RECT  10.397 5.712 10.469 9.912 ;
     RECT  10.469 6.144 10.501 9.912 ;
     RECT  9.857 10.896 10.501 12.216 ;
     RECT  10.361 33.648 10.649 33.672 ;
     RECT  10.501 6.144 10.685 12.216 ;
     RECT  10.537 23.376 10.691 23.4 ;
     RECT  10.261 29.04 10.757 29.064 ;
     RECT  10.397 0.288 10.765 4.584 ;
     RECT  10.765 0.288 10.865 1.128 ;
     RECT  10.685 6.288 10.933 12.216 ;
     RECT  9.857 13.296 10.933 15.48 ;
     RECT  10.837 31.344 10.981 31.368 ;
     RECT  10.693 26.208 11.125 26.232 ;
     RECT  10.981 30.816 11.153 31.368 ;
     RECT  11.153 30.816 11.189 30.84 ;
     RECT  10.933 6.288 11.219 15.48 ;
     RECT  11.219 13.296 11.225 15.48 ;
     RECT  11.125 25.68 11.333 26.232 ;
     RECT  11.413 31.92 11.729 31.944 ;
     RECT  11.219 6.288 11.797 12.216 ;
     RECT  10.865 0.288 11.843 0.312 ;
     RECT  11.701 26.688 11.845 26.712 ;
     RECT  10.765 2.208 11.941 4.584 ;
     RECT  11.845 26.688 12.053 26.76 ;
     RECT  11.941 2.208 12.085 4.728 ;
     RECT  11.797 5.808 12.085 12.216 ;
     RECT  12.053 26.688 12.161 26.712 ;
     RECT  11.557 28.464 12.161 28.488 ;
     RECT  11.225 13.296 12.229 15.432 ;
     RECT  12.277 22.32 12.373 22.344 ;
     RECT  11.989 33.648 12.565 33.672 ;
     RECT  12.565 33.648 12.593 33.72 ;
     RECT  12.373 22.272 12.697 22.344 ;
     RECT  12.229 13.296 12.805 15.48 ;
     RECT  12.593 33.696 12.845 33.72 ;
     RECT  12.709 30.72 12.853 30.744 ;
     RECT  12.697 22.224 13.013 22.344 ;
     RECT  12.805 23.376 13.013 23.4 ;
     RECT  11.941 1.152 13.093 1.176 ;
     RECT  12.085 2.208 13.093 12.216 ;
     RECT  12.805 13.2 13.093 15.48 ;
     RECT  11.333 25.68 13.093 25.704 ;
     RECT  13.093 32.64 13.141 32.664 ;
     RECT  13.093 1.152 13.165 12.216 ;
     RECT  13.093 13.2 13.165 15.768 ;
     RECT  13.165 1.152 13.187 15.768 ;
     RECT  13.187 2.016 13.208 15.768 ;
     RECT  13.129 18.72 13.208 18.744 ;
     RECT  13.013 22.224 13.208 23.4 ;
     RECT  12.997 24.384 13.208 24.408 ;
     RECT  13.093 25.68 13.208 25.752 ;
     RECT  12.853 30.672 13.208 30.744 ;
     RECT  13.141 32.544 13.208 32.664 ;
     RECT  13.208 2.016 13.331 32.664 ;
     RECT  13.285 0.528 13.429 0.6 ;
     RECT  13.331 2.016 13.504 32.568 ;
     RECT  13.429 0.384 13.532 0.6 ;
     RECT  13.504 18.72 13.565 18.744 ;
     RECT  13.504 2.016 13.571 10.392 ;
     RECT  13.532 0.192 13.619 0.6 ;
     RECT  13.504 25.584 13.645 25.752 ;
     RECT  13.571 2.256 13.667 10.392 ;
     RECT  13.504 31.92 13.673 32.568 ;
     RECT  13.667 5.664 13.825 10.392 ;
     RECT  13.504 13.68 13.853 16.008 ;
     RECT  13.853 13.872 13.997 16.008 ;
     RECT  13.997 14.256 14.099 16.008 ;
     RECT  13.825 7.92 14.105 10.392 ;
     RECT  14.099 14.544 14.147 16.008 ;
     RECT  13.667 2.256 14.177 4.536 ;
     RECT  13.673 31.92 14.195 32.52 ;
     RECT  14.105 9.12 14.213 10.392 ;
     RECT  13.504 30.192 14.213 30.216 ;
     RECT  14.195 32.496 14.249 32.52 ;
     RECT  13.504 26.736 14.321 26.76 ;
     RECT  14.177 2.304 14.641 4.536 ;
     RECT  13.825 5.664 14.641 6.936 ;
     RECT  14.641 2.304 14.675 6.936 ;
     RECT  13.619 0.288 14.677 0.6 ;
     RECT  14.605 30.768 14.717 30.792 ;
     RECT  14.213 9.312 14.821 10.392 ;
     RECT  13.504 11.424 14.821 12.312 ;
     RECT  13.645 25.68 14.825 25.752 ;
     RECT  14.821 22.32 14.857 22.344 ;
     RECT  14.293 33.648 14.869 33.672 ;
     RECT  14.857 22.224 14.893 22.824 ;
     RECT  14.821 9.312 15.005 12.312 ;
     RECT  14.105 7.92 15.013 7.992 ;
     RECT  14.869 33.648 15.013 33.72 ;
     RECT  14.893 22.032 15.155 22.824 ;
     RECT  15.155 22.32 15.221 22.824 ;
     RECT  14.825 25.728 15.221 25.752 ;
     RECT  14.675 2.304 15.253 6.888 ;
     RECT  15.073 16.944 15.293 16.968 ;
     RECT  14.147 14.544 15.349 15.768 ;
     RECT  15.013 33.648 15.589 33.768 ;
     RECT  15.005 11.376 15.685 12.312 ;
     RECT  15.685 11.376 15.761 12.552 ;
     RECT  15.349 14.208 15.793 15.768 ;
     RECT  15.589 33.072 15.797 33.768 ;
     RECT  15.685 30.816 15.869 30.84 ;
     RECT  15.253 2.208 15.905 6.888 ;
     RECT  15.793 13.92 15.937 15.768 ;
     RECT  15.221 22.8 15.971 22.824 ;
     RECT  15.005 9.312 16.009 9.912 ;
     RECT  15.761 11.376 16.009 11.448 ;
     RECT  15.761 12.528 16.117 12.552 ;
     RECT  15.937 13.68 16.117 15.768 ;
     RECT  15.905 6.288 16.121 6.888 ;
     RECT  15.301 27.312 16.193 27.336 ;
     RECT  16.121 6.288 16.265 6.744 ;
     RECT  15.797 33.648 16.445 33.768 ;
     RECT  15.013 7.92 16.553 7.944 ;
     RECT  14.677 0.288 16.589 0.84 ;
     RECT  16.009 9.312 16.597 11.448 ;
     RECT  15.733 25.872 16.741 26.232 ;
     RECT  16.117 12.528 16.805 15.768 ;
     RECT  15.905 2.208 16.945 5.16 ;
     RECT  16.453 28.464 17.021 28.488 ;
     RECT  16.597 8.544 17.029 11.448 ;
     RECT  16.805 12.528 17.029 13.176 ;
     RECT  16.805 14.304 17.029 15.768 ;
     RECT  16.741 25.872 17.029 26.856 ;
     RECT  15.445 31.92 17.057 31.944 ;
     RECT  17.029 14.304 17.075 16.392 ;
     RECT  17.029 25.68 17.116 26.856 ;
     RECT  16.945 2.208 17.129 5.688 ;
     RECT  17.075 16.368 17.164 16.392 ;
     RECT  17.029 8.544 17.165 13.176 ;
     RECT  17.116 26.208 17.201 26.856 ;
     RECT  17.173 22.176 17.269 22.2 ;
     RECT  17.075 14.304 17.281 15.336 ;
     RECT  16.265 6.672 17.324 6.744 ;
     RECT  17.324 6.672 17.411 7.416 ;
     RECT  17.129 2.256 17.413 5.688 ;
     RECT  17.411 6.672 17.413 6.696 ;
     RECT  17.413 2.256 17.417 6.696 ;
     RECT  16.445 33.648 17.461 33.672 ;
     RECT  17.417 2.544 17.497 6.696 ;
     RECT  17.165 8.544 17.603 13.128 ;
     RECT  17.269 22.176 17.701 22.824 ;
     RECT  17.603 8.544 17.749 12.6 ;
     RECT  17.461 33.648 17.993 33.72 ;
     RECT  16.589 0.288 18.133 0.36 ;
     RECT  17.201 26.208 18.181 26.232 ;
     RECT  17.749 8.496 18.229 12.6 ;
     RECT  17.893 32.496 18.325 32.52 ;
     RECT  18.181 26.16 18.373 26.232 ;
     RECT  18.325 30.72 18.421 30.744 ;
     RECT  18.373 26.16 18.469 26.664 ;
     RECT  18.421 30.72 18.469 30.888 ;
     RECT  18.325 32.496 18.569 33.096 ;
     RECT  17.497 2.544 18.608 5.688 ;
     RECT  17.497 6.672 18.608 6.696 ;
     RECT  18.229 7.776 18.608 12.6 ;
     RECT  17.281 14.832 18.608 15.336 ;
     RECT  18.133 16.368 18.608 16.392 ;
     RECT  17.701 21.648 18.608 22.824 ;
     RECT  18.469 25.68 18.608 26.664 ;
     RECT  18.469 30.72 18.608 30.984 ;
     RECT  18.569 32.496 18.608 32.664 ;
     RECT  18.608 2.148 18.803 32.664 ;
     RECT  18.803 2.148 18.904 32.52 ;
     RECT  18.904 2.148 19.189 5.16 ;
     RECT  18.904 32.496 19.325 32.52 ;
     RECT  18.904 13.104 19.397 14.616 ;
     RECT  19.397 13.632 19.433 14.616 ;
     RECT  18.904 15.984 19.541 16.392 ;
     RECT  18.133 0.288 19.717 0.6 ;
     RECT  18.904 21.648 19.757 22.248 ;
     RECT  19.621 33.648 19.765 33.672 ;
     RECT  18.904 6.288 19.859 9.576 ;
     RECT  19.541 15.984 19.865 16.104 ;
     RECT  18.904 30.816 19.865 30.84 ;
     RECT  19.717 0.288 19.907 0.648 ;
     RECT  19.433 14.4 19.933 14.616 ;
     RECT  18.904 25.872 19.937 26.76 ;
     RECT  19.859 7.968 19.957 9.576 ;
     RECT  18.904 10.656 19.957 12.024 ;
     RECT  19.957 7.968 20.003 12.024 ;
     RECT  19.933 14.4 20.017 14.856 ;
     RECT  20.003 7.968 20.081 8.568 ;
     RECT  19.757 22.224 20.125 22.248 ;
     RECT  20.003 9.552 20.141 12.024 ;
     RECT  19.765 33.648 20.189 33.72 ;
     RECT  20.113 23.376 20.221 23.4 ;
     RECT  19.189 1.728 20.329 5.16 ;
     RECT  19.859 6.288 20.329 6.84 ;
     RECT  20.221 23.136 20.339 23.4 ;
     RECT  20.329 1.728 20.435 6.84 ;
     RECT  19.937 25.872 20.485 26.136 ;
     RECT  20.197 24.48 20.585 24.504 ;
     RECT  20.017 14.4 20.653 14.808 ;
     RECT  19.865 16.08 20.729 16.104 ;
     RECT  20.189 33.648 20.729 33.672 ;
     RECT  20.339 23.376 20.771 23.4 ;
     RECT  20.653 14.208 20.801 14.808 ;
     RECT  20.435 1.728 20.915 5.112 ;
     RECT  20.833 15.984 20.917 16.008 ;
     RECT  20.629 32.496 20.981 32.52 ;
     RECT  20.435 6.288 21.013 6.84 ;
     RECT  19.907 0.384 21.041 0.648 ;
     RECT  20.905 30.768 21.053 30.792 ;
     RECT  20.915 1.728 21.059 5.016 ;
     RECT  21.041 0.24 21.085 0.648 ;
     RECT  20.081 7.968 21.109 7.992 ;
     RECT  20.141 9.552 21.109 12.552 ;
     RECT  20.801 14.208 21.109 14.232 ;
     RECT  21.109 9.552 21.125 14.232 ;
     RECT  21.125 10.656 21.233 14.232 ;
     RECT  21.013 6.288 21.269 6.888 ;
     RECT  21.109 7.968 21.397 8.088 ;
     RECT  21.397 7.392 21.473 8.088 ;
     RECT  20.485 25.68 21.485 26.136 ;
     RECT  21.473 7.392 21.529 8.568 ;
     RECT  21.529 7.488 21.557 8.568 ;
     RECT  21.557 7.488 21.593 7.992 ;
     RECT  21.349 31.92 21.637 31.944 ;
     RECT  21.637 31.344 21.665 31.944 ;
     RECT  21.493 26.736 21.773 26.76 ;
     RECT  21.205 28.464 21.773 28.488 ;
     RECT  21.233 12.528 21.805 14.232 ;
     RECT  21.233 10.656 21.875 11.256 ;
     RECT  21.781 33.648 21.925 33.672 ;
     RECT  21.805 12.528 22.019 14.424 ;
     RECT  21.125 9.552 22.049 9.624 ;
     RECT  21.925 33.072 22.097 33.672 ;
     RECT  21.665 31.344 22.133 31.368 ;
     RECT  22.049 9.024 22.165 9.624 ;
     RECT  22.165 9.024 22.211 10.248 ;
     RECT  22.097 33.648 22.213 33.672 ;
     RECT  21.269 6.288 22.237 6.36 ;
     RECT  22.211 9.552 22.249 10.248 ;
     RECT  22.165 21.648 22.249 21.672 ;
     RECT  21.059 1.728 22.259 4.584 ;
     RECT  21.085 0.144 22.307 0.648 ;
     RECT  22.019 12.528 22.457 12.552 ;
     RECT  22.259 2.256 22.489 4.584 ;
     RECT  22.237 6 22.489 6.36 ;
     RECT  22.489 2.256 22.499 6.36 ;
     RECT  22.213 33.648 22.501 33.72 ;
     RECT  22.499 2.256 22.547 5.16 ;
     RECT  22.547 2.544 22.573 5.16 ;
     RECT  21.875 11.232 22.589 11.256 ;
     RECT  22.019 13.776 22.595 14.424 ;
     RECT  22.633 18.768 22.745 18.792 ;
     RECT  22.669 26.688 22.817 26.712 ;
     RECT  22.501 33.648 22.817 33.816 ;
     RECT  22.525 22.224 22.883 22.248 ;
     RECT  22.595 14.4 22.885 14.424 ;
     RECT  21.593 7.968 22.921 7.992 ;
     RECT  22.817 33.648 23.213 33.768 ;
     RECT  21.485 25.68 23.221 25.704 ;
     RECT  22.589 11.232 23.237 12.216 ;
     RECT  22.249 9.552 23.353 9.96 ;
     RECT  22.921 7.728 23.497 7.992 ;
     RECT  22.789 32.496 23.509 32.568 ;
     RECT  22.885 14.4 23.569 14.664 ;
     RECT  23.509 32.496 23.653 33.096 ;
     RECT  23.569 13.68 23.893 14.664 ;
     RECT  22.573 2.544 24.008 4.68 ;
     RECT  22.499 6.288 24.008 6.36 ;
     RECT  23.497 7.44 24.008 7.992 ;
     RECT  23.353 9.072 24.008 9.96 ;
     RECT  23.237 11.136 24.008 12.216 ;
     RECT  23.893 13.296 24.008 14.664 ;
     RECT  22.957 22.8 24.008 22.824 ;
     RECT  23.221 25.68 24.008 26.232 ;
     RECT  23.653 31.92 24.008 33.096 ;
     RECT  22.307 0.144 24.037 0.6 ;
     RECT  24.037 0.144 24.253 0.696 ;
     RECT  24.253 0.144 24.277 0.792 ;
     RECT  24.008 2.148 24.277 33.096 ;
     RECT  24.277 0.144 24.304 33.096 ;
     RECT  24.304 0.144 24.419 15.624 ;
     RECT  24.304 25.68 24.509 26.472 ;
     RECT  24.304 32.496 24.517 33.096 ;
     RECT  24.419 0.144 24.545 4.776 ;
     RECT  24.509 26.16 24.581 26.472 ;
     RECT  24.545 0.144 24.617 0.792 ;
     RECT  24.304 22.224 24.625 22.296 ;
     RECT  24.581 26.16 24.761 26.184 ;
     RECT  24.304 30.72 24.905 30.744 ;
     RECT  24.625 22.224 24.941 22.248 ;
     RECT  24.419 6.288 24.947 15.624 ;
     RECT  24.517 32.496 24.949 33.672 ;
     RECT  24.617 0.144 25.187 0.696 ;
     RECT  24.947 13.2 25.265 15.624 ;
     RECT  24.949 32.496 25.301 33.72 ;
     RECT  25.301 33.072 25.337 33.72 ;
     RECT  24.947 6.288 25.573 12.168 ;
     RECT  25.337 33.072 25.625 33.672 ;
     RECT  25.265 13.2 25.705 15.432 ;
     RECT  25.573 6.24 25.801 12.168 ;
     RECT  25.187 0.24 25.805 0.696 ;
     RECT  24.545 2.544 25.813 4.776 ;
     RECT  25.801 6.144 25.877 12.168 ;
     RECT  25.813 1.728 25.909 4.776 ;
     RECT  25.625 33.648 25.913 33.672 ;
     RECT  25.909 1.728 25.945 4.824 ;
     RECT  25.877 6.144 25.945 6.36 ;
     RECT  25.813 25.68 25.957 25.704 ;
     RECT  25.945 1.728 26.051 6.36 ;
     RECT  25.877 7.392 26.099 12.168 ;
     RECT  25.705 13.2 26.201 14.76 ;
     RECT  26.101 31.92 26.201 31.992 ;
     RECT  25.957 25.68 26.273 25.8 ;
     RECT  26.201 13.2 26.381 14.664 ;
     RECT  26.201 31.968 26.417 31.992 ;
     RECT  25.669 30.192 26.741 30.216 ;
     RECT  26.099 9.072 26.773 12.168 ;
     RECT  26.381 13.2 26.773 14.52 ;
     RECT  25.805 0.288 26.963 0.696 ;
     RECT  27.013 22.224 27.025 22.248 ;
     RECT  26.389 26.16 27.029 26.712 ;
     RECT  26.051 1.728 27.037 4.824 ;
     RECT  26.051 6.24 27.097 6.36 ;
     RECT  26.773 9.072 27.101 14.52 ;
     RECT  27.025 21.648 27.101 22.248 ;
     RECT  27.037 1.968 27.197 4.824 ;
     RECT  27.097 5.808 27.197 6.36 ;
     RECT  26.099 7.392 27.205 7.992 ;
     RECT  27.101 9.072 27.205 12.36 ;
     RECT  26.965 33.648 27.253 33.672 ;
     RECT  27.197 1.968 27.281 6.36 ;
     RECT  27.281 6.192 27.349 6.36 ;
     RECT  27.205 7.392 27.349 12.36 ;
     RECT  27.101 13.632 27.349 14.52 ;
     RECT  27.277 22.8 27.386 22.872 ;
     RECT  27.349 6.192 27.389 12.36 ;
     RECT  26.963 0.288 27.397 0.456 ;
     RECT  27.397 0.24 27.443 0.456 ;
     RECT  27.386 22.8 27.469 22.824 ;
     RECT  27.443 0.24 27.497 0.36 ;
     RECT  27.349 13.632 27.541 15.432 ;
     RECT  27.541 30.816 27.857 30.84 ;
     RECT  27.101 21.648 27.875 21.672 ;
     RECT  27.389 7.152 27.901 12.36 ;
     RECT  27.901 7.152 27.923 9.72 ;
     RECT  27.923 7.152 28.067 7.416 ;
     RECT  27.397 24.528 28.073 24.552 ;
     RECT  27.253 33.648 28.109 33.72 ;
     RECT  27.281 1.968 28.117 4.776 ;
     RECT  27.029 26.208 28.117 26.232 ;
     RECT  27.923 8.496 28.211 9.72 ;
     RECT  28.117 1.728 28.259 4.776 ;
     RECT  28.117 25.872 28.261 26.232 ;
     RECT  28.259 1.728 28.357 4.728 ;
     RECT  27.541 13.632 28.361 15.576 ;
     RECT  28.261 25.68 28.397 26.232 ;
     RECT  28.397 25.776 28.693 26.232 ;
     RECT  27.497 0.288 28.741 0.36 ;
     RECT  27.901 10.8 28.861 12.36 ;
     RECT  28.361 13.632 28.861 14.904 ;
     RECT  28.549 31.344 28.897 31.368 ;
     RECT  28.067 7.152 28.933 7.176 ;
     RECT  28.897 30.768 28.981 31.368 ;
     RECT  28.109 33.696 29.125 33.72 ;
     RECT  28.741 0.288 29.173 0.408 ;
     RECT  28.357 1.392 29.173 4.728 ;
     RECT  29.077 5.76 29.221 5.784 ;
     RECT  28.981 30.768 29.257 31.944 ;
     RECT  28.211 8.736 29.269 9.72 ;
     RECT  28.861 10.8 29.269 14.904 ;
     RECT  29.125 33.648 29.269 33.72 ;
     RECT  29.269 33.072 29.369 33.72 ;
     RECT  29.173 0.288 29.408 4.728 ;
     RECT  29.221 5.76 29.408 5.832 ;
     RECT  28.933 6.816 29.408 7.176 ;
     RECT  29.269 8.736 29.408 14.904 ;
     RECT  28.465 15.984 29.408 16.008 ;
     RECT  29.269 22.224 29.408 22.248 ;
     RECT  28.693 25.776 29.408 26.76 ;
     RECT  29.257 30.672 29.408 31.944 ;
     RECT  29.408 0.288 29.512 32.412 ;
     RECT  29.512 0.288 29.603 32.142 ;
     RECT  29.369 33.648 29.701 33.72 ;
     RECT  29.603 1.392 29.704 32.142 ;
     RECT  29.704 6.816 29.843 14.808 ;
     RECT  29.603 0.288 29.845 0.408 ;
     RECT  29.701 33.648 29.845 33.768 ;
     RECT  29.845 0.24 29.891 0.408 ;
     RECT  29.704 21.648 29.939 23.976 ;
     RECT  29.845 33.648 29.945 33.816 ;
     RECT  29.843 6.816 30.083 9.096 ;
     RECT  29.939 21.648 30.083 21.672 ;
     RECT  29.939 22.8 30.275 23.976 ;
     RECT  29.704 1.392 30.377 5.832 ;
     RECT  29.843 10.224 30.377 14.808 ;
     RECT  30.377 5.808 30.419 5.832 ;
     RECT  30.275 23.376 30.449 23.976 ;
     RECT  30.449 23.376 30.563 23.496 ;
     RECT  29.945 33.648 30.629 33.72 ;
     RECT  30.563 23.376 30.659 23.4 ;
     RECT  30.629 33.648 30.737 33.672 ;
     RECT  30.083 6.816 30.853 7.416 ;
     RECT  29.704 25.68 30.853 25.896 ;
     RECT  30.377 10.224 30.881 11.304 ;
     RECT  30.083 8.64 30.949 9.096 ;
     RECT  30.881 10.848 30.995 11.304 ;
     RECT  30.853 6.672 31.091 7.416 ;
     RECT  29.891 0.24 31.097 0.36 ;
     RECT  30.377 12.336 31.165 14.808 ;
     RECT  31.129 15.984 31.201 16.008 ;
     RECT  30.995 10.896 31.205 11.304 ;
     RECT  31.091 6.768 31.235 7.416 ;
     RECT  30.853 25.68 31.285 26.232 ;
     RECT  31.201 15.984 31.331 16.2 ;
     RECT  31.141 31.92 31.349 31.944 ;
     RECT  31.285 25.68 31.565 26.664 ;
     RECT  31.165 12.336 31.571 15 ;
     RECT  30.377 1.392 31.597 4.632 ;
     RECT  31.205 10.896 31.619 11.16 ;
     RECT  31.571 14.544 31.765 15 ;
     RECT  31.331 15.984 31.765 16.008 ;
     RECT  31.765 14.544 31.811 16.008 ;
     RECT  31.097 0.288 31.813 0.36 ;
     RECT  31.597 1.392 31.907 4.728 ;
     RECT  30.949 8.64 31.921 9.816 ;
     RECT  31.565 25.68 31.925 26.184 ;
     RECT  31.573 30.72 31.925 30.744 ;
     RECT  31.907 1.392 31.955 4.632 ;
     RECT  31.925 26.16 31.961 26.184 ;
     RECT  31.861 33.648 31.964 33.672 ;
     RECT  30.997 28.512 31.997 28.536 ;
     RECT  32.029 21.648 32.137 21.672 ;
     RECT  32.137 21.648 32.195 22.248 ;
     RECT  31.921 8.544 32.281 9.816 ;
     RECT  31.619 10.896 32.281 11.016 ;
     RECT  31.813 0.288 32.293 0.408 ;
     RECT  31.955 1.392 32.293 4.584 ;
     RECT  31.964 33.648 32.293 33.72 ;
     RECT  31.811 14.544 32.321 15.624 ;
     RECT  32.281 8.544 32.387 11.016 ;
     RECT  32.195 22.224 32.387 22.248 ;
     RECT  32.293 33.648 32.609 33.768 ;
     RECT  32.437 32.496 32.684 32.52 ;
     RECT  32.684 32.496 32.771 33.096 ;
     RECT  32.771 32.496 32.789 32.52 ;
     RECT  31.921 5.664 32.821 5.688 ;
     RECT  31.571 12.336 32.821 13.32 ;
     RECT  32.321 14.544 32.821 15 ;
     RECT  32.821 5.664 32.869 5.784 ;
     RECT  31.235 6.816 32.869 7.416 ;
     RECT  32.581 30.192 32.969 30.216 ;
     RECT  32.869 26.208 33.013 26.232 ;
     RECT  32.293 0.288 33.181 4.584 ;
     RECT  32.869 5.664 33.181 7.416 ;
     RECT  32.387 8.544 33.221 9.816 ;
     RECT  33.181 0.288 33.329 7.416 ;
     RECT  32.387 10.848 33.361 11.016 ;
     RECT  32.821 12.336 33.361 15 ;
     RECT  33.361 10.848 33.401 15 ;
     RECT  33.329 0.288 33.491 6.024 ;
     RECT  33.157 29.616 33.509 29.64 ;
     RECT  33.491 0.288 33.581 4.728 ;
     RECT  33.401 10.848 33.581 13.8 ;
     RECT  33.329 7.344 33.587 7.416 ;
     RECT  33.013 25.68 33.589 26.232 ;
     RECT  33.589 25.68 33.617 26.472 ;
     RECT  33.445 31.92 33.617 31.944 ;
     RECT  33.581 1.968 33.683 4.728 ;
     RECT  33.361 15.984 33.937 16.008 ;
     RECT  33.617 26.208 34.021 26.472 ;
     RECT  33.581 0.288 34.145 0.552 ;
     RECT  34.145 0.192 34.229 0.552 ;
     RECT  34.229 0.288 34.259 0.552 ;
     RECT  33.937 15.984 34.297 16.056 ;
     RECT  33.221 8.832 34.441 9.816 ;
     RECT  34.441 8.496 34.469 9.816 ;
     RECT  33.581 10.848 34.469 13.704 ;
     RECT  34.453 22.8 34.469 22.824 ;
     RECT  34.259 0.288 34.547 0.408 ;
     RECT  34.469 22.224 34.597 22.824 ;
     RECT  34.597 22.224 34.693 23.352 ;
     RECT  34.652 32.448 34.693 32.472 ;
     RECT  34.693 32.448 34.787 32.568 ;
     RECT  33.683 2.064 34.808 4.728 ;
     RECT  33.491 6 34.808 6.024 ;
     RECT  33.587 7.392 34.808 7.416 ;
     RECT  34.469 8.496 34.808 13.704 ;
     RECT  33.401 14.928 34.808 15 ;
     RECT  34.297 15.984 34.808 16.104 ;
     RECT  33.829 18.768 34.808 18.792 ;
     RECT  34.693 22.224 34.808 23.88 ;
     RECT  34.021 26.208 34.808 26.664 ;
     RECT  33.733 30.816 34.808 30.84 ;
     RECT  34.787 32.448 34.808 32.52 ;
     RECT  34.808 2.064 35.029 32.52 ;
     RECT  35.029 1.728 35.104 32.52 ;
     RECT  35.104 1.728 35.219 6.312 ;
     RECT  34.547 0.288 35.267 0.312 ;
     RECT  35.219 4.656 35.267 6.312 ;
     RECT  35.267 4.704 35.353 6.312 ;
     RECT  35.104 7.392 35.363 15 ;
     RECT  35.104 32.496 35.417 32.52 ;
     RECT  35.104 25.056 35.453 25.08 ;
     RECT  35.353 4.704 35.459 6.024 ;
     RECT  35.363 7.968 35.5 15 ;
     RECT  35.459 5.088 35.555 6.024 ;
     RECT  35.5 7.968 35.705 13.752 ;
     RECT  34.309 33.648 35.777 33.672 ;
     RECT  35.705 7.968 35.785 9.768 ;
     RECT  35.104 26.736 35.885 26.76 ;
     RECT  35.219 1.728 35.921 3.432 ;
     RECT  35.104 30.192 35.921 30.216 ;
     RECT  35.104 15.984 35.939 16.104 ;
     RECT  35.555 6 35.957 6.024 ;
     RECT  35.785 8.496 36.035 9.768 ;
     RECT  35.705 10.848 36.137 13.752 ;
     RECT  35.5 14.928 36.227 15 ;
     RECT  36.035 8.976 36.275 9.768 ;
     RECT  36.137 11.376 36.281 13.752 ;
     RECT  36.281 12.528 36.563 13.752 ;
     RECT  36.275 9.744 36.569 9.768 ;
     RECT  36.281 11.376 36.605 11.4 ;
     RECT  36.563 13.008 36.605 13.752 ;
     RECT  36.529 5.136 36.641 5.16 ;
     RECT  35.104 28.464 36.677 28.488 ;
     RECT  35.939 15.984 36.803 16.008 ;
     RECT  35.921 1.776 36.961 3.432 ;
     RECT  36.961 1.776 37.061 3.72 ;
     RECT  36.997 8.496 37.105 8.52 ;
     RECT  36.605 13.104 37.139 13.752 ;
     RECT  37.061 1.776 37.145 3.96 ;
     RECT  37.145 1.776 37.187 3.384 ;
     RECT  36.227 14.976 37.187 15 ;
     RECT  37.105 7.968 37.235 8.52 ;
     RECT  37.187 1.776 37.261 2.856 ;
     RECT  37.261 1.776 37.361 1.8 ;
     RECT  37.235 8.496 37.361 8.52 ;
     RECT  37.139 13.104 37.475 13.128 ;
     RECT  37.261 2.832 37.513 2.856 ;
     RECT  40.208 2.148 40.312 32.412 ;
     RECT  40.312 2.418 40.504 32.142 ;
    LAYER M5 ;
     RECT  25.152 0.133 25.176 0.144 ;
     RECT  6.528 0.144 35.928 0.611 ;
     RECT  6.672 0.611 35.928 0.659 ;
     RECT  6.816 0.659 35.928 2.005 ;
     RECT  2.4 2.137 2.52 2.151 ;
     RECT  40.2 2.137 40.32 2.151 ;
     RECT  6.096 2.005 35.928 2.245 ;
     RECT  6.096 2.245 37.224 2.821 ;
     RECT  6.096 2.821 37.464 6.851 ;
     RECT  6.096 6.851 19.848 7.475 ;
     RECT  6.096 7.475 19.8 8.003 ;
     RECT  15.552 8.003 19.8 9.061 ;
     RECT  20.88 6.851 37.464 9.061 ;
     RECT  6.096 8.003 14.376 9.637 ;
     RECT  15.552 9.061 37.464 9.637 ;
     RECT  6.096 9.637 37.464 10.307 ;
     RECT  20.88 10.307 37.464 10.883 ;
     RECT  6.096 10.307 19.8 11.365 ;
     RECT  20.88 10.883 33.528 11.365 ;
     RECT  6.096 11.365 33.528 11.747 ;
     RECT  34.512 10.883 37.464 11.941 ;
     RECT  6.096 11.747 33.48 12.179 ;
     RECT  6.096 12.179 24.936 12.227 ;
     RECT  10.608 12.227 24.936 12.563 ;
     RECT  26.064 12.179 33.48 12.563 ;
     RECT  6.096 12.227 9.528 12.659 ;
     RECT  34.464 11.941 37.464 13.139 ;
     RECT  6.096 12.659 8.232 13.187 ;
     RECT  33.456 12.563 33.48 13.235 ;
     RECT  10.608 12.563 24.888 13.331 ;
     RECT  9.408 12.659 9.528 13.715 ;
     RECT  10.656 13.331 24.888 13.715 ;
     RECT  9.504 13.715 9.528 13.763 ;
     RECT  6.144 13.187 8.232 13.907 ;
     RECT  6.192 13.907 8.232 14.147 ;
     RECT  22.032 13.715 24.888 14.291 ;
     RECT  26.064 12.563 32.424 14.291 ;
     RECT  22.176 14.291 24.888 14.389 ;
     RECT  6.72 14.147 8.232 14.579 ;
     RECT  27.024 14.291 32.424 14.915 ;
     RECT  34.464 13.139 37.176 15.011 ;
     RECT  10.656 13.715 20.904 15.443 ;
     RECT  22.176 14.389 25.656 15.443 ;
     RECT  6.72 14.579 8.112 15.491 ;
     RECT  12.384 15.443 20.904 15.779 ;
     RECT  0.24 9.541 0.264 15.923 ;
     RECT  12.384 15.779 15.96 16.019 ;
     RECT  17.04 15.779 20.904 16.019 ;
     RECT  27.024 14.915 32.376 16.019 ;
     RECT  34.464 15.011 36.792 16.019 ;
     RECT  34.464 16.019 35.928 16.115 ;
     RECT  29.28 16.019 32.376 16.211 ;
     RECT  17.04 16.019 20.76 16.403 ;
     RECT  22.176 15.443 24.744 21.683 ;
     RECT  27.024 16.019 27.864 21.683 ;
     RECT  32.16 16.211 32.376 21.683 ;
     RECT  14.832 16.019 15.96 22.067 ;
     RECT  7.632 15.491 8.112 22.165 ;
     RECT  17.28 16.403 20.76 22.165 ;
     RECT  17.184 22.165 20.76 22.259 ;
     RECT  22.848 21.683 24.744 22.259 ;
     RECT  27.024 21.683 27.432 22.259 ;
     RECT  29.28 16.211 30.648 22.259 ;
     RECT  32.352 21.683 32.376 22.259 ;
     RECT  23.28 22.259 24.6 22.307 ;
     RECT  12.384 16.019 13.512 22.309 ;
     RECT  14.832 22.067 14.952 22.355 ;
     RECT  14.928 22.355 14.952 22.835 ;
     RECT  15.936 22.067 15.96 22.835 ;
     RECT  17.184 22.259 18.912 22.835 ;
     RECT  23.28 22.307 24.312 22.835 ;
     RECT  27.312 22.259 27.432 22.835 ;
     RECT  34.464 16.115 35.112 22.835 ;
     RECT  27.312 22.835 27.336 22.883 ;
     RECT  10.656 15.443 10.68 23.411 ;
     RECT  20.16 22.259 20.76 23.411 ;
     RECT  29.4 22.259 30.648 23.411 ;
     RECT  29.4 23.411 30.552 23.507 ;
     RECT  29.4 23.507 30.408 23.987 ;
     RECT  34.608 22.835 35.112 25.045 ;
     RECT  12.288 22.309 13.512 25.573 ;
     RECT  7.392 22.165 8.112 25.669 ;
     RECT  12.288 25.573 13.608 25.669 ;
     RECT  17.184 22.835 17.208 25.669 ;
     RECT  18.6 22.835 18.912 25.669 ;
     RECT  20.208 24.469 20.232 25.669 ;
     RECT  24 22.835 24.312 25.669 ;
     RECT  27.408 24.517 27.432 25.669 ;
     RECT  29.4 23.987 29.712 25.669 ;
     RECT  12.144 25.669 14.472 25.717 ;
     RECT  29.4 25.669 30.312 25.717 ;
     RECT  25.824 25.669 25.848 25.765 ;
     RECT  27.408 25.669 28.296 25.765 ;
     RECT  29.4 25.717 30.744 25.765 ;
     RECT  7.392 25.669 8.28 25.861 ;
     RECT  17.04 25.669 17.208 25.861 ;
     RECT  18.48 25.669 18.912 25.861 ;
     RECT  20.208 25.669 20.952 25.861 ;
     RECT  18.48 25.861 20.952 26.101 ;
     RECT  7.392 25.861 8.568 26.149 ;
     RECT  16.176 25.861 17.208 26.149 ;
     RECT  18.48 26.101 21.096 26.149 ;
     RECT  23.088 25.669 24.456 26.149 ;
     RECT  25.824 25.765 25.992 26.149 ;
     RECT  27.408 25.765 30.744 26.149 ;
     RECT  31.728 25.669 31.752 26.149 ;
     RECT  7.248 26.149 8.568 26.197 ;
     RECT  11.136 25.669 11.16 26.197 ;
     RECT  12.144 25.717 14.616 26.197 ;
     RECT  15.888 26.149 17.208 26.197 ;
     RECT  18.192 26.149 21.096 26.197 ;
     RECT  33.024 25.669 33.336 26.197 ;
     RECT  34.608 25.045 35.208 26.197 ;
     RECT  7.104 26.197 8.568 26.629 ;
     RECT  9.552 26.149 9.576 26.629 ;
     RECT  15.744 26.197 21.096 26.725 ;
     RECT  22.08 25.669 22.104 26.725 ;
     RECT  32.88 26.197 35.208 26.725 ;
     RECT  10.704 26.197 14.616 27.301 ;
     RECT  15.744 26.725 22.104 27.301 ;
     RECT  7.104 26.629 9.576 28.405 ;
     RECT  6.672 28.405 9.576 28.453 ;
     RECT  32.88 26.725 35.784 28.453 ;
     RECT  6.672 28.453 9.72 29.029 ;
     RECT  10.704 27.301 22.104 29.029 ;
     RECT  25.824 26.149 31.752 30.181 ;
     RECT  32.88 28.453 35.928 30.181 ;
     RECT  23.088 26.149 24.504 30.709 ;
     RECT  6.672 29.029 22.104 31.957 ;
     RECT  2.4 2.151 2.712 32.409 ;
     RECT  40.2 2.151 40.512 32.409 ;
     RECT  2.4 32.409 2.52 32.423 ;
     RECT  25.68 30.181 35.928 32.423 ;
     RECT  40.2 32.409 40.32 32.423 ;
     RECT  6.528 31.957 22.104 32.485 ;
     RECT  23.088 30.709 24.552 32.485 ;
     RECT  6.528 32.485 24.696 33.061 ;
     RECT  25.68 32.423 29.304 33.061 ;
     RECT  6.528 33.061 29.304 33.637 ;
     RECT  30.288 32.423 35.928 33.637 ;
     RECT  6.528 33.637 35.928 34.384 ;
     RECT  6.528 0.611 6.672 0.659 ;
     RECT  6.528 0.659 6.816 2.005 ;
     RECT  19.848 6.851 20.88 7.475 ;
     RECT  19.8 7.475 20.88 9.061 ;
     RECT  14.376 8.003 15.552 9.637 ;
     RECT  19.8 10.307 20.88 11.365 ;
     RECT  33.528 10.883 34.512 11.747 ;
     RECT  33.48 11.747 34.512 11.941 ;
     RECT  33.48 11.941 34.464 13.235 ;
     RECT  24.936 12.179 26.064 12.563 ;
     RECT  9.528 12.227 10.608 13.331 ;
     RECT  24.888 12.563 26.064 14.291 ;
     RECT  32.424 12.563 33.456 13.235 ;
     RECT  8.232 12.659 9.408 13.715 ;
     RECT  9.528 13.331 10.656 13.763 ;
     RECT  8.232 13.715 9.504 13.763 ;
     RECT  20.904 13.715 22.032 14.291 ;
     RECT  20.904 14.291 22.176 16.019 ;
     RECT  24.888 14.291 27.024 14.389 ;
     RECT  25.656 14.389 27.024 15.443 ;
     RECT  15.96 15.779 17.04 16.403 ;
     RECT  13.512 16.019 14.832 22.355 ;
     RECT  20.76 16.019 22.176 21.683 ;
     RECT  27.864 16.019 29.28 21.683 ;
     RECT  30.648 16.211 32.16 21.683 ;
     RECT  15.96 16.403 17.28 22.165 ;
     RECT  14.952 22.067 15.936 22.835 ;
     RECT  15.96 22.165 17.184 22.835 ;
     RECT  18.912 22.259 20.16 23.411 ;
     RECT  13.512 22.355 14.928 22.835 ;
     RECT  17.208 22.835 18.6 25.669 ;
     RECT  18.912 23.411 20.232 24.469 ;
     RECT  18.912 24.469 20.208 25.861 ;
     RECT  11.16 25.669 12.144 26.197 ;
     RECT  17.208 25.669 18.48 26.149 ;
     RECT  20.952 25.669 22.08 26.101 ;
     RECT  22.104 25.669 23.088 32.485 ;
     RECT  24.456 25.669 25.824 26.149 ;
     RECT  28.296 25.669 29.4 25.765 ;
     RECT  30.312 25.669 31.728 25.717 ;
     RECT  31.752 25.669 33.024 26.197 ;
     RECT  33.336 25.669 34.608 26.197 ;
     RECT  30.744 25.717 31.728 26.149 ;
     RECT  25.992 25.765 27.408 26.149 ;
     RECT  21.096 26.101 22.08 26.725 ;
     RECT  8.568 26.149 9.552 26.629 ;
     RECT  14.616 26.149 15.888 26.197 ;
     RECT  17.208 26.149 18.192 26.197 ;
     RECT  24.504 26.149 25.824 30.181 ;
     RECT  9.576 26.197 10.704 28.453 ;
     RECT  14.616 26.197 15.744 27.301 ;
     RECT  31.752 26.197 32.88 30.181 ;
     RECT  9.72 28.453 10.704 29.029 ;
     RECT  24.504 30.181 25.68 30.709 ;
     RECT  24.552 30.709 25.68 32.485 ;
     RECT  29.304 32.423 30.288 33.637 ;
     RECT  24.696 32.485 25.68 33.061 ;
  END
END ot_s81_pq_bc_slice0
END LIBRARY
